VERSION 5.5 ;
NAMESCASESENSITIVE ON ;
BUSBITCHARS "[]" ;
DIVIDERCHAR "/" ;

PROPERTYDEFINITIONS
  LAYER routingPitch REAL ;
END PROPERTYDEFINITIONS

UNITS
  DATABASE MICRONS 1000 ;
END UNITS
MANUFACTURINGGRID 0.01 ;
LAYER POLY1
  TYPE MASTERSLICE ;
END POLY1

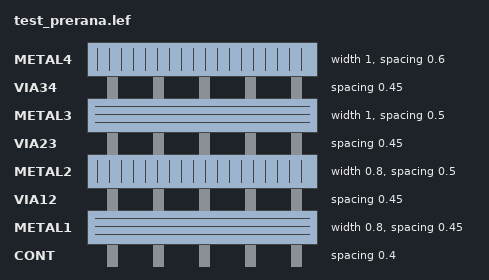
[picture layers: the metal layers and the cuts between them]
LAYER CONT
  TYPE CUT ;
  SPACING 0.4 ;
END CONT

LAYER METAL1
  TYPE ROUTING ;
  DIRECTION HORIZONTAL ;
  PITCH 0 ;
  WIDTH 0.8 ;
  SPACING 0.45 ;
  PROPERTY routingPitch 1.25 ;
END METAL1

LAYER VIA12
  TYPE CUT ;
  SPACING 0.45 ;
END VIA12

LAYER METAL2
  TYPE ROUTING ;
  DIRECTION VERTICAL ;
  PITCH 0 ;
  WIDTH 0.8 ;
  SPACING 0.5 ;
  PROPERTY routingPitch 1.4 ;
END METAL2

LAYER VIA23
  TYPE CUT ;
  SPACING 0.45 ;
END VIA23

LAYER METAL3
  TYPE ROUTING ;
  DIRECTION HORIZONTAL ;
  PITCH 0 ;
  WIDTH 1.0 ;
  SPACING 0.5 ;
  PROPERTY routingPitch 1.25 ;
END METAL3

LAYER VIA34
  TYPE CUT ;
  SPACING 0.45 ;
END VIA34

LAYER METAL4
  TYPE ROUTING ;
  DIRECTION VERTICAL ;
  PITCH 0 ;
  WIDTH 1.0 ;
  SPACING 0.6 ;
  PROPERTY routingPitch 1.4 ;
END METAL4

LAYER OVERLAP
  TYPE OVERLAP ;
END OVERLAP

VIARULE M4_M3 GENERATE
  LAYER METAL3 ;
    ENCLOSURE 0.2 0.2 ;
  LAYER METAL4 ;
    ENCLOSURE 0.15 0.15 ;
  LAYER VIA34 ;
    RECT -0.25 -0.25 0.25 0.25 ;
    SPACING 1 BY 1 ;
END M4_M3

VIARULE M3_M2 GENERATE
  LAYER METAL2 ;
    ENCLOSURE 0.2 0.2 ;
  LAYER METAL3 ;
    ENCLOSURE 0.15 0.15 ;
  LAYER VIA23 ;
    RECT -0.25 -0.25 0.25 0.25 ;
    SPACING 1 BY 1 ;
END M3_M2

VIARULE M2_M1 GENERATE
  LAYER METAL1 ;
    ENCLOSURE 0.2 0.2 ;
  LAYER METAL2 ;
    ENCLOSURE 0.15 0.15 ;
  LAYER VIA12 ;
    RECT -0.25 -0.25 0.25 0.25 ;
    SPACING 1 BY 1 ;
END M2_M1

VIARULE M1_POLY1 GENERATE
  LAYER POLY1 ;
    ENCLOSURE 0.2 0.2 ;
  LAYER METAL1 ;
    ENCLOSURE 0.15 0.15 ;
  LAYER CONT ;
    RECT -0.2 -0.2 0.2 0.2 ;
    SPACING 1 BY 1 ;
END M1_POLY1

VIA M1_POLY1
  LAYER CONT ;
    RECT -0.2 -0.2 0.2 0.2 ;
  LAYER POLY1 ;
    RECT -0.4 -0.4 0.4 0.4 ;
  LAYER METAL1 ;
    RECT -0.35 -0.35 0.35 0.35 ;
END M1_POLY1

VIA M2_M1
  LAYER VIA12 ;
    RECT -0.25 -0.25 0.25 0.25 ;
  LAYER METAL2 ;
    RECT -0.4 -0.4 0.4 0.4 ;
  LAYER METAL1 ;
    RECT -0.45 -0.45 0.45 0.45 ;
END M2_M1

VIA M3_M2
  LAYER VIA23 ;
    RECT -0.25 -0.25 0.25 0.25 ;
  LAYER METAL3 ;
    RECT -0.4 -0.4 0.4 0.4 ;
  LAYER METAL2 ;
    RECT -0.45 -0.45 0.45 0.45 ;
END M3_M2

VIA M4_M3
  LAYER VIA34 ;
    RECT -0.25 -0.25 0.25 0.25 ;
  LAYER METAL4 ;
    RECT -0.4 -0.4 0.4 0.4 ;
  LAYER METAL3 ;
    RECT -0.45 -0.45 0.45 0.45 ;
END M4_M3


MACRO Full_Macro_2p0_abstract
  PIN smclk_per_ext
    DIRECTION INOUT ;
    USE SIGNAL ;
    PORT
      LAYER METAL2 ;
        RECT 4738.52 82.5 4739.52 83.5 ;
    END
  END smclk_per_ext
  PIN unused_AN_MUX
    DIRECTION INOUT ;
    USE SIGNAL ;
    PORT
      LAYER METAL2 ;
        RECT 4784.2 45.0 4784.8 45.6 ;
    END
  END unused_AN_MUX
  PIN SystemDrainline<0>
    DIRECTION INOUT ;
    USE SIGNAL ;
    PORT
      LAYER METAL2 ;
        RECT 5600.2 45.0 5601.2 46.0 ;
    END
  END SystemDrainline<0>
  PIN SystemDrainline<1>
    DIRECTION INOUT ;
    USE SIGNAL ;
    PORT
      LAYER METAL2 ;
        RECT 5551.2 45.0 5552.2 46.0 ;
    END
  END SystemDrainline<1>
  PIN SystemDrainline<2>
    DIRECTION INOUT ;
    USE SIGNAL ;
    PORT
      LAYER METAL2 ;
        RECT 5500.8 45.0 5501.8 46.0 ;
    END
  END SystemDrainline<2>
  PIN V_IO
    DIRECTION INOUT ;
    USE SIGNAL ;
    PORT
      LAYER METAL2 ;
        RECT 5649.2 45.0 5650.2 46.0 ;
    END
  END V_IO
  PIN VTUN_AM
    DIRECTION INOUT ;
    USE SIGNAL ;
    PORT
      LAYER METAL2 ;
        RECT 5699.6 45.0 5700.6 46.0 ;
    END
  END VTUN_AM
  PIN VG_IO
    DIRECTION INOUT ;
    USE SIGNAL ;
    PORT
      LAYER METAL2 ;
        RECT 5748.6 45.0 5749.6 46.0 ;
    END
  END VG_IO
  PIN VGRUN
    DIRECTION INOUT ;
    USE SIGNAL ;
    PORT
      LAYER METAL2 ;
        RECT 5799.0 45.0 5800.0 46.0 ;
    END
  END VGRUN
  PIN VGPROG_IO
    DIRECTION INOUT ;
    USE SIGNAL ;
    PORT
      LAYER METAL2 ;
        RECT 5848.0 45.0 5849.0 46.0 ;
    END
  END VGPROG_IO
  PIN VGPROG
    DIRECTION INOUT ;
    USE SIGNAL ;
    PORT
      LAYER METAL2 ;
        RECT 5897.0 45.0 5898.0 46.0 ;
    END
  END VGPROG
  PIN VD_IO
    DIRECTION INOUT ;
    USE SIGNAL ;
    PORT
      LAYER METAL2 ;
        RECT 5947.4 45.0 5948.4 46.0 ;
    END
  END VD_IO
  PIN I_IO
    DIRECTION INOUT ;
    USE SIGNAL ;
    PORT
      LAYER METAL2 ;
        RECT 5996.4 45.0 5997.4 46.0 ;
    END
  END I_IO
  PIN Debug_IO
    DIRECTION INOUT ;
    USE SIGNAL ;
    PORT
      LAYER METAL2 ;
        RECT 6046.8 45.0 6047.8 46.0 ;
    END
  END Debug_IO
  PIN Cal_Vin
    DIRECTION INOUT ;
    USE SIGNAL ;
    PORT
      LAYER METAL2 ;
        RECT 6095.8 45.0 6096.8 46.0 ;
    END
  END Cal_Vin
  PIN Cal_IO
    DIRECTION INOUT ;
    USE SIGNAL ;
    PORT
      LAYER METAL2 ;
        RECT 6269.4 293.75 6270.4 294.35 ;
    END
  END Cal_IO
  PIN Bias_Trim
    DIRECTION INOUT ;
    USE SIGNAL ;
    PORT
      LAYER METAL2 ;
        RECT 6195.2 45.0 6196.2 46.0 ;
    END
  END Bias_Trim
  PIN AVDD
    DIRECTION INOUT ;
    USE SIGNAL ;
    PORT
      LAYER METAL2 ;
        RECT 6293.2 293.75 6294.2 294.75 ;
    END
  END AVDD
  PIN VINJ
    DIRECTION INOUT ;
    USE SIGNAL ;
    PORT
      LAYER METAL2 ;
        RECT 6253.39 293.75 6254.39 294.75 ;
    END
  END VINJ
  PIN DVDD
    DIRECTION INOUT ;
    USE SIGNAL ;
    PORT
      LAYER METAL2 ;
        RECT 4833.0 45.0 4834.0 46.0 ;
    END
  END DVDD
  PIN VTUN_fgmem
    DIRECTION INOUT ;
    USE SIGNAL ;
    PORT
      LAYER METAL2 ;
        RECT 4856.8 45.0 4857.8 46.0 ;
    END
  END VTUN_fgmem
  PIN Signal_DAC_out<0>
    DIRECTION INOUT ;
    USE SIGNAL ;
    PORT
      LAYER METAL2 ;
        RECT 5401.4 45.0 5402.4 46.0 ;
    END
  END Signal_DAC_out<0>
  PIN Signal_DAC_out<1>
    DIRECTION INOUT ;
    USE SIGNAL ;
    PORT
      LAYER METAL2 ;
        RECT 5352.4 45.0 5353.4 46.0 ;
    END
  END Signal_DAC_out<1>
  PIN Signal_DAC_out<2>
    DIRECTION INOUT ;
    USE SIGNAL ;
    PORT
      LAYER METAL2 ;
        RECT 5303.4 45.0 5304.4 46.0 ;
    END
  END Signal_DAC_out<2>
  PIN RUN_HV
    DIRECTION INOUT ;
    USE SIGNAL ;
    PORT
      LAYER METAL2 ;
        RECT 1.6 195.0 2.6 196.0 ;
    END
  END RUN_HV
  PIN PROG_HV
    DIRECTION INOUT ;
    USE SIGNAL ;
    PORT
      LAYER METAL2 ;
        RECT 50.6 195.0 51.6 196.0 ;
    END
  END PROG_HV
  PIN pulse_fr_drain
    DIRECTION INOUT ;
    USE SIGNAL ;
    PORT
      LAYER METAL2 ;
        RECT 5451.8 45.0 5452.8 46.0 ;
    END
  END pulse_fr_drain
  PIN mmio_reg_10_bout<0>
    DIRECTION INOUT ;
    USE SIGNAL ;
    PORT
      LAYER METAL2 ;
        RECT 3518.4 82.5 3519.4 83.5 ;
    END
  END mmio_reg_10_bout<0>
  PIN mmio_reg_10_bout<1>
    DIRECTION INOUT ;
    USE SIGNAL ;
    PORT
      LAYER METAL2 ;
        RECT 3469.4 82.5 3470.4 83.5 ;
    END
  END mmio_reg_10_bout<1>
  PIN mmio_reg_10_bout<2>
    DIRECTION INOUT ;
    USE SIGNAL ;
    PORT
      LAYER METAL2 ;
        RECT 3420.4 82.5 3421.4 83.5 ;
    END
  END mmio_reg_10_bout<2>
  PIN mmio_reg_10_bout<3>
    DIRECTION INOUT ;
    USE SIGNAL ;
    PORT
      LAYER METAL2 ;
        RECT 3370.0 82.5 3371.0 83.5 ;
    END
  END mmio_reg_10_bout<3>
  PIN mmio_reg_10_bout<4>
    DIRECTION INOUT ;
    USE SIGNAL ;
    PORT
      LAYER METAL2 ;
        RECT 3321.0 82.5 3322.0 83.5 ;
    END
  END mmio_reg_10_bout<4>
  PIN mmio_reg_10_bout<5>
    DIRECTION INOUT ;
    USE SIGNAL ;
    PORT
      LAYER METAL2 ;
        RECT 3270.6 82.5 3271.6 83.5 ;
    END
  END mmio_reg_10_bout<5>
  PIN mmio_reg_10_bout<6>
    DIRECTION INOUT ;
    USE SIGNAL ;
    PORT
      LAYER METAL2 ;
        RECT 3221.6 82.5 3222.6 83.5 ;
    END
  END mmio_reg_10_bout<6>
  PIN mmio_reg_10_bout<7>
    DIRECTION INOUT ;
    USE SIGNAL ;
    PORT
      LAYER METAL2 ;
        RECT 3172.6 82.5 3173.6 83.5 ;
    END
  END mmio_reg_10_bout<7>
  PIN mmio_reg_10_bout<8>
    DIRECTION INOUT ;
    USE SIGNAL ;
    PORT
      LAYER METAL2 ;
        RECT 3122.2 82.5 3123.2 83.5 ;
    END
  END mmio_reg_10_bout<8>
  PIN mmio_reg_10_bout<9>
    DIRECTION INOUT ;
    USE SIGNAL ;
    PORT
      LAYER METAL2 ;
        RECT 3073.2 82.5 3074.2 83.5 ;
    END
  END mmio_reg_10_bout<9>
  PIN mmio_reg_10_bout<10>
    DIRECTION INOUT ;
    USE SIGNAL ;
    PORT
      LAYER METAL2 ;
        RECT 3024.2 82.5 3025.2 83.5 ;
    END
  END mmio_reg_10_bout<10>
  PIN mmio_reg_10_bout<11>
    DIRECTION INOUT ;
    USE SIGNAL ;
    PORT
      LAYER METAL2 ;
        RECT 2973.8 82.5 2974.8 83.5 ;
    END
  END mmio_reg_10_bout<11>
  PIN mmio_reg_10_bout<12>
    DIRECTION INOUT ;
    USE SIGNAL ;
    PORT
      LAYER METAL2 ;
        RECT 2924.8 82.5 2925.8 83.5 ;
    END
  END mmio_reg_10_bout<12>
  PIN mmio_reg_10_bout<13>
    DIRECTION INOUT ;
    USE SIGNAL ;
    PORT
      LAYER METAL2 ;
        RECT 2874.4 82.5 2875.4 83.5 ;
    END
  END mmio_reg_10_bout<13>
  PIN mmio_reg_10_bout<14>
    DIRECTION INOUT ;
    USE SIGNAL ;
    PORT
      LAYER METAL2 ;
        RECT 2825.4 82.5 2826.4 83.5 ;
    END
  END mmio_reg_10_bout<14>
  PIN mmio_reg_10_bout<15>
    DIRECTION INOUT ;
    USE SIGNAL ;
    PORT
      LAYER METAL2 ;
        RECT 2776.4 82.5 2777.4 83.5 ;
    END
  END mmio_reg_10_bout<15>
  PIN mmio_reg_9_bout<0>
    DIRECTION INOUT ;
    USE SIGNAL ;
    PORT
      LAYER METAL2 ;
        RECT 4312.2 82.5 4313.2 83.5 ;
    END
  END mmio_reg_9_bout<0>
  PIN mmio_reg_9_bout<1>
    DIRECTION INOUT ;
    USE SIGNAL ;
    PORT
      LAYER METAL2 ;
        RECT 4261.8 82.5 4262.8 83.5 ;
    END
  END mmio_reg_9_bout<1>
  PIN mmio_reg_9_bout<2>
    DIRECTION INOUT ;
    USE SIGNAL ;
    PORT
      LAYER METAL2 ;
        RECT 4212.8 82.5 4213.8 83.5 ;
    END
  END mmio_reg_9_bout<2>
  PIN mmio_reg_9_bout<3>
    DIRECTION INOUT ;
    USE SIGNAL ;
    PORT
      LAYER METAL2 ;
        RECT 4163.8 82.5 4164.8 83.5 ;
    END
  END mmio_reg_9_bout<3>
  PIN mmio_reg_9_bout<4>
    DIRECTION INOUT ;
    USE SIGNAL ;
    PORT
      LAYER METAL2 ;
        RECT 4113.4 82.5 4114.4 83.5 ;
    END
  END mmio_reg_9_bout<4>
  PIN mmio_reg_9_bout<5>
    DIRECTION INOUT ;
    USE SIGNAL ;
    PORT
      LAYER METAL2 ;
        RECT 4064.4 82.5 4065.4 83.5 ;
    END
  END mmio_reg_9_bout<5>
  PIN mmio_reg_9_bout<6>
    DIRECTION INOUT ;
    USE SIGNAL ;
    PORT
      LAYER METAL2 ;
        RECT 4014.0 82.5 4015.0 83.5 ;
    END
  END mmio_reg_9_bout<6>
  PIN mmio_reg_9_bout<7>
    DIRECTION INOUT ;
    USE SIGNAL ;
    PORT
      LAYER METAL2 ;
        RECT 3965.0 82.5 3966.0 83.5 ;
    END
  END mmio_reg_9_bout<7>
  PIN mmio_reg_9_bout<8>
    DIRECTION INOUT ;
    USE SIGNAL ;
    PORT
      LAYER METAL2 ;
        RECT 3916.0 82.5 3917.0 83.5 ;
    END
  END mmio_reg_9_bout<8>
  PIN mmio_reg_9_bout<9>
    DIRECTION INOUT ;
    USE SIGNAL ;
    PORT
      LAYER METAL2 ;
        RECT 3865.6 82.5 3866.6 83.5 ;
    END
  END mmio_reg_9_bout<9>
  PIN mmio_reg_9_bout<10>
    DIRECTION INOUT ;
    USE SIGNAL ;
    PORT
      LAYER METAL2 ;
        RECT 3816.6 82.5 3817.6 83.5 ;
    END
  END mmio_reg_9_bout<10>
  PIN mmio_reg_9_bout<11>
    DIRECTION INOUT ;
    USE SIGNAL ;
    PORT
      LAYER METAL2 ;
        RECT 3766.2 82.5 3767.2 83.5 ;
    END
  END mmio_reg_9_bout<11>
  PIN mmio_reg_9_bout<12>
    DIRECTION INOUT ;
    USE SIGNAL ;
    PORT
      LAYER METAL2 ;
        RECT 3717.2 82.5 3718.2 83.5 ;
    END
  END mmio_reg_9_bout<12>
  PIN mmio_reg_9_bout<13>
    DIRECTION INOUT ;
    USE SIGNAL ;
    PORT
      LAYER METAL2 ;
        RECT 3668.2 82.5 3669.2 83.5 ;
    END
  END mmio_reg_9_bout<13>
  PIN mmio_reg_9_bout<14>
    DIRECTION INOUT ;
    USE SIGNAL ;
    PORT
      LAYER METAL2 ;
        RECT 3617.8 82.5 3618.8 83.5 ;
    END
  END mmio_reg_9_bout<14>
  PIN mmio_reg_9_bout<15>
    DIRECTION INOUT ;
    USE SIGNAL ;
    PORT
      LAYER METAL2 ;
        RECT 3568.8 82.5 3569.8 83.5 ;
    END
  END mmio_reg_9_bout<15>
  PIN mmio_reg_5_vinj<0>
    DIRECTION INOUT ;
    USE SIGNAL ;
    PORT
      LAYER METAL2 ;
        RECT 4807.8 45.0 4808.8 46.0 ;
    END
  END mmio_reg_5_vinj<0>
  PIN mmio_reg_5_vinj<1>
    DIRECTION INOUT ;
    USE SIGNAL ;
    PORT
      LAYER METAL2 ;
        RECT 4757.4 82.5 4758.4 83.5 ;
    END
  END mmio_reg_5_vinj<1>
  PIN mmio_reg_5_vinj<2>
    DIRECTION INOUT ;
    USE SIGNAL ;
    PORT
      LAYER METAL2 ;
        RECT 4708.4 82.5 4709.4 83.5 ;
    END
  END mmio_reg_5_vinj<2>
  PIN mmio_reg_5_vinj<3>
    DIRECTION INOUT ;
    USE SIGNAL ;
    PORT
      LAYER METAL2 ;
        RECT 4659.4 82.5 4660.4 83.5 ;
    END
  END mmio_reg_5_vinj<3>
  PIN mmio_reg_5_vinj<4>
    DIRECTION INOUT ;
    USE SIGNAL ;
    PORT
      LAYER METAL2 ;
        RECT 4609.0 82.5 4610.0 83.5 ;
    END
  END mmio_reg_5_vinj<4>
  PIN mmio_reg_5_vinj<5>
    DIRECTION INOUT ;
    USE SIGNAL ;
    PORT
      LAYER METAL2 ;
        RECT 4560.0 82.5 4561.0 83.5 ;
    END
  END mmio_reg_5_vinj<5>
  PIN mmio_reg_5_vinj<6>
    DIRECTION INOUT ;
    USE SIGNAL ;
    PORT
      LAYER METAL2 ;
        RECT 4509.6 82.5 4510.6 83.5 ;
    END
  END mmio_reg_5_vinj<6>
  PIN mmio_reg_5_vinj<7>
    DIRECTION INOUT ;
    USE SIGNAL ;
    PORT
      LAYER METAL2 ;
        RECT 4460.6 82.5 4461.6 83.5 ;
    END
  END mmio_reg_5_vinj<7>
  PIN mmio_reg_5_vinj<8>
    DIRECTION INOUT ;
    USE SIGNAL ;
    PORT
      LAYER METAL2 ;
        RECT 4411.6 82.5 4412.6 83.5 ;
    END
  END mmio_reg_5_vinj<8>
  PIN mmio_reg_5_vinj<9>
    DIRECTION INOUT ;
    USE SIGNAL ;
    PORT
      LAYER METAL2 ;
        RECT 4361.2 82.5 4362.2 83.5 ;
    END
  END mmio_reg_5_vinj<9>
  PIN prog_lv
    DIRECTION INOUT ;
    USE SIGNAL ;
    PORT
      LAYER METAL2 ;
        RECT 99.6 195.0 100.6 196.0 ;
    END
  END prog_lv
  PIN puc_rst_bout
    DIRECTION INOUT ;
    USE SIGNAL ;
    PORT
      LAYER METAL2 ;
        RECT 2726.0 82.5 2727.0 83.5 ;
    END
  END puc_rst_bout
  PIN per_we_bout<0>
    DIRECTION INOUT ;
    USE SIGNAL ;
    PORT
      LAYER METAL2 ;
        RECT 2626.6 82.5 2627.6 83.5 ;
    END
  END per_we_bout<0>
  PIN per_we_bout<1>
    DIRECTION INOUT ;
    USE SIGNAL ;
    PORT
      LAYER METAL2 ;
        RECT 2577.6 82.5 2578.6 83.5 ;
    END
  END per_we_bout<1>
  PIN per_en_bout
    DIRECTION INOUT ;
    USE SIGNAL ;
    PORT
      LAYER METAL2 ;
        RECT 2677.0 82.5 2678.0 83.5 ;
    END
  END per_en_bout
  PIN per_din_bout<0>
    DIRECTION INOUT ;
    USE SIGNAL ;
    PORT
      LAYER METAL2 ;
        RECT 2528.6 82.5 2529.6 83.5 ;
    END
  END per_din_bout<0>
  PIN per_din_bout<1>
    DIRECTION INOUT ;
    USE SIGNAL ;
    PORT
      LAYER METAL2 ;
        RECT 2478.2 82.5 2479.2 83.5 ;
    END
  END per_din_bout<1>
  PIN per_din_bout<2>
    DIRECTION INOUT ;
    USE SIGNAL ;
    PORT
      LAYER METAL2 ;
        RECT 2429.2 82.5 2430.2 83.5 ;
    END
  END per_din_bout<2>
  PIN per_din_bout<3>
    DIRECTION INOUT ;
    USE SIGNAL ;
    PORT
      LAYER METAL2 ;
        RECT 2378.8 82.5 2379.8 83.5 ;
    END
  END per_din_bout<3>
  PIN per_din_bout<4>
    DIRECTION INOUT ;
    USE SIGNAL ;
    PORT
      LAYER METAL2 ;
        RECT 2329.8 82.5 2330.8 83.5 ;
    END
  END per_din_bout<4>
  PIN per_din_bout<5>
    DIRECTION INOUT ;
    USE SIGNAL ;
    PORT
      LAYER METAL2 ;
        RECT 2280.8 82.5 2281.8 83.5 ;
    END
  END per_din_bout<5>
  PIN per_din_bout<6>
    DIRECTION INOUT ;
    USE SIGNAL ;
    PORT
      LAYER METAL2 ;
        RECT 2230.4 82.5 2231.4 83.5 ;
    END
  END per_din_bout<6>
  PIN per_din_bout<7>
    DIRECTION INOUT ;
    USE SIGNAL ;
    PORT
      LAYER METAL2 ;
        RECT 2181.4 82.5 2182.4 83.5 ;
    END
  END per_din_bout<7>
  PIN per_din_bout<8>
    DIRECTION INOUT ;
    USE SIGNAL ;
    PORT
      LAYER METAL2 ;
        RECT 2131.0 82.5 2132.0 83.5 ;
    END
  END per_din_bout<8>
  PIN per_din_bout<9>
    DIRECTION INOUT ;
    USE SIGNAL ;
    PORT
      LAYER METAL2 ;
        RECT 2082.0 82.5 2083.0 83.5 ;
    END
  END per_din_bout<9>
  PIN per_din_bout<10>
    DIRECTION INOUT ;
    USE SIGNAL ;
    PORT
      LAYER METAL2 ;
        RECT 2033.0 82.5 2034.0 83.5 ;
    END
  END per_din_bout<10>
  PIN per_din_bout<11>
    DIRECTION INOUT ;
    USE SIGNAL ;
    PORT
      LAYER METAL2 ;
        RECT 1982.6 82.5 1983.6 83.5 ;
    END
  END per_din_bout<11>
  PIN per_din_bout<12>
    DIRECTION INOUT ;
    USE SIGNAL ;
    PORT
      LAYER METAL2 ;
        RECT 1933.6 82.5 1934.6 83.5 ;
    END
  END per_din_bout<12>
  PIN per_din_bout<13>
    DIRECTION INOUT ;
    USE SIGNAL ;
    PORT
      LAYER METAL2 ;
        RECT 1883.2 82.5 1884.2 83.5 ;
    END
  END per_din_bout<13>
  PIN per_din_bout<14>
    DIRECTION INOUT ;
    USE SIGNAL ;
    PORT
      LAYER METAL2 ;
        RECT 1834.2 82.5 1835.2 83.5 ;
    END
  END per_din_bout<14>
  PIN per_din_bout<15>
    DIRECTION INOUT ;
    USE SIGNAL ;
    PORT
      LAYER METAL2 ;
        RECT 1785.2 82.5 1786.2 83.5 ;
    END
  END per_din_bout<15>
  PIN per_addr_bout<0>
    DIRECTION INOUT ;
    USE SIGNAL ;
    PORT
      LAYER METAL2 ;
        RECT 1734.8 82.5 1735.8 83.5 ;
    END
  END per_addr_bout<0>
  PIN per_addr_bout<1>
    DIRECTION INOUT ;
    USE SIGNAL ;
    PORT
      LAYER METAL2 ;
        RECT 1685.8 82.5 1686.8 83.5 ;
    END
  END per_addr_bout<1>
  PIN per_addr_bout<2>
    DIRECTION INOUT ;
    USE SIGNAL ;
    PORT
      LAYER METAL2 ;
        RECT 1635.4 82.5 1636.4 83.5 ;
    END
  END per_addr_bout<2>
  PIN per_addr_bout<3>
    DIRECTION INOUT ;
    USE SIGNAL ;
    PORT
      LAYER METAL2 ;
        RECT 1586.4 82.5 1587.4 83.5 ;
    END
  END per_addr_bout<3>
  PIN per_addr_bout<4>
    DIRECTION INOUT ;
    USE SIGNAL ;
    PORT
      LAYER METAL2 ;
        RECT 1537.4 82.5 1538.4 83.5 ;
    END
  END per_addr_bout<4>
  PIN per_addr_bout<5>
    DIRECTION INOUT ;
    USE SIGNAL ;
    PORT
      LAYER METAL2 ;
        RECT 1487.0 82.5 1488.0 83.5 ;
    END
  END per_addr_bout<5>
  PIN per_addr_bout<6>
    DIRECTION INOUT ;
    USE SIGNAL ;
    PORT
      LAYER METAL2 ;
        RECT 1438.0 82.5 1439.0 83.5 ;
    END
  END per_addr_bout<6>
  PIN per_addr_bout<7>
    DIRECTION INOUT ;
    USE SIGNAL ;
    PORT
      LAYER METAL2 ;
        RECT 1389.0 195.0 1390.0 196.0 ;
    END
  END per_addr_bout<7>
  PIN per_addr_bout<8>
    DIRECTION INOUT ;
    USE SIGNAL ;
    PORT
      LAYER METAL2 ;
        RECT 1338.6 195.0 1339.6 196.0 ;
    END
  END per_addr_bout<8>
  PIN per_addr_bout<9>
    DIRECTION INOUT ;
    USE SIGNAL ;
    PORT
      LAYER METAL2 ;
        RECT 1289.6 195.0 1290.6 196.0 ;
    END
  END per_addr_bout<9>
  PIN per_addr_bout<10>
    DIRECTION INOUT ;
    USE SIGNAL ;
    PORT
      LAYER METAL2 ;
        RECT 1239.2 195.0 1240.2 196.0 ;
    END
  END per_addr_bout<10>
  PIN per_addr_bout<11>
    DIRECTION INOUT ;
    USE SIGNAL ;
    PORT
      LAYER METAL2 ;
        RECT 1190.2 195.0 1191.2 196.0 ;
    END
  END per_addr_bout<11>
  PIN per_addr_bout<12>
    DIRECTION INOUT ;
    USE SIGNAL ;
    PORT
      LAYER METAL2 ;
        RECT 1141.2 195.0 1142.2 196.0 ;
    END
  END per_addr_bout<12>
  PIN per_addr_bout<13>
    DIRECTION INOUT ;
    USE SIGNAL ;
    PORT
      LAYER METAL2 ;
        RECT 1090.8 195.0 1091.8 196.0 ;
    END
  END per_addr_bout<13>
  PIN dbg_uart_txd
    DIRECTION INOUT ;
    USE SIGNAL ;
    PORT
      LAYER METAL2 ;
        RECT 4194.6 1414.0 4195.6 1415.0 ;
    END
  END dbg_uart_txd
  PIN Signal_RampADC_inp<0>
    DIRECTION INOUT ;
    USE SIGNAL ;
    PORT
      LAYER METAL2 ;
        RECT 5153.6 45.0 5154.6 46.0 ;
    END
  END Signal_RampADC_inp<0>
  PIN Signal_RampADC_inp<1>
    DIRECTION INOUT ;
    USE SIGNAL ;
    PORT
      LAYER METAL2 ;
        RECT 5104.6 45.0 5105.6 46.0 ;
    END
  END Signal_RampADC_inp<1>
  PIN Signal_RampADC_inp<2>
    DIRECTION INOUT ;
    USE SIGNAL ;
    PORT
      LAYER METAL2 ;
        RECT 5055.6 45.0 5056.6 46.0 ;
    END
  END Signal_RampADC_inp<2>
  PIN Signal_RampADC_inp<3>
    DIRECTION INOUT ;
    USE SIGNAL ;
    PORT
      LAYER METAL2 ;
        RECT 5005.2 45.0 5006.2 46.0 ;
    END
  END Signal_RampADC_inp<3>
  PIN Signal_RampADC_inp<4>
    DIRECTION INOUT ;
    USE SIGNAL ;
    PORT
      LAYER METAL2 ;
        RECT 4956.2 45.0 4957.2 46.0 ;
    END
  END Signal_RampADC_inp<4>
  PIN Signal_RampADC_inp<5>
    DIRECTION INOUT ;
    USE SIGNAL ;
    PORT
      LAYER METAL2 ;
        RECT 4905.8 45.0 4906.8 46.0 ;
    END
  END Signal_RampADC_inp<5>
  PIN fast_clk
    DIRECTION INOUT ;
    USE SIGNAL ;
    PORT
      LAYER METAL2 ;
        RECT 418.8 1414.0 419.8 1415.0 ;
    END
  END fast_clk
  PIN scan_in2
    DIRECTION INOUT ;
    USE SIGNAL ;
    PORT
      LAYER METAL2 ;
        RECT 5873.2 1414.0 5874.2 1415.0 ;
    END
  END scan_in2
  PIN scan_in1
    DIRECTION INOUT ;
    USE SIGNAL ;
    PORT
      LAYER METAL2 ;
        RECT 5453.2 1414.0 5454.2 1415.0 ;
    END
  END scan_in1
  PIN wkup
    DIRECTION INOUT ;
    USE SIGNAL ;
    PORT
      LAYER METAL2 ;
        RECT 5033.2 1414.0 5034.2 1415.0 ;
    END
  END wkup
  PIN scan_mode
    DIRECTION INOUT ;
    USE SIGNAL ;
    PORT
      LAYER METAL2 ;
        RECT 4614.6 1414.0 4615.6 1415.0 ;
    END
  END scan_mode
  PIN scan_enable
    DIRECTION INOUT ;
    USE SIGNAL ;
    PORT
      LAYER METAL2 ;
        RECT 3776.0 1414.0 3777.0 1415.0 ;
    END
  END scan_enable
  PIN reset_n
    DIRECTION INOUT ;
    USE SIGNAL ;
    PORT
      LAYER METAL2 ;
        RECT 3356.0 1414.0 3357.0 1415.0 ;
    END
  END reset_n
  PIN per_dout_ext<0>
    DIRECTION INOUT ;
    USE SIGNAL ;
    PORT
      LAYER METAL2 ;
        RECT 1041.8 195.0 1042.8 196.0 ;
    END
  END per_dout_ext<0>
  PIN per_dout_ext<1>
    DIRECTION INOUT ;
    USE SIGNAL ;
    PORT
      LAYER METAL2 ;
        RECT 991.4 195.0 992.4 196.0 ;
    END
  END per_dout_ext<1>
  PIN per_dout_ext<2>
    DIRECTION INOUT ;
    USE SIGNAL ;
    PORT
      LAYER METAL2 ;
        RECT 942.4 195.0 943.4 196.0 ;
    END
  END per_dout_ext<2>
  PIN per_dout_ext<3>
    DIRECTION INOUT ;
    USE SIGNAL ;
    PORT
      LAYER METAL2 ;
        RECT 893.4 195.0 894.4 196.0 ;
    END
  END per_dout_ext<3>
  PIN per_dout_ext<4>
    DIRECTION INOUT ;
    USE SIGNAL ;
    PORT
      LAYER METAL2 ;
        RECT 843.0 195.0 844.0 196.0 ;
    END
  END per_dout_ext<4>
  PIN per_dout_ext<5>
    DIRECTION INOUT ;
    USE SIGNAL ;
    PORT
      LAYER METAL2 ;
        RECT 794.0 195.0 795.0 196.0 ;
    END
  END per_dout_ext<5>
  PIN per_dout_ext<6>
    DIRECTION INOUT ;
    USE SIGNAL ;
    PORT
      LAYER METAL2 ;
        RECT 743.6 195.0 744.6 196.0 ;
    END
  END per_dout_ext<6>
  PIN per_dout_ext<7>
    DIRECTION INOUT ;
    USE SIGNAL ;
    PORT
      LAYER METAL2 ;
        RECT 694.6 195.0 695.6 196.0 ;
    END
  END per_dout_ext<7>
  PIN per_dout_ext<8>
    DIRECTION INOUT ;
    USE SIGNAL ;
    PORT
      LAYER METAL2 ;
        RECT 645.6 195.0 646.6 196.0 ;
    END
  END per_dout_ext<8>
  PIN per_dout_ext<9>
    DIRECTION INOUT ;
    USE SIGNAL ;
    PORT
      LAYER METAL2 ;
        RECT 595.2 195.0 596.2 196.0 ;
    END
  END per_dout_ext<9>
  PIN per_dout_ext<10>
    DIRECTION INOUT ;
    USE SIGNAL ;
    PORT
      LAYER METAL2 ;
        RECT 546.2 195.0 547.2 196.0 ;
    END
  END per_dout_ext<10>
  PIN per_dout_ext<11>
    DIRECTION INOUT ;
    USE SIGNAL ;
    PORT
      LAYER METAL2 ;
        RECT 495.8 195.0 496.8 196.0 ;
    END
  END per_dout_ext<11>
  PIN per_dout_ext<12>
    DIRECTION INOUT ;
    USE SIGNAL ;
    PORT
      LAYER METAL2 ;
        RECT 446.8 195.0 447.8 196.0 ;
    END
  END per_dout_ext<12>
  PIN per_dout_ext<13>
    DIRECTION INOUT ;
    USE SIGNAL ;
    PORT
      LAYER METAL2 ;
        RECT 397.8 195.0 398.8 196.0 ;
    END
  END per_dout_ext<13>
  PIN per_dout_ext<14>
    DIRECTION INOUT ;
    USE SIGNAL ;
    PORT
      LAYER METAL2 ;
        RECT 347.4 195.0 348.4 196.0 ;
    END
  END per_dout_ext<14>
  PIN per_dout_ext<15>
    DIRECTION INOUT ;
    USE SIGNAL ;
    PORT
      LAYER METAL2 ;
        RECT 298.4 195.0 299.4 196.0 ;
    END
  END per_dout_ext<15>
  PIN nmi
    DIRECTION INOUT ;
    USE SIGNAL ;
    PORT
      LAYER METAL2 ;
        RECT 2936.0 1414.0 2937.0 1415.0 ;
    END
  END nmi
  PIN lfxt_clk
    DIRECTION INOUT ;
    USE SIGNAL ;
    PORT
      LAYER METAL2 ;
        RECT 0.2 1414.0 1.2 1415.0 ;
    END
  END lfxt_clk
  PIN irq<0>
    DIRECTION INOUT ;
    USE SIGNAL ;
    PORT
      LAYER METAL2 ;
        RECT 838.8 1414.0 839.8 1415.0 ;
    END
  END irq<0>
  PIN irq<1>
    DIRECTION INOUT ;
    USE SIGNAL ;
    PORT
      LAYER METAL2 ;
        RECT 1258.8 1414.0 1259.8 1415.0 ;
    END
  END irq<1>
  PIN irq<2>
    DIRECTION INOUT ;
    USE SIGNAL ;
    PORT
      LAYER METAL2 ;
        RECT 248.0 195.0 249.0 196.0 ;
    END
  END irq<2>
  PIN irq<3>
    DIRECTION INOUT ;
    USE SIGNAL ;
    PORT
      LAYER METAL2 ;
        RECT 199.0 195.0 200.0 196.0 ;
    END
  END irq<3>
  PIN irq<4>
    DIRECTION INOUT ;
    USE SIGNAL ;
    PORT
      LAYER METAL2 ;
        RECT 150.0 195.0 151.0 196.0 ;
    END
  END irq<4>
  PIN dco_clk
    DIRECTION INOUT ;
    USE SIGNAL ;
    PORT
      LAYER METAL2 ;
        RECT 6293.2 1414.0 6294.2 1415.0 ;
    END
  END dco_clk
  PIN dbg_uart_rxd
    DIRECTION INOUT ;
    USE SIGNAL ;
    PORT
      LAYER METAL2 ;
        RECT 2517.4 1414.0 2518.4 1415.0 ;
    END
  END dbg_uart_rxd
  PIN dbg_en
    DIRECTION INOUT ;
    USE SIGNAL ;
    PORT
      LAYER METAL2 ;
        RECT 2097.4 1414.0 2098.4 1415.0 ;
    END
  END dbg_en
  PIN cpu_en
    DIRECTION INOUT ;
    USE SIGNAL ;
    PORT
      LAYER METAL2 ;
        RECT 1677.4 1414.0 1678.4 1415.0 ;
    END
  END cpu_en
  PIN sram_CS_VBIAS
    DIRECTION INOUT ;
    USE SIGNAL ;
    PORT
      LAYER METAL3 ;
        RECT 4779.6 48.25 4780.6 49.25 ;
    END
  END sram_CS_VBIAS
  PIN fgmem_CS_VBIAS
    DIRECTION INOUT ;
    USE SIGNAL ;
    PORT
      LAYER METAL3 ;
        RECT 0.0 1005.75 1.0 1006.75 ;
    END
  END fgmem_CS_VBIAS
  PIN Macro_dbg_Scan_Vout
    DIRECTION INOUT ;
    USE SIGNAL ;
    PORT
      LAYER METAL3 ;
        RECT 0.0 742.0 1.0 743.0 ;
    END
  END Macro_dbg_Scan_Vout
  PIN mmio_reg_7_bout<0>
    DIRECTION INOUT ;
    USE SIGNAL ;
    PORT
      LAYER METAL3 ;
        RECT 0.0 383.25 1.0 384.25 ;
    END
  END mmio_reg_7_bout<0>
  PIN mmio_reg_7_bout<1>
    DIRECTION INOUT ;
    USE SIGNAL ;
    PORT
      LAYER METAL3 ;
        RECT 0.0 407.0 1.0 408.0 ;
    END
  END mmio_reg_7_bout<1>
  PIN mmio_reg_7_bout<2>
    DIRECTION INOUT ;
    USE SIGNAL ;
    PORT
      LAYER METAL3 ;
        RECT 0.0 430.75 1.0 431.75 ;
    END
  END mmio_reg_7_bout<2>
  PIN mmio_reg_7_bout<3>
    DIRECTION INOUT ;
    USE SIGNAL ;
    PORT
      LAYER METAL3 ;
        RECT 0.0 454.5 1.0 455.5 ;
    END
  END mmio_reg_7_bout<3>
  PIN mmio_reg_7_bout<4>
    DIRECTION INOUT ;
    USE SIGNAL ;
    PORT
      LAYER METAL3 ;
        RECT 0.0 479.5 1.0 480.5 ;
    END
  END mmio_reg_7_bout<4>
  PIN mmio_reg_7_bout<5>
    DIRECTION INOUT ;
    USE SIGNAL ;
    PORT
      LAYER METAL3 ;
        RECT 0.0 503.25 1.0 504.25 ;
    END
  END mmio_reg_7_bout<5>
  PIN mmio_reg_7_bout<6>
    DIRECTION INOUT ;
    USE SIGNAL ;
    PORT
      LAYER METAL3 ;
        RECT 0.0 527.0 1.0 528.0 ;
    END
  END mmio_reg_7_bout<6>
  PIN mmio_reg_7_bout<7>
    DIRECTION INOUT ;
    USE SIGNAL ;
    PORT
      LAYER METAL3 ;
        RECT 0.0 550.75 1.0 551.75 ;
    END
  END mmio_reg_7_bout<7>
  PIN mmio_reg_7_bout<8>
    DIRECTION INOUT ;
    USE SIGNAL ;
    PORT
      LAYER METAL3 ;
        RECT 0.0 574.5 1.0 575.5 ;
    END
  END mmio_reg_7_bout<8>
  PIN mmio_reg_7_bout<9>
    DIRECTION INOUT ;
    USE SIGNAL ;
    PORT
      LAYER METAL3 ;
        RECT 0.0 598.25 1.0 599.25 ;
    END
  END mmio_reg_7_bout<9>
  PIN mmio_reg_7_bout<10>
    DIRECTION INOUT ;
    USE SIGNAL ;
    PORT
      LAYER METAL3 ;
        RECT 0.0 622.0 1.0 623.0 ;
    END
  END mmio_reg_7_bout<10>
  PIN mmio_reg_7_bout<11>
    DIRECTION INOUT ;
    USE SIGNAL ;
    PORT
      LAYER METAL3 ;
        RECT 0.0 647.0 1.0 648.0 ;
    END
  END mmio_reg_7_bout<11>
  PIN mmio_reg_7_bout<12>
    DIRECTION INOUT ;
    USE SIGNAL ;
    PORT
      LAYER METAL3 ;
        RECT 0.0 670.75 1.0 671.75 ;
    END
  END mmio_reg_7_bout<12>
  PIN mmio_reg_7_bout<13>
    DIRECTION INOUT ;
    USE SIGNAL ;
    PORT
      LAYER METAL3 ;
        RECT 0.0 694.5 1.0 695.5 ;
    END
  END mmio_reg_7_bout<13>
  PIN mmio_reg_7_bout<14>
    DIRECTION INOUT ;
    USE SIGNAL ;
    PORT
      LAYER METAL3 ;
        RECT 0.0 718.25 1.0 719.25 ;
    END
  END mmio_reg_7_bout<14>
  PIN mmio_reg_3_vinj_b0
    DIRECTION INOUT ;
    USE SIGNAL ;
    PORT
      LAYER METAL3 ;
        RECT 0.0 1413.25 1.0 1414.25 ;
    END
  END mmio_reg_3_vinj_b0
  PIN peri_spi_mstr_cs_n_3
    DIRECTION INOUT ;
    USE SIGNAL ;
    PORT
      LAYER METAL3 ;
        RECT 0.0 359.5 1.0 360.5 ;
    END
  END peri_spi_mstr_cs_n_3
  PIN peri_spi_mstr_cs_n_2
    DIRECTION INOUT ;
    USE SIGNAL ;
    PORT
      LAYER METAL3 ;
        RECT 0.0 335.75 1.0 336.75 ;
    END
  END peri_spi_mstr_cs_n_2
  PIN peri_spi_mstr_cs_n_1
    DIRECTION INOUT ;
    USE SIGNAL ;
    PORT
      LAYER METAL3 ;
        RECT 0.0 310.75 1.0 311.75 ;
    END
  END peri_spi_mstr_cs_n_1
  PIN peri_spi_mstr_cs_n_0
    DIRECTION INOUT ;
    USE SIGNAL ;
    PORT
      LAYER METAL3 ;
        RECT 0.0 287.0 1.0 288.0 ;
    END
  END peri_spi_mstr_cs_n_0
  PIN peri_spi_mstr_mosi
    DIRECTION INOUT ;
    USE SIGNAL ;
    PORT
      LAYER METAL3 ;
        RECT 0.0 263.25 1.0 264.25 ;
    END
  END peri_spi_mstr_mosi
  PIN peri_spi_mstr_spiclk
    DIRECTION INOUT ;
    USE SIGNAL ;
    PORT
      LAYER METAL3 ;
        RECT 0.0 215.75 1.0 216.75 ;
    END
  END peri_spi_mstr_spiclk
  PIN peri_spi_slave_miso
    DIRECTION INOUT ;
    USE SIGNAL ;
    PORT
      LAYER METAL3 ;
        RECT 1411.2 143.25 1412.2 144.25 ;
    END
  END peri_spi_slave_miso
  PIN scan_out2_bout
    DIRECTION INOUT ;
    USE SIGNAL ;
    PORT
      LAYER METAL3 ;
        RECT 0.0 958.25 1.0 959.25 ;
    END
  END scan_out2_bout
  PIN scan_out1_bout
    DIRECTION INOUT ;
    USE SIGNAL ;
    PORT
      LAYER METAL3 ;
        RECT 0.0 982.0 1.0 983.0 ;
    END
  END scan_out1_bout
  PIN lfxt_wkup_bout
    DIRECTION INOUT ;
    USE SIGNAL ;
    PORT
      LAYER METAL3 ;
        RECT 0.0 933.25 1.0 934.25 ;
    END
  END lfxt_wkup_bout
  PIN lfxt_enable_bout
    DIRECTION INOUT ;
    USE SIGNAL ;
    PORT
      LAYER METAL3 ;
        RECT 0.0 909.5 1.0 910.5 ;
    END
  END lfxt_enable_bout
  PIN dco_wkup_bout
    DIRECTION INOUT ;
    USE SIGNAL ;
    PORT
      LAYER METAL3 ;
        RECT 0.0 885.75 1.0 886.75 ;
    END
  END dco_wkup_bout
  PIN dco_enable_bout
    DIRECTION INOUT ;
    USE SIGNAL ;
    PORT
      LAYER METAL3 ;
        RECT 0.0 862.0 1.0 863.0 ;
    END
  END dco_enable_bout
  PIN dbg_freeze_bout
    DIRECTION INOUT ;
    USE SIGNAL ;
    PORT
      LAYER METAL3 ;
        RECT 0.0 838.25 1.0 839.25 ;
    END
  END dbg_freeze_bout
  PIN Macro_dbg_Scan_RST
    DIRECTION INOUT ;
    USE SIGNAL ;
    PORT
      LAYER METAL3 ;
        RECT 0.0 814.5 1.0 815.5 ;
    END
  END Macro_dbg_Scan_RST
  PIN Macro_dbg_Scan_Din
    DIRECTION INOUT ;
    USE SIGNAL ;
    PORT
      LAYER METAL3 ;
        RECT 0.0 790.75 1.0 791.75 ;
    END
  END Macro_dbg_Scan_Din
  PIN Macro_dbg_Scan_CLK
    DIRECTION INOUT ;
    USE SIGNAL ;
    PORT
      LAYER METAL3 ;
        RECT 0.0 765.75 1.0 766.75 ;
    END
  END Macro_dbg_Scan_CLK
  PIN mmio_reg_in_5<0>
    DIRECTION INOUT ;
    USE SIGNAL ;
    PORT
      LAYER METAL3 ;
        RECT 0.0 1029.5 1.0 1030.5 ;
    END
  END mmio_reg_in_5<0>
  PIN mmio_reg_in_5<1>
    DIRECTION INOUT ;
    USE SIGNAL ;
    PORT
      LAYER METAL3 ;
        RECT 0.0 1053.25 1.0 1054.25 ;
    END
  END mmio_reg_in_5<1>
  PIN mmio_reg_in_5<2>
    DIRECTION INOUT ;
    USE SIGNAL ;
    PORT
      LAYER METAL3 ;
        RECT 0.0 1077.0 1.0 1078.0 ;
    END
  END mmio_reg_in_5<2>
  PIN mmio_reg_in_5<3>
    DIRECTION INOUT ;
    USE SIGNAL ;
    PORT
      LAYER METAL3 ;
        RECT 0.0 1102.0 1.0 1103.0 ;
    END
  END mmio_reg_in_5<3>
  PIN mmio_reg_in_5<4>
    DIRECTION INOUT ;
    USE SIGNAL ;
    PORT
      LAYER METAL3 ;
        RECT 0.0 1125.75 1.0 1126.75 ;
    END
  END mmio_reg_in_5<4>
  PIN mmio_reg_in_5<5>
    DIRECTION INOUT ;
    USE SIGNAL ;
    PORT
      LAYER METAL3 ;
        RECT 0.0 1149.5 1.0 1150.5 ;
    END
  END mmio_reg_in_5<5>
  PIN mmio_reg_in_5<6>
    DIRECTION INOUT ;
    USE SIGNAL ;
    PORT
      LAYER METAL3 ;
        RECT 0.0 1173.25 1.0 1174.25 ;
    END
  END mmio_reg_in_5<6>
  PIN mmio_reg_in_5<7>
    DIRECTION INOUT ;
    USE SIGNAL ;
    PORT
      LAYER METAL3 ;
        RECT 0.0 1197.0 1.0 1198.0 ;
    END
  END mmio_reg_in_5<7>
  PIN mmio_reg_in_5<8>
    DIRECTION INOUT ;
    USE SIGNAL ;
    PORT
      LAYER METAL3 ;
        RECT 0.0 1220.75 1.0 1221.75 ;
    END
  END mmio_reg_in_5<8>
  PIN mmio_reg_in_5<9>
    DIRECTION INOUT ;
    USE SIGNAL ;
    PORT
      LAYER METAL3 ;
        RECT 0.0 1244.5 1.0 1245.5 ;
    END
  END mmio_reg_in_5<9>
  PIN mmio_reg_in_5<10>
    DIRECTION INOUT ;
    USE SIGNAL ;
    PORT
      LAYER METAL3 ;
        RECT 0.0 1269.5 1.0 1270.5 ;
    END
  END mmio_reg_in_5<10>
  PIN mmio_reg_in_5<11>
    DIRECTION INOUT ;
    USE SIGNAL ;
    PORT
      LAYER METAL3 ;
        RECT 0.0 1293.25 1.0 1294.25 ;
    END
  END mmio_reg_in_5<11>
  PIN mmio_reg_in_5<12>
    DIRECTION INOUT ;
    USE SIGNAL ;
    PORT
      LAYER METAL3 ;
        RECT 0.0 1317.0 1.0 1318.0 ;
    END
  END mmio_reg_in_5<12>
  PIN mmio_reg_in_5<13>
    DIRECTION INOUT ;
    USE SIGNAL ;
    PORT
      LAYER METAL3 ;
        RECT 0.0 1340.75 1.0 1341.75 ;
    END
  END mmio_reg_in_5<13>
  PIN mmio_reg_in_5<14>
    DIRECTION INOUT ;
    USE SIGNAL ;
    PORT
      LAYER METAL3 ;
        RECT 0.0 1364.5 1.0 1365.5 ;
    END
  END mmio_reg_in_5<14>
  PIN mmio_reg_in_5<15>
    DIRECTION INOUT ;
    USE SIGNAL ;
    PORT
      LAYER METAL3 ;
        RECT 0.0 1388.25 1.0 1389.25 ;
    END
  END mmio_reg_in_5<15>
  PIN peri_spi_mstr_miso
    DIRECTION INOUT ;
    USE SIGNAL ;
    PORT
      LAYER METAL3 ;
        RECT 0.0 239.5 1.0 240.5 ;
    END
  END peri_spi_mstr_miso
  PIN peri_spi_slave_cs_n
    DIRECTION INOUT ;
    USE SIGNAL ;
    PORT
      LAYER METAL3 ;
        RECT 1411.2 192.0 1412.2 193.0 ;
    END
  END peri_spi_slave_cs_n
  PIN peri_spi_slave_mosi
    DIRECTION INOUT ;
    USE SIGNAL ;
    PORT
      LAYER METAL3 ;
        RECT 1411.2 168.25 1412.2 169.25 ;
    END
  END peri_spi_slave_mosi
  PIN peri_spi_slave_clk
    DIRECTION INOUT ;
    USE SIGNAL ;
    PORT
      LAYER METAL3 ;
        RECT 1411.2 119.5 1412.2 120.5 ;
    END
  END peri_spi_slave_clk
  PIN peri_spi_cpu_clk
    DIRECTION INOUT ;
    USE SIGNAL ;
    PORT
      LAYER METAL3 ;
        RECT 1411.2 95.75 1412.2 96.75 ;
    END
  END peri_spi_cpu_clk
  PIN peri_use_uP
    DIRECTION INOUT ;
    USE SIGNAL ;
    PORT
      LAYER METAL3 ;
        RECT 4779.6 72.0 4780.6 73.0 ;
    END
  END peri_use_uP
  PIN ADC_Trim
    DIRECTION INOUT ;
    USE SIGNAL ;
    PORT
      LAYER METAL4 ;
        RECT 6241.24 293.75 6242.24 294.75 ;
    END
  END ADC_Trim
  PIN GND
    DIRECTION INOUT ;
    USE SIGNAL ;
    PORT
      LAYER METAL4 ;
        RECT 4879.46 45.0 4880.46 46.0 ;
    END
  END GND
END Full_Macro_2p0_abstract

MACRO TSMC350nm_LVLShift_x16
  PIN OUT<2>
    DIRECTION INOUT ;
    USE SIGNAL ;
    PORT
      LAYER METAL2 ;
        RECT 30.67 0.0 32.07 0.85 ;
    END
  END OUT<2>
  PIN OUT<15>
    DIRECTION INOUT ;
    USE SIGNAL ;
    PORT
      LAYER METAL2 ;
        RECT 171.23 0.0 172.63 0.85 ;
    END
  END OUT<15>
  PIN OUT<13>
    DIRECTION INOUT ;
    USE SIGNAL ;
    PORT
      LAYER METAL2 ;
        RECT 148.97 0.0 150.37 0.85 ;
    END
  END OUT<13>
  PIN OUT<14>
    DIRECTION INOUT ;
    USE SIGNAL ;
    PORT
      LAYER METAL2 ;
        RECT 164.23 0.0 165.63 0.85 ;
    END
  END OUT<14>
  PIN OUT<11>
    DIRECTION INOUT ;
    USE SIGNAL ;
    PORT
      LAYER METAL2 ;
        RECT 126.71 0.0 128.11 0.85 ;
    END
  END OUT<11>
  PIN OUT<12>
    DIRECTION INOUT ;
    USE SIGNAL ;
    PORT
      LAYER METAL2 ;
        RECT 141.97 0.0 143.37 0.85 ;
    END
  END OUT<12>
  PIN OUT<9>
    DIRECTION INOUT ;
    USE SIGNAL ;
    PORT
      LAYER METAL2 ;
        RECT 104.45 0.0 105.85 0.85 ;
    END
  END OUT<9>
  PIN OUT<10>
    DIRECTION INOUT ;
    USE SIGNAL ;
    PORT
      LAYER METAL2 ;
        RECT 119.71 0.0 121.11 0.85 ;
    END
  END OUT<10>
  PIN OUT<7>
    DIRECTION INOUT ;
    USE SIGNAL ;
    PORT
      LAYER METAL2 ;
        RECT 82.19 0.0 83.59 0.85 ;
    END
  END OUT<7>
  PIN OUT<8>
    DIRECTION INOUT ;
    USE SIGNAL ;
    PORT
      LAYER METAL2 ;
        RECT 97.45 0.0 98.85 0.85 ;
    END
  END OUT<8>
  PIN OUT<5>
    DIRECTION INOUT ;
    USE SIGNAL ;
    PORT
      LAYER METAL2 ;
        RECT 59.93 0.0 61.33 0.85 ;
    END
  END OUT<5>
  PIN OUT<6>
    DIRECTION INOUT ;
    USE SIGNAL ;
    PORT
      LAYER METAL2 ;
        RECT 75.19 0.0 76.59 0.85 ;
    END
  END OUT<6>
  PIN OUT<3>
    DIRECTION INOUT ;
    USE SIGNAL ;
    PORT
      LAYER METAL2 ;
        RECT 37.67 0.0 39.07 0.85 ;
    END
  END OUT<3>
  PIN OUT<4>
    DIRECTION INOUT ;
    USE SIGNAL ;
    PORT
      LAYER METAL2 ;
        RECT 52.93 0.0 54.33 0.85 ;
    END
  END OUT<4>
  PIN Vin<12>
    DIRECTION INOUT ;
    USE SIGNAL ;
    PORT
      LAYER METAL2 ;
        RECT 141.4 31.5 142.82 32.25 ;
    END
  END Vin<12>
  PIN Vin<1>
    DIRECTION INOUT ;
    USE SIGNAL ;
    PORT
      LAYER METAL2 ;
        RECT 15.96 31.5 17.5 32.25 ;
    END
  END Vin<1>
  PIN Vin<3>
    DIRECTION INOUT ;
    USE SIGNAL ;
    PORT
      LAYER METAL2 ;
        RECT 38.22 31.5 39.9 32.25 ;
    END
  END Vin<3>
  PIN Vin<7>
    DIRECTION INOUT ;
    USE SIGNAL ;
    PORT
      LAYER METAL2 ;
        RECT 82.74 31.5 84.7 32.25 ;
    END
  END Vin<7>
  PIN Vin<15>
    DIRECTION INOUT ;
    USE SIGNAL ;
    PORT
      LAYER METAL2 ;
        RECT 171.78 31.5 173.6 32.25 ;
    END
  END Vin<15>
  PIN OUT<0>
    DIRECTION INOUT ;
    USE SIGNAL ;
    PORT
      LAYER METAL2 ;
        RECT 8.41 0.0 9.81 0.85 ;
    END
  END OUT<0>
  PIN VINJ
    DIRECTION INOUT ;
    USE SIGNAL ;
    PORT
      LAYER METAL2 ;
        RECT 0.0 18.01 1.4 19.6 ;
    END
  END VINJ
  PIN Vin<0>
    DIRECTION INOUT ;
    USE SIGNAL ;
    PORT
      LAYER METAL2 ;
        RECT 7.7 31.5 9.26 32.25 ;
    END
  END Vin<0>
  PIN OUT<1>
    DIRECTION INOUT ;
    USE SIGNAL ;
    PORT
      LAYER METAL2 ;
        RECT 15.41 0.0 16.81 0.85 ;
    END
  END OUT<1>
  PIN DVDD
    DIRECTION INOUT ;
    USE SIGNAL ;
    PORT
      LAYER METAL2 ;
        RECT 0.0 28.0 1.4 29.59 ;
    END
  END DVDD
  PIN Vin<2>
    DIRECTION INOUT ;
    USE SIGNAL ;
    PORT
      LAYER METAL2 ;
        RECT 30.1 31.5 31.52 32.25 ;
    END
  END Vin<2>
  PIN Vin<13>
    DIRECTION INOUT ;
    USE SIGNAL ;
    PORT
      LAYER METAL2 ;
        RECT 149.52 31.5 151.2 32.25 ;
    END
  END Vin<13>
  PIN Vin<11>
    DIRECTION INOUT ;
    USE SIGNAL ;
    PORT
      LAYER METAL2 ;
        RECT 127.26 31.5 128.8 32.25 ;
    END
  END Vin<11>
  PIN Vin<9>
    DIRECTION INOUT ;
    USE SIGNAL ;
    PORT
      LAYER METAL2 ;
        RECT 105.0 31.5 106.4 32.25 ;
    END
  END Vin<9>
  PIN Vin<5>
    DIRECTION INOUT ;
    USE SIGNAL ;
    PORT
      LAYER METAL2 ;
        RECT 60.48 31.5 62.3 32.25 ;
    END
  END Vin<5>
  PIN Vin<8>
    DIRECTION INOUT ;
    USE SIGNAL ;
    PORT
      LAYER METAL2 ;
        RECT 96.6 31.5 98.3 32.25 ;
    END
  END Vin<8>
  PIN Vin<10>
    DIRECTION INOUT ;
    USE SIGNAL ;
    PORT
      LAYER METAL2 ;
        RECT 119.0 31.5 120.56 32.25 ;
    END
  END Vin<10>
  PIN Vin<6>
    DIRECTION INOUT ;
    USE SIGNAL ;
    PORT
      LAYER METAL2 ;
        RECT 74.2 31.5 76.04 32.25 ;
    END
  END Vin<6>
  PIN Vin<4>
    DIRECTION INOUT ;
    USE SIGNAL ;
    PORT
      LAYER METAL2 ;
        RECT 52.5 31.5 53.9 32.25 ;
    END
  END Vin<4>
  PIN Vin<14>
    DIRECTION INOUT ;
    USE SIGNAL ;
    PORT
      LAYER METAL2 ;
        RECT 163.1 31.5 165.08 32.25 ;
    END
  END Vin<14>
  PIN GND
    DIRECTION INOUT ;
    USE SIGNAL ;
    PORT
      LAYER METAL1 ;
        RECT 0.0 23.81 1.4 25.2 ;
    END
  END GND
END TSMC350nm_LVLShift_x16

MACRO TSMC350nm_DigBuffer_x2
  PIN GND
    DIRECTION INOUT ;
    USE SIGNAL ;
    PORT
      LAYER METAL2 ;
        RECT 9.1 0.0 10.5 1.2 ;
    END
  END GND
  PIN VINJ
    DIRECTION INOUT ;
    USE SIGNAL ;
    PORT
      LAYER METAL2 ;
        RECT 36.4 0.0 37.8 1.03 ;
    END
  END VINJ
  PIN Out<1>
    DIRECTION INOUT ;
    USE SIGNAL ;
    PORT
      LAYER METAL2 ;
        RECT 28.7 0.0 30.1 1.2 ;
    END
  END Out<1>
  PIN Out<0>
    DIRECTION INOUT ;
    USE SIGNAL ;
    PORT
      LAYER METAL2 ;
        RECT 17.5 0.0 18.9 1.2 ;
    END
  END Out<0>
  PIN In<1>
    DIRECTION INOUT ;
    USE SIGNAL ;
    PORT
      LAYER METAL1 ;
        RECT 36.4 10.96 37.8 11.74 ;
    END
  END In<1>
  PIN In<0>
    DIRECTION INOUT ;
    USE SIGNAL ;
    PORT
      LAYER METAL1 ;
        RECT 9.8 10.96 11.2 11.74 ;
    END
  END In<0>
END TSMC350nm_DigBuffer_x2

MACRO TSMC350nm_VinjDecode2to4_vtile
  PIN Vinj
    DIRECTION INOUT ;
    USE SIGNAL ;
    PORT
      LAYER METAL1 ;
        RECT 7.78 11.04 9.06 11.45 ;
    END
  END Vinj
  PIN OUT<0>
    DIRECTION INOUT ;
    USE SIGNAL ;
    PORT
      LAYER METAL1 ;
        RECT 19.66 18.91 20.11 19.59 ;
    END
  END OUT<0>
  PIN OUT<1>
    DIRECTION INOUT ;
    USE SIGNAL ;
    PORT
      LAYER METAL1 ;
        RECT 19.66 13.41 20.12 14.1 ;
    END
  END OUT<1>
  PIN OUT<2>
    DIRECTION INOUT ;
    USE SIGNAL ;
    PORT
      LAYER METAL1 ;
        RECT 19.66 7.92 20.11 8.59 ;
    END
  END OUT<2>
  PIN OUT<3>
    DIRECTION INOUT ;
    USE SIGNAL ;
    PORT
      LAYER METAL1 ;
        RECT 19.66 2.41 20.11 3.09 ;
    END
  END OUT<3>
  PIN ENABLE
    DIRECTION INOUT ;
    USE SIGNAL ;
    PORT
      LAYER METAL1 ;
        RECT 0.01 3.48 0.71 4.21 ;
    END
  END ENABLE
  PIN GND
    DIRECTION INOUT ;
    USE SIGNAL ;
    PORT
      LAYER METAL1 ;
        RECT 19.52 5.0 20.12 5.99 ;
    END
  END GND
  PIN VINJ
    DIRECTION INOUT ;
    USE SIGNAL ;
    PORT
      LAYER METAL1 ;
        RECT 19.15 21.56 20.05 21.96 ;
    END
  END VINJ
  PIN IN<1>
    DIRECTION INOUT ;
    USE SIGNAL ;
    PORT
      LAYER METAL2 ;
        RECT 6.56 20.89 7.5 22.0 ;
    END
  END IN<1>
  PIN IN<0>
    DIRECTION INOUT ;
    USE SIGNAL ;
    PORT
      LAYER METAL2 ;
        RECT 3.9 20.96 4.5 22.0 ;
    END
  END IN<0>
END TSMC350nm_VinjDecode2to4_vtile

MACRO TSMC350nm_drainSelect_progrundrains
  PIN prog_drain<3>
    DIRECTION INOUT ;
    USE SIGNAL ;
    PORT
      LAYER METAL1 ;
        RECT 30.93 0.93 31.86 1.43 ;
    END
  END prog_drain<3>
  PIN prog_drain<2>
    DIRECTION INOUT ;
    USE SIGNAL ;
    PORT
      LAYER METAL1 ;
        RECT 30.97 9.62 31.86 10.12 ;
    END
  END prog_drain<2>
  PIN prog_drain<1>
    DIRECTION INOUT ;
    USE SIGNAL ;
    PORT
      LAYER METAL1 ;
        RECT 31.0 13.97 31.86 14.47 ;
    END
  END prog_drain<1>
  PIN run_drain<3>
    DIRECTION INOUT ;
    USE SIGNAL ;
    PORT
      LAYER METAL1 ;
        RECT 31.01 2.45 31.86 2.95 ;
    END
  END run_drain<3>
  PIN run_drain<2>
    DIRECTION INOUT ;
    USE SIGNAL ;
    PORT
      LAYER METAL1 ;
        RECT 30.94 5.31 31.86 5.81 ;
    END
  END run_drain<2>
  PIN prog_drain<0>
    DIRECTION INOUT ;
    USE SIGNAL ;
    PORT
      LAYER METAL1 ;
        RECT 31.12 20.75 31.86 21.25 ;
    END
  END prog_drain<0>
  PIN GND
    DIRECTION INOUT ;
    USE SIGNAL ;
    PORT
      LAYER METAL2 ;
        RECT 4.19 21.33 4.99 22.0 ;
    END
  END GND
  PIN VINJ
    DIRECTION INOUT ;
    USE SIGNAL ;
    PORT
      LAYER METAL1 ;
        RECT 1.4 21.5 2.8 22.0 ;
    END
  END VINJ
  PIN run_drain<0>
    DIRECTION INOUT ;
    USE SIGNAL ;
    PORT
      LAYER METAL1 ;
        RECT 31.01 19.56 31.86 20.06 ;
    END
  END run_drain<0>
  PIN run_drain<1>
    DIRECTION INOUT ;
    USE SIGNAL ;
    PORT
      LAYER METAL1 ;
        RECT 31.04 16.75 31.86 17.24 ;
    END
  END run_drain<1>
  PIN SELECT<3>
    DIRECTION INOUT ;
    USE SIGNAL ;
    PORT
      LAYER METAL1 ;
        RECT 0.0 2.54 0.67 2.97 ;
    END
  END SELECT<3>
  PIN SELET<2>
    DIRECTION INOUT ;
    USE SIGNAL ;
    PORT
      LAYER METAL1 ;
        RECT 0.0 8.03 0.67 8.46 ;
    END
  END SELET<2>
  PIN SELECT<1>
    DIRECTION INOUT ;
    USE SIGNAL ;
    PORT
      LAYER METAL1 ;
        RECT 0.0 13.54 0.67 13.97 ;
    END
  END SELECT<1>
  PIN SELECT<0>
    DIRECTION INOUT ;
    USE SIGNAL ;
    PORT
      LAYER METAL1 ;
        RECT 0.0 18.9 0.67 19.6 ;
    END
  END SELECT<0>
  PIN VINJ_b
    DIRECTION INOUT ;
    USE SIGNAL ;
    PORT
      LAYER METAL2 ;
        RECT 21.94 0.0 23.29 0.58 ;
    END
  END VINJ_b
  PIN GND_b
    DIRECTION INOUT ;
    USE SIGNAL ;
    PORT
      LAYER METAL2 ;
        RECT 17.16 0.0 18.16 0.58 ;
    END
  END GND_b
  PIN run_drainrail
    DIRECTION INOUT ;
    USE SIGNAL ;
    PORT
      LAYER METAL2 ;
        RECT 27.01 21.19 27.71 22.0 ;
    END
  END run_drainrail
  PIN prog_drainrail
    DIRECTION INOUT ;
    USE SIGNAL ;
    PORT
      LAYER METAL2 ;
        RECT 7.36 21.34 8.16 22.0 ;
    END
  END prog_drainrail
END TSMC350nm_drainSelect_progrundrains

MACRO TSMC350nm_4TGate_ST_draincutoff
  PIN In<0>
    DIRECTION INOUT ;
    USE SIGNAL ;
    PORT
      LAYER METAL1 ;
        RECT 9.96 17.5 10.6 18.45 ;
    END
  END In<0>
  PIN In<1>
    DIRECTION INOUT ;
    USE SIGNAL ;
    PORT
      LAYER METAL1 ;
        RECT 9.91 14.7 10.6 15.93 ;
    END
  END In<1>
  PIN In<2>
    DIRECTION INOUT ;
    USE SIGNAL ;
    PORT
      LAYER METAL1 ;
        RECT 10.01 6.9 10.6 7.8 ;
    END
  END In<2>
  PIN In<3>
    DIRECTION INOUT ;
    USE SIGNAL ;
    PORT
      LAYER METAL1 ;
        RECT 10.02 3.5 10.6 4.3 ;
    END
  END In<3>
  PIN A<0>
    DIRECTION INOUT ;
    USE SIGNAL ;
    PORT
      LAYER METAL1 ;
        RECT 0.0 19.56 1.4 20.06 ;
    END
  END A<0>
  PIN A<1>
    DIRECTION INOUT ;
    USE SIGNAL ;
    PORT
      LAYER METAL1 ;
        RECT 0.0 16.75 1.4 17.25 ;
    END
  END A<1>
  PIN A<2>
    DIRECTION INOUT ;
    USE SIGNAL ;
    PORT
      LAYER METAL1 ;
        RECT 0.0 5.3 1.4 5.8 ;
    END
  END A<2>
  PIN A<3>
    DIRECTION INOUT ;
    USE SIGNAL ;
    PORT
      LAYER METAL1 ;
        RECT 0.0 2.45 1.4 2.95 ;
    END
  END A<3>
  PIN P<0>
    DIRECTION INOUT ;
    USE SIGNAL ;
    PORT
      LAYER METAL1 ;
        RECT 0.0 20.75 1.4 21.25 ;
    END
  END P<0>
  PIN P<1>
    DIRECTION INOUT ;
    USE SIGNAL ;
    PORT
      LAYER METAL1 ;
        RECT 0.0 13.97 1.4 14.47 ;
    END
  END P<1>
  PIN P<2>
    DIRECTION INOUT ;
    USE SIGNAL ;
    PORT
      LAYER METAL1 ;
        RECT 0.0 9.62 1.4 10.12 ;
    END
  END P<2>
  PIN P<3>
    DIRECTION INOUT ;
    USE SIGNAL ;
    PORT
      LAYER METAL1 ;
        RECT 0.0 0.93 1.4 1.43 ;
    END
  END P<3>
  PIN PR<0>
    DIRECTION INOUT ;
    USE SIGNAL ;
    PORT
      LAYER METAL1 ;
        RECT 10.0 20.3 10.6 21.25 ;
    END
  END PR<0>
  PIN PR<1>
    DIRECTION INOUT ;
    USE SIGNAL ;
    PORT
      LAYER METAL1 ;
        RECT 10.13 11.9 10.6 12.8 ;
    END
  END PR<1>
  PIN PR<2>
    DIRECTION INOUT ;
    USE SIGNAL ;
    PORT
      LAYER METAL1 ;
        RECT 10.0 9.4 10.6 10.3 ;
    END
  END PR<2>
  PIN PR<3>
    DIRECTION INOUT ;
    USE SIGNAL ;
    PORT
      LAYER METAL1 ;
        RECT 10.0 0.7 10.6 1.6 ;
    END
  END PR<3>
  PIN VDD_b
    DIRECTION INOUT ;
    USE SIGNAL ;
    PORT
      LAYER METAL2 ;
        RECT 7.89 0.0 8.79 0.54 ;
    END
  END VDD_b
  PIN RUN
    DIRECTION INOUT ;
    USE SIGNAL ;
    PORT
      LAYER METAL2 ;
        RECT 5.9 21.13 6.5 22.0 ;
    END
  END RUN
  PIN VDD
    DIRECTION INOUT ;
    USE SIGNAL ;
    PORT
      LAYER METAL2 ;
        RECT 7.89 21.3 8.79 22.0 ;
    END
  END VDD
  PIN GND
    DIRECTION INOUT ;
    USE SIGNAL ;
    PORT
      LAYER METAL2 ;
        RECT 3.35 21.3 4.25 22.0 ;
    END
  END GND
  PIN GND_b
    DIRECTION INOUT ;
    USE SIGNAL ;
    PORT
      LAYER METAL2 ;
        RECT 3.35 0.0 4.25 0.73 ;
    END
  END GND_b
  PIN RUN_b
    DIRECTION INOUT ;
    USE SIGNAL ;
    PORT
      LAYER METAL2 ;
        RECT 5.9 0.0 6.5 0.71 ;
    END
  END RUN_b
END TSMC350nm_4TGate_ST_draincutoff

MACRO TSMC350nm_IndirectSwitches
  PIN GND_B<1>
    DIRECTION INOUT ;
    USE SIGNAL ;
    PORT
      LAYER METAL2 ;
        RECT 15.41 0.0 16.01 0.85 ;
    END
  END GND_B<1>
  PIN GND_B<0>
    DIRECTION INOUT ;
    USE SIGNAL ;
    PORT
      LAYER METAL2 ;
        RECT 11.2 0.0 11.8 0.85 ;
    END
  END GND_B<0>
  PIN GND
    DIRECTION INOUT ;
    USE SIGNAL ;
    PORT
      LAYER METAL2 ;
        RECT 11.2 3.21 11.8 3.6 ;
    END
  END GND
  PIN GND_T
    DIRECTION INOUT ;
    USE SIGNAL ;
    PORT
      LAYER METAL2 ;
        RECT 15.4 21.0 16.2 22.0 ;
    END
  END GND_T
  PIN VINJ_T
    DIRECTION INOUT ;
    USE SIGNAL ;
    PORT
      LAYER METAL2 ;
        RECT 6.3 21.04 7.32 22.0 ;
    END
  END VINJ_T
  PIN VDD<1>
    DIRECTION INOUT ;
    USE SIGNAL ;
    PORT
      LAYER METAL2 ;
        RECT 24.5 0.0 25.1 0.75 ;
    END
  END VDD<1>
  PIN VTUN
    DIRECTION INOUT ;
    USE SIGNAL ;
    PORT
      LAYER METAL2 ;
        RECT 13.3 0.0 13.9 0.82 ;
    END
  END VTUN
  PIN VINJ
    DIRECTION INOUT ;
    USE SIGNAL ;
    PORT
      LAYER METAL2 ;
        RECT 4.2 0.0 4.8 1.0 ;
    END
  END VINJ
  PIN VDD<0>
    DIRECTION INOUT ;
    USE SIGNAL ;
    PORT
      LAYER METAL2 ;
        RECT 2.1 0.0 2.7 1.09 ;
    END
  END VDD<0>
  PIN Vg<0>
    DIRECTION INOUT ;
    USE SIGNAL ;
    PORT
      LAYER METAL2 ;
        RECT 8.4 0.005 9.0 0.825 ;
    END
  END Vg<0>
  PIN CTRL_B<0>
    DIRECTION INOUT ;
    USE SIGNAL ;
    PORT
      LAYER METAL2 ;
        RECT 6.3 0.01 6.9 0.76 ;
    END
  END CTRL_B<0>
  PIN CTRL_B<1>
    DIRECTION INOUT ;
    USE SIGNAL ;
    PORT
      LAYER METAL2 ;
        RECT 20.3 0.01 20.9 0.75 ;
    END
  END CTRL_B<1>
  PIN Vg<1>
    DIRECTION INOUT ;
    USE SIGNAL ;
    PORT
      LAYER METAL2 ;
        RECT 18.2 0.0 18.8 0.76 ;
    END
  END Vg<1>
  PIN decode<0>
    DIRECTION INOUT ;
    USE SIGNAL ;
    PORT
      LAYER METAL2 ;
        RECT 3.46 21.16 4.8 22.0 ;
    END
  END decode<0>
  PIN RUN_IN<1>
    DIRECTION INOUT ;
    USE SIGNAL ;
    PORT
      LAYER METAL2 ;
        RECT 17.5 21.01 18.1 22.0 ;
    END
  END RUN_IN<1>
  PIN RUN_IN<0>
    DIRECTION INOUT ;
    USE SIGNAL ;
    PORT
      LAYER METAL2 ;
        RECT 10.5 20.9 11.1 22.0 ;
    END
  END RUN_IN<0>
  PIN VPWR<1>
    DIRECTION INOUT ;
    USE SIGNAL ;
    PORT
      LAYER METAL2 ;
        RECT 21.7 21.08 22.3 22.0 ;
    END
  END VPWR<1>
  PIN decode<1>
    DIRECTION INOUT ;
    USE SIGNAL ;
    PORT
      LAYER METAL2 ;
        RECT 23.8 21.09 25.0 22.0 ;
    END
  END decode<1>
  PIN VPWR<0>
    DIRECTION INOUT ;
    USE SIGNAL ;
    PORT
      LAYER METAL2 ;
        RECT 1.71 21.21 2.43 22.0 ;
    END
  END VPWR<0>
  PIN VTUN_T
    DIRECTION INOUT ;
    USE SIGNAL ;
    PORT
      LAYER METAL2 ;
        RECT 12.6 21.12 13.7 22.0 ;
    END
  END VTUN_T
  PIN vtun_r
    DIRECTION INOUT ;
    USE SIGNAL ;
    PORT
      LAYER METAL1 ;
        RECT 26.17 0.9 27.46 2.17 ;
    END
  END vtun_r
  PIN vgsel_r
    DIRECTION INOUT ;
    USE SIGNAL ;
    PORT
      LAYER METAL1 ;
        RECT 26.52 3.15 27.46 4.45 ;
    END
  END vgsel_r
  PIN prog_r
    DIRECTION INOUT ;
    USE SIGNAL ;
    PORT
      LAYER METAL1 ;
        RECT 26.59 9.15 27.46 10.55 ;
    END
  END prog_r
  PIN run_r
    DIRECTION INOUT ;
    USE SIGNAL ;
    PORT
      LAYER METAL1 ;
        RECT 26.28 6.05 27.46 7.29 ;
    END
  END run_r
  PIN RUN
    DIRECTION INOUT ;
    USE SIGNAL ;
    PORT
      LAYER METAL1 ;
        RECT 0.0 6.05 0.91 7.29 ;
    END
  END RUN
  PIN PROG
    DIRECTION INOUT ;
    USE SIGNAL ;
    PORT
      LAYER METAL1 ;
        RECT 0.0 9.15 0.87 10.55 ;
    END
  END PROG
  PIN Vgsel
    DIRECTION INOUT ;
    USE SIGNAL ;
    PORT
      LAYER METAL1 ;
        RECT 0.0 3.72 0.91 4.45 ;
    END
  END Vgsel
  PIN vtun_l
    DIRECTION INOUT ;
    USE SIGNAL ;
    PORT
      LAYER METAL1 ;
        RECT 0.0 0.9 1.31 1.88 ;
    END
  END vtun_l
END TSMC350nm_IndirectSwitches

MACRO TSMC350nm_CS_RingOsc
  PIN Vsel
    DIRECTION INOUT ;
    USE SIGNAL ;
    PORT
      LAYER METAL2 ;
        RECT 7.8 21.4 8.4 22.0 ;
    END
  END Vsel
  PIN AVDD
    DIRECTION INOUT ;
    USE SIGNAL ;
    PORT
      LAYER METAL2 ;
        RECT 3.6 21.4 4.2 22.0 ;
    END
  END AVDD
  PIN VINJ
    DIRECTION INOUT ;
    USE SIGNAL ;
    PORT
      LAYER METAL2 ;
        RECT 5.7 21.4 6.3 22.0 ;
    END
  END VINJ
  PIN Vg
    DIRECTION INOUT ;
    USE SIGNAL ;
    PORT
      LAYER METAL2 ;
        RECT 9.9 21.4 10.5 22.0 ;
    END
  END Vg
  PIN GND
    DIRECTION INOUT ;
    USE SIGNAL ;
    PORT
      LAYER METAL2 ;
        RECT 12.7 21.4 13.3 22.0 ;
    END
  END GND
  PIN VTUN
    DIRECTION INOUT ;
    USE SIGNAL ;
    PORT
      LAYER METAL2 ;
        RECT 14.8 21.5 15.4 22.0 ;
    END
  END VTUN
  PIN OUT
    DIRECTION INOUT ;
    USE SIGNAL ;
    PORT
      LAYER METAL1 ;
        RECT 51.58 15.41 52.98 16.81 ;
    END
  END OUT
  PIN Vd_P
    DIRECTION INOUT ;
    USE SIGNAL ;
    PORT
      LAYER METAL1 ;
        RECT 0.0 5.61 1.4 7.01 ;
    END
  END Vd_P
END TSMC350nm_CS_RingOsc

MACRO TSMC350nm_RingOsc_DiffGen
  PIN SelCLK
    DIRECTION INOUT ;
    USE SIGNAL ;
    PORT
      LAYER METAL1 ;
        RECT 0.0 9.12 0.95 10.52 ;
    END
  END SelCLK
  PIN CLKN
    DIRECTION INOUT ;
    USE SIGNAL ;
    PORT
      LAYER METAL1 ;
        RECT 35.4 1.15 36.8 2.55 ;
    END
  END CLKN
  PIN CLKP
    DIRECTION INOUT ;
    USE SIGNAL ;
    PORT
      LAYER METAL1 ;
        RECT 35.4 18.71 36.8 20.11 ;
    END
  END CLKP
  PIN CLK<0>
    DIRECTION INOUT ;
    USE SIGNAL ;
    PORT
      LAYER METAL1 ;
        RECT 0.0 1.15 1.4 2.55 ;
    END
  END CLK<0>
  PIN CLK<1>
    DIRECTION INOUT ;
    USE SIGNAL ;
    PORT
      LAYER METAL1 ;
        RECT 0.0 18.71 1.4 20.11 ;
    END
  END CLK<1>
  PIN GND
    DIRECTION INOUT ;
    USE SIGNAL ;
    PORT
      LAYER METAL2 ;
        RECT 13.69 0.0 15.09 1.4 ;
    END
  END GND
  PIN VDD
    DIRECTION INOUT ;
    USE SIGNAL ;
    PORT
      LAYER METAL2 ;
        RECT 13.69 20.6 15.09 22.0 ;
    END
  END VDD
END TSMC350nm_RingOsc_DiffGen

MACRO Delaylines_Flip
  PIN IN<1>
    DIRECTION INOUT ;
    USE SIGNAL ;
    PORT
      LAYER METAL1 ;
        RECT 0.0 11.85 0.9 12.74 ;
    END
  END IN<1>
  PIN IN<0>
    DIRECTION INOUT ;
    USE SIGNAL ;
    PORT
      LAYER METAL1 ;
        RECT 0.0 10.13 0.87 11.1 ;
    END
  END IN<0>
  PIN VINJ
    DIRECTION INOUT ;
    USE SIGNAL ;
    PORT
      LAYER METAL1 ;
        RECT 0.0 1.99 0.5 2.49 ;
    END
  END VINJ
  PIN GND
    DIRECTION INOUT ;
    USE SIGNAL ;
    PORT
      LAYER METAL3 ;
        RECT 7.58 1223.201 8.98 1226.001 ;
    END
  END GND
  PIN GND_b<1>
    DIRECTION INOUT ;
    USE SIGNAL ;
    PORT
      LAYER METAL2 ;
        RECT 40.32 0.0 40.92 1.79 ;
    END
  END GND_b<1>
  PIN VINJ_b<1>
    DIRECTION INOUT ;
    USE SIGNAL ;
    PORT
      LAYER METAL2 ;
        RECT 22.1 0.0 22.7 1.44 ;
    END
  END VINJ_b<1>
  PIN GND_b<0>
    DIRECTION INOUT ;
    USE SIGNAL ;
    PORT
      LAYER METAL2 ;
        RECT 18.85 0.0 19.45 1.41 ;
    END
  END GND_b<0>
  PIN VINJ_b<0>
    DIRECTION INOUT ;
    USE SIGNAL ;
    PORT
      LAYER METAL2 ;
        RECT 1.07 0.0 1.67 1.25 ;
    END
  END VINJ_b<0>
  PIN VINJV
    DIRECTION INOUT ;
    USE SIGNAL ;
    PORT
      LAYER METAL2 ;
        RECT 23.7 21.26 24.31 22.0 ;
    END
  END VINJV
  PIN GNDV
    DIRECTION INOUT ;
    USE SIGNAL ;
    PORT
      LAYER METAL2 ;
        RECT 25.84 21.28 26.44 22.0 ;
    END
  END GNDV
  PIN RUN_OUT<3>
    DIRECTION INOUT ;
    USE SIGNAL ;
    PORT
      LAYER METAL2 ;
        RECT 34.39 0.0 35.19 0.86 ;
    END
  END RUN_OUT<3>
  PIN RUN_OUT<2>
    DIRECTION INOUT ;
    USE SIGNAL ;
    PORT
      LAYER METAL2 ;
        RECT 28.77 0.0 29.57 0.86 ;
    END
  END RUN_OUT<2>
  PIN RUN_OUT<1>
    DIRECTION INOUT ;
    USE SIGNAL ;
    PORT
      LAYER METAL2 ;
        RECT 13.5 0.0 14.1 0.86 ;
    END
  END RUN_OUT<1>
  PIN RUN_OUT<0>
    DIRECTION INOUT ;
    USE SIGNAL ;
    PORT
      LAYER METAL2 ;
        RECT 7.34 0.0 8.14 0.86 ;
    END
  END RUN_OUT<0>
  PIN ENABLE
    DIRECTION INOUT ;
    USE SIGNAL ;
    PORT
      LAYER METAL2 ;
        RECT 6.29 21.66 6.89 22.0 ;
    END
  END ENABLE
  PIN OUT<2>
    DIRECTION INOUT ;
    USE SIGNAL ;
    PORT
      LAYER METAL2 ;
        RECT 25.28 0.0 25.87 0.87 ;
    END
  END OUT<2>
  PIN OUT<3>
    DIRECTION INOUT ;
    USE SIGNAL ;
    PORT
      LAYER METAL2 ;
        RECT 37.14 0.0 37.73 0.83 ;
    END
  END OUT<3>
  PIN OUT<0>
    DIRECTION INOUT ;
    USE SIGNAL ;
    PORT
      LAYER METAL2 ;
        RECT 4.27 0.0 4.87 0.86 ;
    END
  END OUT<0>
  PIN OUT<1>
    DIRECTION INOUT ;
    USE SIGNAL ;
    PORT
      LAYER METAL2 ;
        RECT 16.14 0.0 16.72 0.85 ;
    END
  END OUT<1>
  PIN VGRUN<0>
    DIRECTION INOUT ;
    USE SIGNAL ;
    PORT
      LAYER METAL2 ;
        RECT 9.1 21.59 9.7 22.0 ;
    END
  END VGRUN<0>
  PIN VGRUN<1>
    DIRECTION INOUT ;
    USE SIGNAL ;
    PORT
      LAYER METAL2 ;
        RECT 11.2 21.6 11.8 22.0 ;
    END
  END VGRUN<1>
  PIN VGRUN<2>
    DIRECTION INOUT ;
    USE SIGNAL ;
    PORT
      LAYER METAL2 ;
        RECT 28.7 21.71 29.3 22.0 ;
    END
  END VGRUN<2>
  PIN VGRUN<3>
    DIRECTION INOUT ;
    USE SIGNAL ;
    PORT
      LAYER METAL2 ;
        RECT 33.6 21.54 34.2 22.0 ;
    END
  END VGRUN<3>
  PIN w_DrainEnable_Del
    DIRECTION INOUT ;
    USE SIGNAL ;
    PORT
      LAYER METAL3 ;
        RECT 1672.44 510.601 1675.24 512.001 ;
    END
  END w_DrainEnable_Del
  PIN w_Input<39>
    DIRECTION INOUT ;
    USE SIGNAL ;
    PORT
      LAYER METAL3 ;
        RECT 1672.44 524.601 1675.24 526.001 ;
    END
  END w_Input<39>
  PIN w_Input<38>
    DIRECTION INOUT ;
    USE SIGNAL ;
    PORT
      LAYER METAL3 ;
        RECT 1672.44 538.601 1675.24 540.001 ;
    END
  END w_Input<38>
  PIN w_Input<37>
    DIRECTION INOUT ;
    USE SIGNAL ;
    PORT
      LAYER METAL3 ;
        RECT 1672.44 552.601 1675.24 554.001 ;
    END
  END w_Input<37>
  PIN w_Input<36>
    DIRECTION INOUT ;
    USE SIGNAL ;
    PORT
      LAYER METAL3 ;
        RECT 1672.44 566.601 1675.24 568.001 ;
    END
  END w_Input<36>
  PIN w_Input<35>
    DIRECTION INOUT ;
    USE SIGNAL ;
    PORT
      LAYER METAL3 ;
        RECT 1672.44 580.601 1675.24 582.001 ;
    END
  END w_Input<35>
  PIN w_Input<34>
    DIRECTION INOUT ;
    USE SIGNAL ;
    PORT
      LAYER METAL3 ;
        RECT 1672.44 594.601 1675.24 596.001 ;
    END
  END w_Input<34>
  PIN w_Input<33>
    DIRECTION INOUT ;
    USE SIGNAL ;
    PORT
      LAYER METAL3 ;
        RECT 1672.44 608.601 1675.24 610.001 ;
    END
  END w_Input<33>
  PIN w_Input<32>
    DIRECTION INOUT ;
    USE SIGNAL ;
    PORT
      LAYER METAL3 ;
        RECT 1672.44 622.601 1675.24 624.001 ;
    END
  END w_Input<32>
  PIN w_Input<31>
    DIRECTION INOUT ;
    USE SIGNAL ;
    PORT
      LAYER METAL3 ;
        RECT 1672.44 636.601 1675.24 638.001 ;
    END
  END w_Input<31>
  PIN w_Input<30>
    DIRECTION INOUT ;
    USE SIGNAL ;
    PORT
      LAYER METAL3 ;
        RECT 1672.44 650.601 1675.24 652.001 ;
    END
  END w_Input<30>
  PIN w_Input<29>
    DIRECTION INOUT ;
    USE SIGNAL ;
    PORT
      LAYER METAL3 ;
        RECT 1672.44 664.601 1675.24 666.001 ;
    END
  END w_Input<29>
  PIN w_Input<28>
    DIRECTION INOUT ;
    USE SIGNAL ;
    PORT
      LAYER METAL3 ;
        RECT 1672.44 678.601 1675.24 680.001 ;
    END
  END w_Input<28>
  PIN w_Input<27>
    DIRECTION INOUT ;
    USE SIGNAL ;
    PORT
      LAYER METAL3 ;
        RECT 1672.44 692.601 1675.24 694.001 ;
    END
  END w_Input<27>
  PIN w_Input<26>
    DIRECTION INOUT ;
    USE SIGNAL ;
    PORT
      LAYER METAL3 ;
        RECT 1672.44 706.601 1675.24 708.001 ;
    END
  END w_Input<26>
  PIN w_Input<25>
    DIRECTION INOUT ;
    USE SIGNAL ;
    PORT
      LAYER METAL3 ;
        RECT 1672.44 720.601 1675.24 722.001 ;
    END
  END w_Input<25>
  PIN w_Input<24>
    DIRECTION INOUT ;
    USE SIGNAL ;
    PORT
      LAYER METAL3 ;
        RECT 1672.44 734.601 1675.24 736.001 ;
    END
  END w_Input<24>
  PIN w_Input<23>
    DIRECTION INOUT ;
    USE SIGNAL ;
    PORT
      LAYER METAL3 ;
        RECT 1672.44 748.601 1675.24 750.001 ;
    END
  END w_Input<23>
  PIN w_Input<22>
    DIRECTION INOUT ;
    USE SIGNAL ;
    PORT
      LAYER METAL3 ;
        RECT 1672.44 762.601 1675.24 764.001 ;
    END
  END w_Input<22>
  PIN w_Input<21>
    DIRECTION INOUT ;
    USE SIGNAL ;
    PORT
      LAYER METAL3 ;
        RECT 1672.44 776.601 1675.24 778.001 ;
    END
  END w_Input<21>
  PIN w_Input<20>
    DIRECTION INOUT ;
    USE SIGNAL ;
    PORT
      LAYER METAL3 ;
        RECT 1672.44 790.601 1675.24 792.001 ;
    END
  END w_Input<20>
  PIN w_Input<19>
    DIRECTION INOUT ;
    USE SIGNAL ;
    PORT
      LAYER METAL3 ;
        RECT 1672.44 804.601 1675.24 806.001 ;
    END
  END w_Input<19>
  PIN w_Input<18>
    DIRECTION INOUT ;
    USE SIGNAL ;
    PORT
      LAYER METAL3 ;
        RECT 1672.44 818.601 1675.24 820.001 ;
    END
  END w_Input<18>
  PIN w_Input<17>
    DIRECTION INOUT ;
    USE SIGNAL ;
    PORT
      LAYER METAL3 ;
        RECT 1672.44 832.601 1675.24 834.001 ;
    END
  END w_Input<17>
  PIN w_Input<16>
    DIRECTION INOUT ;
    USE SIGNAL ;
    PORT
      LAYER METAL3 ;
        RECT 1672.44 846.601 1675.24 848.001 ;
    END
  END w_Input<16>
  PIN w_Input<15>
    DIRECTION INOUT ;
    USE SIGNAL ;
    PORT
      LAYER METAL3 ;
        RECT 1672.44 860.601 1675.24 862.001 ;
    END
  END w_Input<15>
  PIN w_Input<14>
    DIRECTION INOUT ;
    USE SIGNAL ;
    PORT
      LAYER METAL3 ;
        RECT 1672.44 874.601 1675.24 876.001 ;
    END
  END w_Input<14>
  PIN w_Input<13>
    DIRECTION INOUT ;
    USE SIGNAL ;
    PORT
      LAYER METAL3 ;
        RECT 1672.44 888.601 1675.24 890.001 ;
    END
  END w_Input<13>
  PIN w_Input<12>
    DIRECTION INOUT ;
    USE SIGNAL ;
    PORT
      LAYER METAL3 ;
        RECT 1672.44 902.601 1675.24 904.001 ;
    END
  END w_Input<12>
  PIN w_Input<11>
    DIRECTION INOUT ;
    USE SIGNAL ;
    PORT
      LAYER METAL3 ;
        RECT 1672.44 916.601 1675.24 918.001 ;
    END
  END w_Input<11>
  PIN w_Input<10>
    DIRECTION INOUT ;
    USE SIGNAL ;
    PORT
      LAYER METAL3 ;
        RECT 1672.44 930.601 1675.24 932.001 ;
    END
  END w_Input<10>
  PIN w_Input<9>
    DIRECTION INOUT ;
    USE SIGNAL ;
    PORT
      LAYER METAL3 ;
        RECT 1672.44 944.601 1675.24 946.001 ;
    END
  END w_Input<9>
  PIN w_Input<8>
    DIRECTION INOUT ;
    USE SIGNAL ;
    PORT
      LAYER METAL3 ;
        RECT 1672.44 958.601 1675.24 960.001 ;
    END
  END w_Input<8>
  PIN w_Input<7>
    DIRECTION INOUT ;
    USE SIGNAL ;
    PORT
      LAYER METAL3 ;
        RECT 1672.44 972.601 1675.24 974.001 ;
    END
  END w_Input<7>
  PIN w_Input<6>
    DIRECTION INOUT ;
    USE SIGNAL ;
    PORT
      LAYER METAL3 ;
        RECT 1672.44 986.601 1675.24 988.001 ;
    END
  END w_Input<6>
  PIN w_Input<5>
    DIRECTION INOUT ;
    USE SIGNAL ;
    PORT
      LAYER METAL3 ;
        RECT 1672.44 1000.601 1675.24 1002.001 ;
    END
  END w_Input<5>
  PIN w_Input<4>
    DIRECTION INOUT ;
    USE SIGNAL ;
    PORT
      LAYER METAL3 ;
        RECT 1672.44 1014.601 1675.24 1016.001 ;
    END
  END w_Input<4>
  PIN w_Input<3>
    DIRECTION INOUT ;
    USE SIGNAL ;
    PORT
      LAYER METAL3 ;
        RECT 1672.44 1028.601 1675.24 1030.001 ;
    END
  END w_Input<3>
  PIN w_Input<2>
    DIRECTION INOUT ;
    USE SIGNAL ;
    PORT
      LAYER METAL3 ;
        RECT 1672.44 1042.601 1675.24 1044.001 ;
    END
  END w_Input<2>
  PIN w_Input<1>
    DIRECTION INOUT ;
    USE SIGNAL ;
    PORT
      LAYER METAL3 ;
        RECT 1672.44 1056.601 1675.24 1058.001 ;
    END
  END w_Input<1>
  PIN w_Input<0>
    DIRECTION INOUT ;
    USE SIGNAL ;
    PORT
      LAYER METAL3 ;
        RECT 1672.44 1070.601 1675.24 1072.001 ;
    END
  END w_Input<0>
  PIN w_Drainline_Run
    DIRECTION INOUT ;
    USE SIGNAL ;
    PORT
      LAYER METAL3 ;
        RECT 1672.44 1084.601 1675.24 1086.001 ;
    END
  END w_Drainline_Run
  PIN w_Drainline_Prog
    DIRECTION INOUT ;
    USE SIGNAL ;
    PORT
      LAYER METAL3 ;
        RECT 1672.44 1098.601 1675.24 1100.001 ;
    END
  END w_Drainline_Prog
  PIN w_DrainB<7>
    DIRECTION INOUT ;
    USE SIGNAL ;
    PORT
      LAYER METAL3 ;
        RECT 1672.44 1112.601 1675.24 1114.001 ;
    END
  END w_DrainB<7>
  PIN w_DrainB<6>
    DIRECTION INOUT ;
    USE SIGNAL ;
    PORT
      LAYER METAL3 ;
        RECT 1672.44 1126.601 1675.24 1128.001 ;
    END
  END w_DrainB<6>
  PIN w_DrainB<5>
    DIRECTION INOUT ;
    USE SIGNAL ;
    PORT
      LAYER METAL3 ;
        RECT 1672.44 1140.601 1675.24 1142.001 ;
    END
  END w_DrainB<5>
  PIN w_DrainB<4>
    DIRECTION INOUT ;
    USE SIGNAL ;
    PORT
      LAYER METAL3 ;
        RECT 1672.44 1154.601 1675.24 1156.001 ;
    END
  END w_DrainB<4>
  PIN w_DrainB<3>
    DIRECTION INOUT ;
    USE SIGNAL ;
    PORT
      LAYER METAL3 ;
        RECT 1672.44 1168.601 1675.24 1170.001 ;
    END
  END w_DrainB<3>
  PIN w_DrainB<2>
    DIRECTION INOUT ;
    USE SIGNAL ;
    PORT
      LAYER METAL3 ;
        RECT 1672.44 1182.601 1675.24 1184.001 ;
    END
  END w_DrainB<2>
  PIN w_DrainB<1>
    DIRECTION INOUT ;
    USE SIGNAL ;
    PORT
      LAYER METAL3 ;
        RECT 1672.44 1196.601 1675.24 1198.001 ;
    END
  END w_DrainB<1>
  PIN w_DrainB<0>
    DIRECTION INOUT ;
    USE SIGNAL ;
    PORT
      LAYER METAL3 ;
        RECT 1672.44 1210.601 1675.24 1212.001 ;
    END
  END w_DrainB<0>
  PIN s_RSTBar
    DIRECTION INOUT ;
    USE SIGNAL ;
    PORT
      LAYER METAL3 ;
        RECT 1659.42 0.0 1660.82 2.8 ;
    END
  END s_RSTBar
  PIN s_CLK
    DIRECTION INOUT ;
    USE SIGNAL ;
    PORT
      LAYER METAL3 ;
        RECT 1663.2 0.0 1664.6 2.8 ;
    END
  END s_CLK
  PIN s_Din
    DIRECTION INOUT ;
    USE SIGNAL ;
    PORT
      LAYER METAL3 ;
        RECT 1666.98 0.0 1668.38 2.8 ;
    END
  END s_Din
  PIN s_WTA_out
    DIRECTION INOUT ;
    USE SIGNAL ;
    PORT
      LAYER METAL3 ;
        RECT 1670.76 0.0 1672.16 2.8 ;
    END
  END s_WTA_out
  PIN s_vinj
    DIRECTION INOUT ;
    USE SIGNAL ;
    PORT
      LAYER METAL3 ;
        RECT 11.36 0.0 12.76 2.8 ;
    END
  END s_vinj
  PIN s_gnd
    DIRECTION INOUT ;
    USE SIGNAL ;
    PORT
      LAYER METAL3 ;
        RECT 7.58 0.0 8.98 2.8 ;
    END
  END s_gnd
  PIN e_WTA_Vg<1>
    DIRECTION INOUT ;
    USE SIGNAL ;
    PORT
      LAYER METAL3 ;
        RECT 0.02 1168.601 2.82 1170.001 ;
    END
  END e_WTA_Vg<1>
  PIN e_WTA_Vg<0>
    DIRECTION INOUT ;
    USE SIGNAL ;
    PORT
      LAYER METAL3 ;
        RECT 0.02 1182.601 2.82 1184.001 ;
    END
  END e_WTA_Vg<0>
  PIN e_WTA_CTRL_B<1>
    DIRECTION INOUT ;
    USE SIGNAL ;
    PORT
      LAYER METAL3 ;
        RECT 0.02 1196.601 2.82 1198.001 ;
    END
  END e_WTA_CTRL_B<1>
  PIN e_WTA_CTRL_B<0>
    DIRECTION INOUT ;
    USE SIGNAL ;
    PORT
      LAYER METAL3 ;
        RECT 0.02 1210.601 2.82 1212.001 ;
    END
  END e_WTA_CTRL_B<0>
  PIN n_GateEnable_Del
    DIRECTION INOUT ;
    USE SIGNAL ;
    PORT
      LAYER METAL3 ;
        RECT 117.18 1223.201 118.58 1226.001 ;
    END
  END n_GateEnable_Del
  PIN n_OUTS<399>
    DIRECTION INOUT ;
    USE SIGNAL ;
    PORT
      LAYER METAL3 ;
        RECT 120.96 1223.201 122.36 1226.001 ;
    END
  END n_OUTS<399>
  PIN n_OUTS<398>
    DIRECTION INOUT ;
    USE SIGNAL ;
    PORT
      LAYER METAL3 ;
        RECT 124.74 1223.201 126.14 1226.001 ;
    END
  END n_OUTS<398>
  PIN n_OUTS<397>
    DIRECTION INOUT ;
    USE SIGNAL ;
    PORT
      LAYER METAL3 ;
        RECT 128.52 1223.201 129.92 1226.001 ;
    END
  END n_OUTS<397>
  PIN n_OUTS<396>
    DIRECTION INOUT ;
    USE SIGNAL ;
    PORT
      LAYER METAL3 ;
        RECT 132.3 1223.201 133.7 1226.001 ;
    END
  END n_OUTS<396>
  PIN n_OUTS<395>
    DIRECTION INOUT ;
    USE SIGNAL ;
    PORT
      LAYER METAL3 ;
        RECT 136.08 1223.201 137.48 1226.001 ;
    END
  END n_OUTS<395>
  PIN n_OUTS<394>
    DIRECTION INOUT ;
    USE SIGNAL ;
    PORT
      LAYER METAL3 ;
        RECT 139.86 1223.201 141.26 1226.001 ;
    END
  END n_OUTS<394>
  PIN n_OUTS<393>
    DIRECTION INOUT ;
    USE SIGNAL ;
    PORT
      LAYER METAL3 ;
        RECT 143.64 1223.201 145.04 1226.001 ;
    END
  END n_OUTS<393>
  PIN n_OUTS<392>
    DIRECTION INOUT ;
    USE SIGNAL ;
    PORT
      LAYER METAL3 ;
        RECT 147.42 1223.201 148.82 1226.001 ;
    END
  END n_OUTS<392>
  PIN n_OUTS<391>
    DIRECTION INOUT ;
    USE SIGNAL ;
    PORT
      LAYER METAL3 ;
        RECT 151.2 1223.201 152.6 1226.001 ;
    END
  END n_OUTS<391>
  PIN n_OUTS<390>
    DIRECTION INOUT ;
    USE SIGNAL ;
    PORT
      LAYER METAL3 ;
        RECT 154.98 1223.201 156.38 1226.001 ;
    END
  END n_OUTS<390>
  PIN n_OUTS<389>
    DIRECTION INOUT ;
    USE SIGNAL ;
    PORT
      LAYER METAL3 ;
        RECT 158.76 1223.201 160.16 1226.001 ;
    END
  END n_OUTS<389>
  PIN n_OUTS<388>
    DIRECTION INOUT ;
    USE SIGNAL ;
    PORT
      LAYER METAL3 ;
        RECT 162.54 1223.201 163.94 1226.001 ;
    END
  END n_OUTS<388>
  PIN n_OUTS<387>
    DIRECTION INOUT ;
    USE SIGNAL ;
    PORT
      LAYER METAL3 ;
        RECT 166.32 1223.201 167.72 1226.001 ;
    END
  END n_OUTS<387>
  PIN n_OUTS<386>
    DIRECTION INOUT ;
    USE SIGNAL ;
    PORT
      LAYER METAL3 ;
        RECT 170.1 1223.201 171.5 1226.001 ;
    END
  END n_OUTS<386>
  PIN n_OUTS<385>
    DIRECTION INOUT ;
    USE SIGNAL ;
    PORT
      LAYER METAL3 ;
        RECT 173.88 1223.201 175.28 1226.001 ;
    END
  END n_OUTS<385>
  PIN n_OUTS<384>
    DIRECTION INOUT ;
    USE SIGNAL ;
    PORT
      LAYER METAL3 ;
        RECT 177.66 1223.201 179.06 1226.001 ;
    END
  END n_OUTS<384>
  PIN n_OUTS<383>
    DIRECTION INOUT ;
    USE SIGNAL ;
    PORT
      LAYER METAL3 ;
        RECT 181.44 1223.201 182.84 1226.001 ;
    END
  END n_OUTS<383>
  PIN n_OUTS<382>
    DIRECTION INOUT ;
    USE SIGNAL ;
    PORT
      LAYER METAL3 ;
        RECT 185.22 1223.201 186.62 1226.001 ;
    END
  END n_OUTS<382>
  PIN n_OUTS<381>
    DIRECTION INOUT ;
    USE SIGNAL ;
    PORT
      LAYER METAL3 ;
        RECT 189.0 1223.201 190.4 1226.001 ;
    END
  END n_OUTS<381>
  PIN n_OUTS<380>
    DIRECTION INOUT ;
    USE SIGNAL ;
    PORT
      LAYER METAL3 ;
        RECT 192.78 1223.201 194.18 1226.001 ;
    END
  END n_OUTS<380>
  PIN n_OUTS<379>
    DIRECTION INOUT ;
    USE SIGNAL ;
    PORT
      LAYER METAL3 ;
        RECT 196.56 1223.201 197.96 1226.001 ;
    END
  END n_OUTS<379>
  PIN n_OUTS<378>
    DIRECTION INOUT ;
    USE SIGNAL ;
    PORT
      LAYER METAL3 ;
        RECT 200.34 1223.201 201.74 1226.001 ;
    END
  END n_OUTS<378>
  PIN n_OUTS<377>
    DIRECTION INOUT ;
    USE SIGNAL ;
    PORT
      LAYER METAL3 ;
        RECT 204.12 1223.201 205.52 1226.001 ;
    END
  END n_OUTS<377>
  PIN n_OUTS<376>
    DIRECTION INOUT ;
    USE SIGNAL ;
    PORT
      LAYER METAL3 ;
        RECT 207.9 1223.201 209.3 1226.001 ;
    END
  END n_OUTS<376>
  PIN n_OUTS<375>
    DIRECTION INOUT ;
    USE SIGNAL ;
    PORT
      LAYER METAL3 ;
        RECT 211.68 1223.201 213.08 1226.001 ;
    END
  END n_OUTS<375>
  PIN n_OUTS<374>
    DIRECTION INOUT ;
    USE SIGNAL ;
    PORT
      LAYER METAL3 ;
        RECT 215.46 1223.201 216.86 1226.001 ;
    END
  END n_OUTS<374>
  PIN n_OUTS<373>
    DIRECTION INOUT ;
    USE SIGNAL ;
    PORT
      LAYER METAL3 ;
        RECT 219.24 1223.201 220.64 1226.001 ;
    END
  END n_OUTS<373>
  PIN n_OUTS<372>
    DIRECTION INOUT ;
    USE SIGNAL ;
    PORT
      LAYER METAL3 ;
        RECT 223.02 1223.201 224.42 1226.001 ;
    END
  END n_OUTS<372>
  PIN n_OUTS<371>
    DIRECTION INOUT ;
    USE SIGNAL ;
    PORT
      LAYER METAL3 ;
        RECT 226.8 1223.201 228.2 1226.001 ;
    END
  END n_OUTS<371>
  PIN n_OUTS<370>
    DIRECTION INOUT ;
    USE SIGNAL ;
    PORT
      LAYER METAL3 ;
        RECT 230.58 1223.201 231.98 1226.001 ;
    END
  END n_OUTS<370>
  PIN n_OUTS<369>
    DIRECTION INOUT ;
    USE SIGNAL ;
    PORT
      LAYER METAL3 ;
        RECT 234.36 1223.201 235.76 1226.001 ;
    END
  END n_OUTS<369>
  PIN n_OUTS<368>
    DIRECTION INOUT ;
    USE SIGNAL ;
    PORT
      LAYER METAL3 ;
        RECT 238.14 1223.201 239.54 1226.001 ;
    END
  END n_OUTS<368>
  PIN n_OUTS<367>
    DIRECTION INOUT ;
    USE SIGNAL ;
    PORT
      LAYER METAL3 ;
        RECT 241.92 1223.201 243.32 1226.001 ;
    END
  END n_OUTS<367>
  PIN n_OUTS<366>
    DIRECTION INOUT ;
    USE SIGNAL ;
    PORT
      LAYER METAL3 ;
        RECT 245.7 1223.201 247.1 1226.001 ;
    END
  END n_OUTS<366>
  PIN n_OUTS<365>
    DIRECTION INOUT ;
    USE SIGNAL ;
    PORT
      LAYER METAL3 ;
        RECT 249.48 1223.201 250.88 1226.001 ;
    END
  END n_OUTS<365>
  PIN n_OUTS<364>
    DIRECTION INOUT ;
    USE SIGNAL ;
    PORT
      LAYER METAL3 ;
        RECT 253.26 1223.201 254.66 1226.001 ;
    END
  END n_OUTS<364>
  PIN n_OUTS<363>
    DIRECTION INOUT ;
    USE SIGNAL ;
    PORT
      LAYER METAL3 ;
        RECT 257.04 1223.201 258.44 1226.001 ;
    END
  END n_OUTS<363>
  PIN n_OUTS<362>
    DIRECTION INOUT ;
    USE SIGNAL ;
    PORT
      LAYER METAL3 ;
        RECT 260.82 1223.201 262.22 1226.001 ;
    END
  END n_OUTS<362>
  PIN n_OUTS<361>
    DIRECTION INOUT ;
    USE SIGNAL ;
    PORT
      LAYER METAL3 ;
        RECT 264.6 1223.201 266.0 1226.001 ;
    END
  END n_OUTS<361>
  PIN n_OUTS<360>
    DIRECTION INOUT ;
    USE SIGNAL ;
    PORT
      LAYER METAL3 ;
        RECT 268.38 1223.201 269.78 1226.001 ;
    END
  END n_OUTS<360>
  PIN n_OUTS<359>
    DIRECTION INOUT ;
    USE SIGNAL ;
    PORT
      LAYER METAL3 ;
        RECT 272.16 1223.201 273.56 1226.001 ;
    END
  END n_OUTS<359>
  PIN n_OUTS<358>
    DIRECTION INOUT ;
    USE SIGNAL ;
    PORT
      LAYER METAL3 ;
        RECT 275.94 1223.201 277.34 1226.001 ;
    END
  END n_OUTS<358>
  PIN n_OUTS<357>
    DIRECTION INOUT ;
    USE SIGNAL ;
    PORT
      LAYER METAL3 ;
        RECT 279.72 1223.201 281.12 1226.001 ;
    END
  END n_OUTS<357>
  PIN n_OUTS<356>
    DIRECTION INOUT ;
    USE SIGNAL ;
    PORT
      LAYER METAL3 ;
        RECT 283.5 1223.201 284.9 1226.001 ;
    END
  END n_OUTS<356>
  PIN n_OUTS<355>
    DIRECTION INOUT ;
    USE SIGNAL ;
    PORT
      LAYER METAL3 ;
        RECT 287.28 1223.201 288.68 1226.001 ;
    END
  END n_OUTS<355>
  PIN n_OUTS<354>
    DIRECTION INOUT ;
    USE SIGNAL ;
    PORT
      LAYER METAL3 ;
        RECT 291.06 1223.201 292.46 1226.001 ;
    END
  END n_OUTS<354>
  PIN n_OUTS<353>
    DIRECTION INOUT ;
    USE SIGNAL ;
    PORT
      LAYER METAL3 ;
        RECT 294.84 1223.201 296.24 1226.001 ;
    END
  END n_OUTS<353>
  PIN n_OUTS<352>
    DIRECTION INOUT ;
    USE SIGNAL ;
    PORT
      LAYER METAL3 ;
        RECT 298.62 1223.201 300.02 1226.001 ;
    END
  END n_OUTS<352>
  PIN n_OUTS<351>
    DIRECTION INOUT ;
    USE SIGNAL ;
    PORT
      LAYER METAL3 ;
        RECT 302.4 1223.201 303.8 1226.001 ;
    END
  END n_OUTS<351>
  PIN n_OUTS<350>
    DIRECTION INOUT ;
    USE SIGNAL ;
    PORT
      LAYER METAL3 ;
        RECT 306.18 1223.201 307.58 1226.001 ;
    END
  END n_OUTS<350>
  PIN n_OUTS<349>
    DIRECTION INOUT ;
    USE SIGNAL ;
    PORT
      LAYER METAL3 ;
        RECT 309.96 1223.201 311.36 1226.001 ;
    END
  END n_OUTS<349>
  PIN n_OUTS<348>
    DIRECTION INOUT ;
    USE SIGNAL ;
    PORT
      LAYER METAL3 ;
        RECT 313.74 1223.201 315.14 1226.001 ;
    END
  END n_OUTS<348>
  PIN n_OUTS<347>
    DIRECTION INOUT ;
    USE SIGNAL ;
    PORT
      LAYER METAL3 ;
        RECT 317.52 1223.201 318.92 1226.001 ;
    END
  END n_OUTS<347>
  PIN n_OUTS<346>
    DIRECTION INOUT ;
    USE SIGNAL ;
    PORT
      LAYER METAL3 ;
        RECT 321.3 1223.201 322.7 1226.001 ;
    END
  END n_OUTS<346>
  PIN n_OUTS<345>
    DIRECTION INOUT ;
    USE SIGNAL ;
    PORT
      LAYER METAL3 ;
        RECT 325.08 1223.201 326.48 1226.001 ;
    END
  END n_OUTS<345>
  PIN n_OUTS<344>
    DIRECTION INOUT ;
    USE SIGNAL ;
    PORT
      LAYER METAL3 ;
        RECT 328.86 1223.201 330.26 1226.001 ;
    END
  END n_OUTS<344>
  PIN n_OUTS<343>
    DIRECTION INOUT ;
    USE SIGNAL ;
    PORT
      LAYER METAL3 ;
        RECT 332.64 1223.201 334.04 1226.001 ;
    END
  END n_OUTS<343>
  PIN n_OUTS<342>
    DIRECTION INOUT ;
    USE SIGNAL ;
    PORT
      LAYER METAL3 ;
        RECT 336.42 1223.201 337.82 1226.001 ;
    END
  END n_OUTS<342>
  PIN n_OUTS<341>
    DIRECTION INOUT ;
    USE SIGNAL ;
    PORT
      LAYER METAL3 ;
        RECT 340.2 1223.201 341.6 1226.001 ;
    END
  END n_OUTS<341>
  PIN n_OUTS<340>
    DIRECTION INOUT ;
    USE SIGNAL ;
    PORT
      LAYER METAL3 ;
        RECT 343.98 1223.201 345.38 1226.001 ;
    END
  END n_OUTS<340>
  PIN n_OUTS<339>
    DIRECTION INOUT ;
    USE SIGNAL ;
    PORT
      LAYER METAL3 ;
        RECT 347.76 1223.201 349.16 1226.001 ;
    END
  END n_OUTS<339>
  PIN n_OUTS<338>
    DIRECTION INOUT ;
    USE SIGNAL ;
    PORT
      LAYER METAL3 ;
        RECT 351.54 1223.201 352.94 1226.001 ;
    END
  END n_OUTS<338>
  PIN n_OUTS<337>
    DIRECTION INOUT ;
    USE SIGNAL ;
    PORT
      LAYER METAL3 ;
        RECT 355.32 1223.201 356.72 1226.001 ;
    END
  END n_OUTS<337>
  PIN n_OUTS<336>
    DIRECTION INOUT ;
    USE SIGNAL ;
    PORT
      LAYER METAL3 ;
        RECT 359.1 1223.201 360.5 1226.001 ;
    END
  END n_OUTS<336>
  PIN n_OUTS<335>
    DIRECTION INOUT ;
    USE SIGNAL ;
    PORT
      LAYER METAL3 ;
        RECT 362.88 1223.201 364.28 1226.001 ;
    END
  END n_OUTS<335>
  PIN n_OUTS<334>
    DIRECTION INOUT ;
    USE SIGNAL ;
    PORT
      LAYER METAL3 ;
        RECT 366.66 1223.201 368.06 1226.001 ;
    END
  END n_OUTS<334>
  PIN n_OUTS<333>
    DIRECTION INOUT ;
    USE SIGNAL ;
    PORT
      LAYER METAL3 ;
        RECT 370.44 1223.201 371.84 1226.001 ;
    END
  END n_OUTS<333>
  PIN n_OUTS<332>
    DIRECTION INOUT ;
    USE SIGNAL ;
    PORT
      LAYER METAL3 ;
        RECT 374.22 1223.201 375.62 1226.001 ;
    END
  END n_OUTS<332>
  PIN n_OUTS<331>
    DIRECTION INOUT ;
    USE SIGNAL ;
    PORT
      LAYER METAL3 ;
        RECT 378.0 1223.201 379.4 1226.001 ;
    END
  END n_OUTS<331>
  PIN n_OUTS<330>
    DIRECTION INOUT ;
    USE SIGNAL ;
    PORT
      LAYER METAL3 ;
        RECT 381.78 1223.201 383.18 1226.001 ;
    END
  END n_OUTS<330>
  PIN n_OUTS<329>
    DIRECTION INOUT ;
    USE SIGNAL ;
    PORT
      LAYER METAL3 ;
        RECT 385.56 1223.201 386.96 1226.001 ;
    END
  END n_OUTS<329>
  PIN n_OUTS<328>
    DIRECTION INOUT ;
    USE SIGNAL ;
    PORT
      LAYER METAL3 ;
        RECT 389.34 1223.201 390.74 1226.001 ;
    END
  END n_OUTS<328>
  PIN n_OUTS<327>
    DIRECTION INOUT ;
    USE SIGNAL ;
    PORT
      LAYER METAL3 ;
        RECT 393.12 1223.201 394.52 1226.001 ;
    END
  END n_OUTS<327>
  PIN n_OUTS<326>
    DIRECTION INOUT ;
    USE SIGNAL ;
    PORT
      LAYER METAL3 ;
        RECT 396.9 1223.201 398.3 1226.001 ;
    END
  END n_OUTS<326>
  PIN n_OUTS<325>
    DIRECTION INOUT ;
    USE SIGNAL ;
    PORT
      LAYER METAL3 ;
        RECT 400.68 1223.201 402.08 1226.001 ;
    END
  END n_OUTS<325>
  PIN n_OUTS<324>
    DIRECTION INOUT ;
    USE SIGNAL ;
    PORT
      LAYER METAL3 ;
        RECT 404.46 1223.201 405.86 1226.001 ;
    END
  END n_OUTS<324>
  PIN n_OUTS<323>
    DIRECTION INOUT ;
    USE SIGNAL ;
    PORT
      LAYER METAL3 ;
        RECT 408.24 1223.201 409.64 1226.001 ;
    END
  END n_OUTS<323>
  PIN n_OUTS<322>
    DIRECTION INOUT ;
    USE SIGNAL ;
    PORT
      LAYER METAL3 ;
        RECT 412.02 1223.201 413.42 1226.001 ;
    END
  END n_OUTS<322>
  PIN n_OUTS<321>
    DIRECTION INOUT ;
    USE SIGNAL ;
    PORT
      LAYER METAL3 ;
        RECT 415.8 1223.201 417.2 1226.001 ;
    END
  END n_OUTS<321>
  PIN n_OUTS<320>
    DIRECTION INOUT ;
    USE SIGNAL ;
    PORT
      LAYER METAL3 ;
        RECT 419.58 1223.201 420.98 1226.001 ;
    END
  END n_OUTS<320>
  PIN n_OUTS<319>
    DIRECTION INOUT ;
    USE SIGNAL ;
    PORT
      LAYER METAL3 ;
        RECT 423.36 1223.201 424.76 1226.001 ;
    END
  END n_OUTS<319>
  PIN n_OUTS<318>
    DIRECTION INOUT ;
    USE SIGNAL ;
    PORT
      LAYER METAL3 ;
        RECT 427.14 1223.201 428.54 1226.001 ;
    END
  END n_OUTS<318>
  PIN n_OUTS<317>
    DIRECTION INOUT ;
    USE SIGNAL ;
    PORT
      LAYER METAL3 ;
        RECT 430.92 1223.201 432.32 1226.001 ;
    END
  END n_OUTS<317>
  PIN n_OUTS<316>
    DIRECTION INOUT ;
    USE SIGNAL ;
    PORT
      LAYER METAL3 ;
        RECT 434.7 1223.201 436.1 1226.001 ;
    END
  END n_OUTS<316>
  PIN n_OUTS<315>
    DIRECTION INOUT ;
    USE SIGNAL ;
    PORT
      LAYER METAL3 ;
        RECT 438.48 1223.201 439.88 1226.001 ;
    END
  END n_OUTS<315>
  PIN n_OUTS<314>
    DIRECTION INOUT ;
    USE SIGNAL ;
    PORT
      LAYER METAL3 ;
        RECT 442.26 1223.201 443.66 1226.001 ;
    END
  END n_OUTS<314>
  PIN n_OUTS<313>
    DIRECTION INOUT ;
    USE SIGNAL ;
    PORT
      LAYER METAL3 ;
        RECT 446.04 1223.201 447.44 1226.001 ;
    END
  END n_OUTS<313>
  PIN n_OUTS<312>
    DIRECTION INOUT ;
    USE SIGNAL ;
    PORT
      LAYER METAL3 ;
        RECT 449.82 1223.201 451.22 1226.001 ;
    END
  END n_OUTS<312>
  PIN n_OUTS<311>
    DIRECTION INOUT ;
    USE SIGNAL ;
    PORT
      LAYER METAL3 ;
        RECT 453.6 1223.201 455.0 1226.001 ;
    END
  END n_OUTS<311>
  PIN n_OUTS<310>
    DIRECTION INOUT ;
    USE SIGNAL ;
    PORT
      LAYER METAL3 ;
        RECT 457.38 1223.201 458.78 1226.001 ;
    END
  END n_OUTS<310>
  PIN n_OUTS<309>
    DIRECTION INOUT ;
    USE SIGNAL ;
    PORT
      LAYER METAL3 ;
        RECT 461.16 1223.201 462.56 1226.001 ;
    END
  END n_OUTS<309>
  PIN n_OUTS<308>
    DIRECTION INOUT ;
    USE SIGNAL ;
    PORT
      LAYER METAL3 ;
        RECT 464.94 1223.201 466.34 1226.001 ;
    END
  END n_OUTS<308>
  PIN n_OUTS<307>
    DIRECTION INOUT ;
    USE SIGNAL ;
    PORT
      LAYER METAL3 ;
        RECT 468.72 1223.201 470.12 1226.001 ;
    END
  END n_OUTS<307>
  PIN n_OUTS<306>
    DIRECTION INOUT ;
    USE SIGNAL ;
    PORT
      LAYER METAL3 ;
        RECT 472.5 1223.201 473.9 1226.001 ;
    END
  END n_OUTS<306>
  PIN n_OUTS<305>
    DIRECTION INOUT ;
    USE SIGNAL ;
    PORT
      LAYER METAL3 ;
        RECT 476.28 1223.201 477.68 1226.001 ;
    END
  END n_OUTS<305>
  PIN n_OUTS<304>
    DIRECTION INOUT ;
    USE SIGNAL ;
    PORT
      LAYER METAL3 ;
        RECT 480.06 1223.201 481.46 1226.001 ;
    END
  END n_OUTS<304>
  PIN n_OUTS<303>
    DIRECTION INOUT ;
    USE SIGNAL ;
    PORT
      LAYER METAL3 ;
        RECT 483.84 1223.201 485.24 1226.001 ;
    END
  END n_OUTS<303>
  PIN n_OUTS<302>
    DIRECTION INOUT ;
    USE SIGNAL ;
    PORT
      LAYER METAL3 ;
        RECT 487.62 1223.201 489.02 1226.001 ;
    END
  END n_OUTS<302>
  PIN n_OUTS<301>
    DIRECTION INOUT ;
    USE SIGNAL ;
    PORT
      LAYER METAL3 ;
        RECT 491.4 1223.201 492.8 1226.001 ;
    END
  END n_OUTS<301>
  PIN n_OUTS<300>
    DIRECTION INOUT ;
    USE SIGNAL ;
    PORT
      LAYER METAL3 ;
        RECT 495.18 1223.201 496.58 1226.001 ;
    END
  END n_OUTS<300>
  PIN n_OUTS<299>
    DIRECTION INOUT ;
    USE SIGNAL ;
    PORT
      LAYER METAL3 ;
        RECT 498.96 1223.201 500.36 1226.001 ;
    END
  END n_OUTS<299>
  PIN n_OUTS<298>
    DIRECTION INOUT ;
    USE SIGNAL ;
    PORT
      LAYER METAL3 ;
        RECT 502.74 1223.201 504.14 1226.001 ;
    END
  END n_OUTS<298>
  PIN n_OUTS<297>
    DIRECTION INOUT ;
    USE SIGNAL ;
    PORT
      LAYER METAL3 ;
        RECT 506.52 1223.201 507.92 1226.001 ;
    END
  END n_OUTS<297>
  PIN n_OUTS<296>
    DIRECTION INOUT ;
    USE SIGNAL ;
    PORT
      LAYER METAL3 ;
        RECT 510.3 1223.201 511.7 1226.001 ;
    END
  END n_OUTS<296>
  PIN n_OUTS<295>
    DIRECTION INOUT ;
    USE SIGNAL ;
    PORT
      LAYER METAL3 ;
        RECT 514.08 1223.201 515.48 1226.001 ;
    END
  END n_OUTS<295>
  PIN n_OUTS<294>
    DIRECTION INOUT ;
    USE SIGNAL ;
    PORT
      LAYER METAL3 ;
        RECT 517.86 1223.201 519.26 1226.001 ;
    END
  END n_OUTS<294>
  PIN n_OUTS<293>
    DIRECTION INOUT ;
    USE SIGNAL ;
    PORT
      LAYER METAL3 ;
        RECT 521.64 1223.201 523.04 1226.001 ;
    END
  END n_OUTS<293>
  PIN n_OUTS<292>
    DIRECTION INOUT ;
    USE SIGNAL ;
    PORT
      LAYER METAL3 ;
        RECT 525.42 1223.201 526.82 1226.001 ;
    END
  END n_OUTS<292>
  PIN n_OUTS<291>
    DIRECTION INOUT ;
    USE SIGNAL ;
    PORT
      LAYER METAL3 ;
        RECT 529.2 1223.201 530.6 1226.001 ;
    END
  END n_OUTS<291>
  PIN n_OUTS<290>
    DIRECTION INOUT ;
    USE SIGNAL ;
    PORT
      LAYER METAL3 ;
        RECT 532.98 1223.201 534.38 1226.001 ;
    END
  END n_OUTS<290>
  PIN n_OUTS<289>
    DIRECTION INOUT ;
    USE SIGNAL ;
    PORT
      LAYER METAL3 ;
        RECT 536.76 1223.201 538.16 1226.001 ;
    END
  END n_OUTS<289>
  PIN n_OUTS<288>
    DIRECTION INOUT ;
    USE SIGNAL ;
    PORT
      LAYER METAL3 ;
        RECT 540.54 1223.201 541.94 1226.001 ;
    END
  END n_OUTS<288>
  PIN n_OUTS<287>
    DIRECTION INOUT ;
    USE SIGNAL ;
    PORT
      LAYER METAL3 ;
        RECT 544.32 1223.201 545.72 1226.001 ;
    END
  END n_OUTS<287>
  PIN n_OUTS<286>
    DIRECTION INOUT ;
    USE SIGNAL ;
    PORT
      LAYER METAL3 ;
        RECT 548.1 1223.201 549.5 1226.001 ;
    END
  END n_OUTS<286>
  PIN n_OUTS<285>
    DIRECTION INOUT ;
    USE SIGNAL ;
    PORT
      LAYER METAL3 ;
        RECT 551.88 1223.201 553.28 1226.001 ;
    END
  END n_OUTS<285>
  PIN n_OUTS<284>
    DIRECTION INOUT ;
    USE SIGNAL ;
    PORT
      LAYER METAL3 ;
        RECT 555.66 1223.201 557.06 1226.001 ;
    END
  END n_OUTS<284>
  PIN n_OUTS<283>
    DIRECTION INOUT ;
    USE SIGNAL ;
    PORT
      LAYER METAL3 ;
        RECT 559.44 1223.201 560.84 1226.001 ;
    END
  END n_OUTS<283>
  PIN n_OUTS<282>
    DIRECTION INOUT ;
    USE SIGNAL ;
    PORT
      LAYER METAL3 ;
        RECT 563.22 1223.201 564.62 1226.001 ;
    END
  END n_OUTS<282>
  PIN n_OUTS<281>
    DIRECTION INOUT ;
    USE SIGNAL ;
    PORT
      LAYER METAL3 ;
        RECT 567.0 1223.201 568.4 1226.001 ;
    END
  END n_OUTS<281>
  PIN n_OUTS<280>
    DIRECTION INOUT ;
    USE SIGNAL ;
    PORT
      LAYER METAL3 ;
        RECT 570.78 1223.201 572.18 1226.001 ;
    END
  END n_OUTS<280>
  PIN n_OUTS<279>
    DIRECTION INOUT ;
    USE SIGNAL ;
    PORT
      LAYER METAL3 ;
        RECT 574.56 1223.201 575.96 1226.001 ;
    END
  END n_OUTS<279>
  PIN n_OUTS<278>
    DIRECTION INOUT ;
    USE SIGNAL ;
    PORT
      LAYER METAL3 ;
        RECT 578.34 1223.201 579.74 1226.001 ;
    END
  END n_OUTS<278>
  PIN n_OUTS<277>
    DIRECTION INOUT ;
    USE SIGNAL ;
    PORT
      LAYER METAL3 ;
        RECT 582.12 1223.201 583.52 1226.001 ;
    END
  END n_OUTS<277>
  PIN n_OUTS<276>
    DIRECTION INOUT ;
    USE SIGNAL ;
    PORT
      LAYER METAL3 ;
        RECT 585.9 1223.201 587.3 1226.001 ;
    END
  END n_OUTS<276>
  PIN n_OUTS<275>
    DIRECTION INOUT ;
    USE SIGNAL ;
    PORT
      LAYER METAL3 ;
        RECT 589.68 1223.201 591.08 1226.001 ;
    END
  END n_OUTS<275>
  PIN n_OUTS<274>
    DIRECTION INOUT ;
    USE SIGNAL ;
    PORT
      LAYER METAL3 ;
        RECT 593.46 1223.201 594.86 1226.001 ;
    END
  END n_OUTS<274>
  PIN n_OUTS<273>
    DIRECTION INOUT ;
    USE SIGNAL ;
    PORT
      LAYER METAL3 ;
        RECT 597.24 1223.201 598.64 1226.001 ;
    END
  END n_OUTS<273>
  PIN n_OUTS<272>
    DIRECTION INOUT ;
    USE SIGNAL ;
    PORT
      LAYER METAL3 ;
        RECT 601.02 1223.201 602.42 1226.001 ;
    END
  END n_OUTS<272>
  PIN n_OUTS<271>
    DIRECTION INOUT ;
    USE SIGNAL ;
    PORT
      LAYER METAL3 ;
        RECT 604.8 1223.201 606.2 1226.001 ;
    END
  END n_OUTS<271>
  PIN n_OUTS<270>
    DIRECTION INOUT ;
    USE SIGNAL ;
    PORT
      LAYER METAL3 ;
        RECT 608.58 1223.201 609.98 1226.001 ;
    END
  END n_OUTS<270>
  PIN n_OUTS<269>
    DIRECTION INOUT ;
    USE SIGNAL ;
    PORT
      LAYER METAL3 ;
        RECT 612.36 1223.201 613.76 1226.001 ;
    END
  END n_OUTS<269>
  PIN n_OUTS<268>
    DIRECTION INOUT ;
    USE SIGNAL ;
    PORT
      LAYER METAL3 ;
        RECT 616.14 1223.201 617.54 1226.001 ;
    END
  END n_OUTS<268>
  PIN n_OUTS<267>
    DIRECTION INOUT ;
    USE SIGNAL ;
    PORT
      LAYER METAL3 ;
        RECT 619.92 1223.201 621.32 1226.001 ;
    END
  END n_OUTS<267>
  PIN n_OUTS<266>
    DIRECTION INOUT ;
    USE SIGNAL ;
    PORT
      LAYER METAL3 ;
        RECT 623.7 1223.201 625.1 1226.001 ;
    END
  END n_OUTS<266>
  PIN n_OUTS<265>
    DIRECTION INOUT ;
    USE SIGNAL ;
    PORT
      LAYER METAL3 ;
        RECT 627.48 1223.201 628.88 1226.001 ;
    END
  END n_OUTS<265>
  PIN n_OUTS<264>
    DIRECTION INOUT ;
    USE SIGNAL ;
    PORT
      LAYER METAL3 ;
        RECT 631.26 1223.201 632.66 1226.001 ;
    END
  END n_OUTS<264>
  PIN n_OUTS<263>
    DIRECTION INOUT ;
    USE SIGNAL ;
    PORT
      LAYER METAL3 ;
        RECT 635.04 1223.201 636.44 1226.001 ;
    END
  END n_OUTS<263>
  PIN n_OUTS<262>
    DIRECTION INOUT ;
    USE SIGNAL ;
    PORT
      LAYER METAL3 ;
        RECT 638.82 1223.201 640.22 1226.001 ;
    END
  END n_OUTS<262>
  PIN n_OUTS<261>
    DIRECTION INOUT ;
    USE SIGNAL ;
    PORT
      LAYER METAL3 ;
        RECT 642.6 1223.201 644.0 1226.001 ;
    END
  END n_OUTS<261>
  PIN n_OUTS<260>
    DIRECTION INOUT ;
    USE SIGNAL ;
    PORT
      LAYER METAL3 ;
        RECT 646.38 1223.201 647.78 1226.001 ;
    END
  END n_OUTS<260>
  PIN n_OUTS<259>
    DIRECTION INOUT ;
    USE SIGNAL ;
    PORT
      LAYER METAL3 ;
        RECT 650.16 1223.201 651.56 1226.001 ;
    END
  END n_OUTS<259>
  PIN n_OUTS<258>
    DIRECTION INOUT ;
    USE SIGNAL ;
    PORT
      LAYER METAL3 ;
        RECT 653.94 1223.201 655.34 1226.001 ;
    END
  END n_OUTS<258>
  PIN n_OUTS<257>
    DIRECTION INOUT ;
    USE SIGNAL ;
    PORT
      LAYER METAL3 ;
        RECT 657.72 1223.201 659.12 1226.001 ;
    END
  END n_OUTS<257>
  PIN n_OUTS<256>
    DIRECTION INOUT ;
    USE SIGNAL ;
    PORT
      LAYER METAL3 ;
        RECT 661.5 1223.201 662.9 1226.001 ;
    END
  END n_OUTS<256>
  PIN n_OUTS<255>
    DIRECTION INOUT ;
    USE SIGNAL ;
    PORT
      LAYER METAL3 ;
        RECT 665.28 1223.201 666.68 1226.001 ;
    END
  END n_OUTS<255>
  PIN n_OUTS<254>
    DIRECTION INOUT ;
    USE SIGNAL ;
    PORT
      LAYER METAL3 ;
        RECT 669.06 1223.201 670.46 1226.001 ;
    END
  END n_OUTS<254>
  PIN n_OUTS<253>
    DIRECTION INOUT ;
    USE SIGNAL ;
    PORT
      LAYER METAL3 ;
        RECT 672.84 1223.201 674.24 1226.001 ;
    END
  END n_OUTS<253>
  PIN n_OUTS<252>
    DIRECTION INOUT ;
    USE SIGNAL ;
    PORT
      LAYER METAL3 ;
        RECT 676.62 1223.201 678.02 1226.001 ;
    END
  END n_OUTS<252>
  PIN n_OUTS<251>
    DIRECTION INOUT ;
    USE SIGNAL ;
    PORT
      LAYER METAL3 ;
        RECT 680.4 1223.201 681.8 1226.001 ;
    END
  END n_OUTS<251>
  PIN n_OUTS<250>
    DIRECTION INOUT ;
    USE SIGNAL ;
    PORT
      LAYER METAL3 ;
        RECT 684.18 1223.201 685.58 1226.001 ;
    END
  END n_OUTS<250>
  PIN n_OUTS<249>
    DIRECTION INOUT ;
    USE SIGNAL ;
    PORT
      LAYER METAL3 ;
        RECT 687.96 1223.201 689.36 1226.001 ;
    END
  END n_OUTS<249>
  PIN n_OUTS<248>
    DIRECTION INOUT ;
    USE SIGNAL ;
    PORT
      LAYER METAL3 ;
        RECT 691.74 1223.201 693.14 1226.001 ;
    END
  END n_OUTS<248>
  PIN n_OUTS<247>
    DIRECTION INOUT ;
    USE SIGNAL ;
    PORT
      LAYER METAL3 ;
        RECT 695.52 1223.201 696.92 1226.001 ;
    END
  END n_OUTS<247>
  PIN n_OUTS<246>
    DIRECTION INOUT ;
    USE SIGNAL ;
    PORT
      LAYER METAL3 ;
        RECT 699.3 1223.201 700.7 1226.001 ;
    END
  END n_OUTS<246>
  PIN n_OUTS<245>
    DIRECTION INOUT ;
    USE SIGNAL ;
    PORT
      LAYER METAL3 ;
        RECT 703.08 1223.201 704.48 1226.001 ;
    END
  END n_OUTS<245>
  PIN n_OUTS<244>
    DIRECTION INOUT ;
    USE SIGNAL ;
    PORT
      LAYER METAL3 ;
        RECT 706.86 1223.201 708.26 1226.001 ;
    END
  END n_OUTS<244>
  PIN n_OUTS<243>
    DIRECTION INOUT ;
    USE SIGNAL ;
    PORT
      LAYER METAL3 ;
        RECT 710.64 1223.201 712.04 1226.001 ;
    END
  END n_OUTS<243>
  PIN n_OUTS<242>
    DIRECTION INOUT ;
    USE SIGNAL ;
    PORT
      LAYER METAL3 ;
        RECT 714.42 1223.201 715.82 1226.001 ;
    END
  END n_OUTS<242>
  PIN n_OUTS<241>
    DIRECTION INOUT ;
    USE SIGNAL ;
    PORT
      LAYER METAL3 ;
        RECT 718.2 1223.201 719.6 1226.001 ;
    END
  END n_OUTS<241>
  PIN n_OUTS<240>
    DIRECTION INOUT ;
    USE SIGNAL ;
    PORT
      LAYER METAL3 ;
        RECT 721.98 1223.201 723.38 1226.001 ;
    END
  END n_OUTS<240>
  PIN n_OUTS<239>
    DIRECTION INOUT ;
    USE SIGNAL ;
    PORT
      LAYER METAL3 ;
        RECT 725.76 1223.201 727.16 1226.001 ;
    END
  END n_OUTS<239>
  PIN n_OUTS<238>
    DIRECTION INOUT ;
    USE SIGNAL ;
    PORT
      LAYER METAL3 ;
        RECT 729.54 1223.201 730.94 1226.001 ;
    END
  END n_OUTS<238>
  PIN n_OUTS<237>
    DIRECTION INOUT ;
    USE SIGNAL ;
    PORT
      LAYER METAL3 ;
        RECT 733.32 1223.201 734.72 1226.001 ;
    END
  END n_OUTS<237>
  PIN n_OUTS<236>
    DIRECTION INOUT ;
    USE SIGNAL ;
    PORT
      LAYER METAL3 ;
        RECT 737.1 1223.201 738.5 1226.001 ;
    END
  END n_OUTS<236>
  PIN n_OUTS<235>
    DIRECTION INOUT ;
    USE SIGNAL ;
    PORT
      LAYER METAL3 ;
        RECT 740.88 1223.201 742.28 1226.001 ;
    END
  END n_OUTS<235>
  PIN n_OUTS<234>
    DIRECTION INOUT ;
    USE SIGNAL ;
    PORT
      LAYER METAL3 ;
        RECT 744.66 1223.201 746.06 1226.001 ;
    END
  END n_OUTS<234>
  PIN n_OUTS<233>
    DIRECTION INOUT ;
    USE SIGNAL ;
    PORT
      LAYER METAL3 ;
        RECT 748.44 1223.201 749.84 1226.001 ;
    END
  END n_OUTS<233>
  PIN n_OUTS<232>
    DIRECTION INOUT ;
    USE SIGNAL ;
    PORT
      LAYER METAL3 ;
        RECT 752.22 1223.201 753.62 1226.001 ;
    END
  END n_OUTS<232>
  PIN n_OUTS<231>
    DIRECTION INOUT ;
    USE SIGNAL ;
    PORT
      LAYER METAL3 ;
        RECT 756.0 1223.201 757.4 1226.001 ;
    END
  END n_OUTS<231>
  PIN n_OUTS<230>
    DIRECTION INOUT ;
    USE SIGNAL ;
    PORT
      LAYER METAL3 ;
        RECT 759.78 1223.201 761.18 1226.001 ;
    END
  END n_OUTS<230>
  PIN n_OUTS<229>
    DIRECTION INOUT ;
    USE SIGNAL ;
    PORT
      LAYER METAL3 ;
        RECT 763.56 1223.201 764.96 1226.001 ;
    END
  END n_OUTS<229>
  PIN n_OUTS<228>
    DIRECTION INOUT ;
    USE SIGNAL ;
    PORT
      LAYER METAL3 ;
        RECT 767.34 1223.201 768.74 1226.001 ;
    END
  END n_OUTS<228>
  PIN n_OUTS<227>
    DIRECTION INOUT ;
    USE SIGNAL ;
    PORT
      LAYER METAL3 ;
        RECT 771.12 1223.201 772.52 1226.001 ;
    END
  END n_OUTS<227>
  PIN n_OUTS<226>
    DIRECTION INOUT ;
    USE SIGNAL ;
    PORT
      LAYER METAL3 ;
        RECT 774.9 1223.201 776.3 1226.001 ;
    END
  END n_OUTS<226>
  PIN n_OUTS<225>
    DIRECTION INOUT ;
    USE SIGNAL ;
    PORT
      LAYER METAL3 ;
        RECT 778.68 1223.201 780.08 1226.001 ;
    END
  END n_OUTS<225>
  PIN n_OUTS<224>
    DIRECTION INOUT ;
    USE SIGNAL ;
    PORT
      LAYER METAL3 ;
        RECT 782.46 1223.201 783.86 1226.001 ;
    END
  END n_OUTS<224>
  PIN n_OUTS<223>
    DIRECTION INOUT ;
    USE SIGNAL ;
    PORT
      LAYER METAL3 ;
        RECT 786.24 1223.201 787.64 1226.001 ;
    END
  END n_OUTS<223>
  PIN n_OUTS<222>
    DIRECTION INOUT ;
    USE SIGNAL ;
    PORT
      LAYER METAL3 ;
        RECT 790.02 1223.201 791.42 1226.001 ;
    END
  END n_OUTS<222>
  PIN n_OUTS<221>
    DIRECTION INOUT ;
    USE SIGNAL ;
    PORT
      LAYER METAL3 ;
        RECT 793.8 1223.201 795.2 1226.001 ;
    END
  END n_OUTS<221>
  PIN n_OUTS<220>
    DIRECTION INOUT ;
    USE SIGNAL ;
    PORT
      LAYER METAL3 ;
        RECT 797.58 1223.201 798.98 1226.001 ;
    END
  END n_OUTS<220>
  PIN n_OUTS<219>
    DIRECTION INOUT ;
    USE SIGNAL ;
    PORT
      LAYER METAL3 ;
        RECT 801.36 1223.201 802.76 1226.001 ;
    END
  END n_OUTS<219>
  PIN n_OUTS<218>
    DIRECTION INOUT ;
    USE SIGNAL ;
    PORT
      LAYER METAL3 ;
        RECT 805.14 1223.201 806.54 1226.001 ;
    END
  END n_OUTS<218>
  PIN n_OUTS<217>
    DIRECTION INOUT ;
    USE SIGNAL ;
    PORT
      LAYER METAL3 ;
        RECT 808.92 1223.201 810.32 1226.001 ;
    END
  END n_OUTS<217>
  PIN n_OUTS<216>
    DIRECTION INOUT ;
    USE SIGNAL ;
    PORT
      LAYER METAL3 ;
        RECT 812.7 1223.201 814.1 1226.001 ;
    END
  END n_OUTS<216>
  PIN n_OUTS<215>
    DIRECTION INOUT ;
    USE SIGNAL ;
    PORT
      LAYER METAL3 ;
        RECT 816.48 1223.201 817.88 1226.001 ;
    END
  END n_OUTS<215>
  PIN n_OUTS<214>
    DIRECTION INOUT ;
    USE SIGNAL ;
    PORT
      LAYER METAL3 ;
        RECT 820.26 1223.201 821.66 1226.001 ;
    END
  END n_OUTS<214>
  PIN n_OUTS<213>
    DIRECTION INOUT ;
    USE SIGNAL ;
    PORT
      LAYER METAL3 ;
        RECT 824.04 1223.201 825.44 1226.001 ;
    END
  END n_OUTS<213>
  PIN n_OUTS<212>
    DIRECTION INOUT ;
    USE SIGNAL ;
    PORT
      LAYER METAL3 ;
        RECT 827.82 1223.201 829.22 1226.001 ;
    END
  END n_OUTS<212>
  PIN n_OUTS<211>
    DIRECTION INOUT ;
    USE SIGNAL ;
    PORT
      LAYER METAL3 ;
        RECT 831.6 1223.201 833.0 1226.001 ;
    END
  END n_OUTS<211>
  PIN n_OUTS<210>
    DIRECTION INOUT ;
    USE SIGNAL ;
    PORT
      LAYER METAL3 ;
        RECT 835.38 1223.201 836.78 1226.001 ;
    END
  END n_OUTS<210>
  PIN n_OUTS<209>
    DIRECTION INOUT ;
    USE SIGNAL ;
    PORT
      LAYER METAL3 ;
        RECT 839.16 1223.201 840.56 1226.001 ;
    END
  END n_OUTS<209>
  PIN n_OUTS<208>
    DIRECTION INOUT ;
    USE SIGNAL ;
    PORT
      LAYER METAL3 ;
        RECT 842.94 1223.201 844.34 1226.001 ;
    END
  END n_OUTS<208>
  PIN n_OUTS<207>
    DIRECTION INOUT ;
    USE SIGNAL ;
    PORT
      LAYER METAL3 ;
        RECT 846.72 1223.201 848.12 1226.001 ;
    END
  END n_OUTS<207>
  PIN n_OUTS<206>
    DIRECTION INOUT ;
    USE SIGNAL ;
    PORT
      LAYER METAL3 ;
        RECT 850.5 1223.201 851.9 1226.001 ;
    END
  END n_OUTS<206>
  PIN n_OUTS<205>
    DIRECTION INOUT ;
    USE SIGNAL ;
    PORT
      LAYER METAL3 ;
        RECT 854.28 1223.201 855.68 1226.001 ;
    END
  END n_OUTS<205>
  PIN n_OUTS<204>
    DIRECTION INOUT ;
    USE SIGNAL ;
    PORT
      LAYER METAL3 ;
        RECT 858.06 1223.201 859.46 1226.001 ;
    END
  END n_OUTS<204>
  PIN n_OUTS<203>
    DIRECTION INOUT ;
    USE SIGNAL ;
    PORT
      LAYER METAL3 ;
        RECT 861.84 1223.201 863.24 1226.001 ;
    END
  END n_OUTS<203>
  PIN n_OUTS<202>
    DIRECTION INOUT ;
    USE SIGNAL ;
    PORT
      LAYER METAL3 ;
        RECT 865.62 1223.201 867.02 1226.001 ;
    END
  END n_OUTS<202>
  PIN n_OUTS<201>
    DIRECTION INOUT ;
    USE SIGNAL ;
    PORT
      LAYER METAL3 ;
        RECT 869.4 1223.201 870.8 1226.001 ;
    END
  END n_OUTS<201>
  PIN n_OUTS<200>
    DIRECTION INOUT ;
    USE SIGNAL ;
    PORT
      LAYER METAL3 ;
        RECT 873.18 1223.201 874.58 1226.001 ;
    END
  END n_OUTS<200>
  PIN n_OUTS<199>
    DIRECTION INOUT ;
    USE SIGNAL ;
    PORT
      LAYER METAL3 ;
        RECT 876.96 1223.201 878.36 1226.001 ;
    END
  END n_OUTS<199>
  PIN n_OUTS<198>
    DIRECTION INOUT ;
    USE SIGNAL ;
    PORT
      LAYER METAL3 ;
        RECT 880.74 1223.201 882.14 1226.001 ;
    END
  END n_OUTS<198>
  PIN n_OUTS<197>
    DIRECTION INOUT ;
    USE SIGNAL ;
    PORT
      LAYER METAL3 ;
        RECT 884.52 1223.201 885.92 1226.001 ;
    END
  END n_OUTS<197>
  PIN n_OUTS<196>
    DIRECTION INOUT ;
    USE SIGNAL ;
    PORT
      LAYER METAL3 ;
        RECT 888.3 1223.201 889.7 1226.001 ;
    END
  END n_OUTS<196>
  PIN n_OUTS<195>
    DIRECTION INOUT ;
    USE SIGNAL ;
    PORT
      LAYER METAL3 ;
        RECT 892.08 1223.201 893.48 1226.001 ;
    END
  END n_OUTS<195>
  PIN n_OUTS<194>
    DIRECTION INOUT ;
    USE SIGNAL ;
    PORT
      LAYER METAL3 ;
        RECT 895.86 1223.201 897.26 1226.001 ;
    END
  END n_OUTS<194>
  PIN n_OUTS<193>
    DIRECTION INOUT ;
    USE SIGNAL ;
    PORT
      LAYER METAL3 ;
        RECT 899.64 1223.201 901.04 1226.001 ;
    END
  END n_OUTS<193>
  PIN n_OUTS<192>
    DIRECTION INOUT ;
    USE SIGNAL ;
    PORT
      LAYER METAL3 ;
        RECT 903.42 1223.201 904.82 1226.001 ;
    END
  END n_OUTS<192>
  PIN n_OUTS<191>
    DIRECTION INOUT ;
    USE SIGNAL ;
    PORT
      LAYER METAL3 ;
        RECT 907.2 1223.201 908.6 1226.001 ;
    END
  END n_OUTS<191>
  PIN n_OUTS<190>
    DIRECTION INOUT ;
    USE SIGNAL ;
    PORT
      LAYER METAL3 ;
        RECT 910.98 1223.201 912.38 1226.001 ;
    END
  END n_OUTS<190>
  PIN n_OUTS<189>
    DIRECTION INOUT ;
    USE SIGNAL ;
    PORT
      LAYER METAL3 ;
        RECT 914.76 1223.201 916.16 1226.001 ;
    END
  END n_OUTS<189>
  PIN n_OUTS<188>
    DIRECTION INOUT ;
    USE SIGNAL ;
    PORT
      LAYER METAL3 ;
        RECT 918.54 1223.201 919.94 1226.001 ;
    END
  END n_OUTS<188>
  PIN n_OUTS<187>
    DIRECTION INOUT ;
    USE SIGNAL ;
    PORT
      LAYER METAL3 ;
        RECT 922.32 1223.201 923.72 1226.001 ;
    END
  END n_OUTS<187>
  PIN n_OUTS<186>
    DIRECTION INOUT ;
    USE SIGNAL ;
    PORT
      LAYER METAL3 ;
        RECT 926.1 1223.201 927.5 1226.001 ;
    END
  END n_OUTS<186>
  PIN n_OUTS<185>
    DIRECTION INOUT ;
    USE SIGNAL ;
    PORT
      LAYER METAL3 ;
        RECT 929.88 1223.201 931.28 1226.001 ;
    END
  END n_OUTS<185>
  PIN n_OUTS<184>
    DIRECTION INOUT ;
    USE SIGNAL ;
    PORT
      LAYER METAL3 ;
        RECT 933.66 1223.201 935.06 1226.001 ;
    END
  END n_OUTS<184>
  PIN n_OUTS<183>
    DIRECTION INOUT ;
    USE SIGNAL ;
    PORT
      LAYER METAL3 ;
        RECT 937.44 1223.201 938.84 1226.001 ;
    END
  END n_OUTS<183>
  PIN n_OUTS<182>
    DIRECTION INOUT ;
    USE SIGNAL ;
    PORT
      LAYER METAL3 ;
        RECT 941.22 1223.201 942.62 1226.001 ;
    END
  END n_OUTS<182>
  PIN n_OUTS<181>
    DIRECTION INOUT ;
    USE SIGNAL ;
    PORT
      LAYER METAL3 ;
        RECT 945.0 1223.201 946.4 1226.001 ;
    END
  END n_OUTS<181>
  PIN n_OUTS<180>
    DIRECTION INOUT ;
    USE SIGNAL ;
    PORT
      LAYER METAL3 ;
        RECT 948.78 1223.201 950.18 1226.001 ;
    END
  END n_OUTS<180>
  PIN n_OUTS<179>
    DIRECTION INOUT ;
    USE SIGNAL ;
    PORT
      LAYER METAL3 ;
        RECT 952.56 1223.201 953.96 1226.001 ;
    END
  END n_OUTS<179>
  PIN n_OUTS<178>
    DIRECTION INOUT ;
    USE SIGNAL ;
    PORT
      LAYER METAL3 ;
        RECT 956.34 1223.201 957.74 1226.001 ;
    END
  END n_OUTS<178>
  PIN n_OUTS<177>
    DIRECTION INOUT ;
    USE SIGNAL ;
    PORT
      LAYER METAL3 ;
        RECT 960.12 1223.201 961.52 1226.001 ;
    END
  END n_OUTS<177>
  PIN n_OUTS<176>
    DIRECTION INOUT ;
    USE SIGNAL ;
    PORT
      LAYER METAL3 ;
        RECT 963.9 1223.201 965.3 1226.001 ;
    END
  END n_OUTS<176>
  PIN n_OUTS<175>
    DIRECTION INOUT ;
    USE SIGNAL ;
    PORT
      LAYER METAL3 ;
        RECT 967.68 1223.201 969.08 1226.001 ;
    END
  END n_OUTS<175>
  PIN n_OUTS<174>
    DIRECTION INOUT ;
    USE SIGNAL ;
    PORT
      LAYER METAL3 ;
        RECT 971.46 1223.201 972.86 1226.001 ;
    END
  END n_OUTS<174>
  PIN n_OUTS<173>
    DIRECTION INOUT ;
    USE SIGNAL ;
    PORT
      LAYER METAL3 ;
        RECT 975.24 1223.201 976.64 1226.001 ;
    END
  END n_OUTS<173>
  PIN n_OUTS<172>
    DIRECTION INOUT ;
    USE SIGNAL ;
    PORT
      LAYER METAL3 ;
        RECT 979.02 1223.201 980.42 1226.001 ;
    END
  END n_OUTS<172>
  PIN n_OUTS<171>
    DIRECTION INOUT ;
    USE SIGNAL ;
    PORT
      LAYER METAL3 ;
        RECT 982.8 1223.201 984.2 1226.001 ;
    END
  END n_OUTS<171>
  PIN n_OUTS<170>
    DIRECTION INOUT ;
    USE SIGNAL ;
    PORT
      LAYER METAL3 ;
        RECT 986.58 1223.201 987.98 1226.001 ;
    END
  END n_OUTS<170>
  PIN n_OUTS<169>
    DIRECTION INOUT ;
    USE SIGNAL ;
    PORT
      LAYER METAL3 ;
        RECT 990.36 1223.201 991.76 1226.001 ;
    END
  END n_OUTS<169>
  PIN n_OUTS<168>
    DIRECTION INOUT ;
    USE SIGNAL ;
    PORT
      LAYER METAL3 ;
        RECT 994.14 1223.201 995.54 1226.001 ;
    END
  END n_OUTS<168>
  PIN n_OUTS<167>
    DIRECTION INOUT ;
    USE SIGNAL ;
    PORT
      LAYER METAL3 ;
        RECT 997.92 1223.201 999.32 1226.001 ;
    END
  END n_OUTS<167>
  PIN n_OUTS<166>
    DIRECTION INOUT ;
    USE SIGNAL ;
    PORT
      LAYER METAL3 ;
        RECT 1001.7 1223.201 1003.1 1226.001 ;
    END
  END n_OUTS<166>
  PIN n_OUTS<165>
    DIRECTION INOUT ;
    USE SIGNAL ;
    PORT
      LAYER METAL3 ;
        RECT 1005.48 1223.201 1006.88 1226.001 ;
    END
  END n_OUTS<165>
  PIN n_OUTS<164>
    DIRECTION INOUT ;
    USE SIGNAL ;
    PORT
      LAYER METAL3 ;
        RECT 1009.26 1223.201 1010.66 1226.001 ;
    END
  END n_OUTS<164>
  PIN n_OUTS<163>
    DIRECTION INOUT ;
    USE SIGNAL ;
    PORT
      LAYER METAL3 ;
        RECT 1013.04 1223.201 1014.44 1226.001 ;
    END
  END n_OUTS<163>
  PIN n_OUTS<162>
    DIRECTION INOUT ;
    USE SIGNAL ;
    PORT
      LAYER METAL3 ;
        RECT 1016.82 1223.201 1018.22 1226.001 ;
    END
  END n_OUTS<162>
  PIN n_OUTS<161>
    DIRECTION INOUT ;
    USE SIGNAL ;
    PORT
      LAYER METAL3 ;
        RECT 1020.6 1223.201 1022.0 1226.001 ;
    END
  END n_OUTS<161>
  PIN n_OUTS<160>
    DIRECTION INOUT ;
    USE SIGNAL ;
    PORT
      LAYER METAL3 ;
        RECT 1024.38 1223.201 1025.78 1226.001 ;
    END
  END n_OUTS<160>
  PIN n_OUTS<159>
    DIRECTION INOUT ;
    USE SIGNAL ;
    PORT
      LAYER METAL3 ;
        RECT 1028.16 1223.201 1029.56 1226.001 ;
    END
  END n_OUTS<159>
  PIN n_OUTS<158>
    DIRECTION INOUT ;
    USE SIGNAL ;
    PORT
      LAYER METAL3 ;
        RECT 1031.94 1223.201 1033.34 1226.001 ;
    END
  END n_OUTS<158>
  PIN n_OUTS<157>
    DIRECTION INOUT ;
    USE SIGNAL ;
    PORT
      LAYER METAL3 ;
        RECT 1035.72 1223.201 1037.12 1226.001 ;
    END
  END n_OUTS<157>
  PIN n_OUTS<156>
    DIRECTION INOUT ;
    USE SIGNAL ;
    PORT
      LAYER METAL3 ;
        RECT 1039.5 1223.201 1040.9 1226.001 ;
    END
  END n_OUTS<156>
  PIN n_OUTS<155>
    DIRECTION INOUT ;
    USE SIGNAL ;
    PORT
      LAYER METAL3 ;
        RECT 1043.28 1223.201 1044.68 1226.001 ;
    END
  END n_OUTS<155>
  PIN n_OUTS<154>
    DIRECTION INOUT ;
    USE SIGNAL ;
    PORT
      LAYER METAL3 ;
        RECT 1047.06 1223.201 1048.46 1226.001 ;
    END
  END n_OUTS<154>
  PIN n_OUTS<153>
    DIRECTION INOUT ;
    USE SIGNAL ;
    PORT
      LAYER METAL3 ;
        RECT 1050.84 1223.201 1052.24 1226.001 ;
    END
  END n_OUTS<153>
  PIN n_OUTS<152>
    DIRECTION INOUT ;
    USE SIGNAL ;
    PORT
      LAYER METAL3 ;
        RECT 1054.62 1223.201 1056.02 1226.001 ;
    END
  END n_OUTS<152>
  PIN n_OUTS<151>
    DIRECTION INOUT ;
    USE SIGNAL ;
    PORT
      LAYER METAL3 ;
        RECT 1058.4 1223.201 1059.8 1226.001 ;
    END
  END n_OUTS<151>
  PIN n_OUTS<150>
    DIRECTION INOUT ;
    USE SIGNAL ;
    PORT
      LAYER METAL3 ;
        RECT 1062.18 1223.201 1063.58 1226.001 ;
    END
  END n_OUTS<150>
  PIN n_OUTS<149>
    DIRECTION INOUT ;
    USE SIGNAL ;
    PORT
      LAYER METAL3 ;
        RECT 1065.96 1223.201 1067.36 1226.001 ;
    END
  END n_OUTS<149>
  PIN n_OUTS<148>
    DIRECTION INOUT ;
    USE SIGNAL ;
    PORT
      LAYER METAL3 ;
        RECT 1069.74 1223.201 1071.14 1226.001 ;
    END
  END n_OUTS<148>
  PIN n_OUTS<147>
    DIRECTION INOUT ;
    USE SIGNAL ;
    PORT
      LAYER METAL3 ;
        RECT 1073.52 1223.201 1074.92 1226.001 ;
    END
  END n_OUTS<147>
  PIN n_OUTS<146>
    DIRECTION INOUT ;
    USE SIGNAL ;
    PORT
      LAYER METAL3 ;
        RECT 1077.3 1223.201 1078.7 1226.001 ;
    END
  END n_OUTS<146>
  PIN n_OUTS<145>
    DIRECTION INOUT ;
    USE SIGNAL ;
    PORT
      LAYER METAL3 ;
        RECT 1081.08 1223.201 1082.48 1226.001 ;
    END
  END n_OUTS<145>
  PIN n_OUTS<144>
    DIRECTION INOUT ;
    USE SIGNAL ;
    PORT
      LAYER METAL3 ;
        RECT 1084.86 1223.201 1086.26 1226.001 ;
    END
  END n_OUTS<144>
  PIN n_OUTS<143>
    DIRECTION INOUT ;
    USE SIGNAL ;
    PORT
      LAYER METAL3 ;
        RECT 1088.64 1223.201 1090.04 1226.001 ;
    END
  END n_OUTS<143>
  PIN n_OUTS<142>
    DIRECTION INOUT ;
    USE SIGNAL ;
    PORT
      LAYER METAL3 ;
        RECT 1092.42 1223.201 1093.82 1226.001 ;
    END
  END n_OUTS<142>
  PIN n_OUTS<141>
    DIRECTION INOUT ;
    USE SIGNAL ;
    PORT
      LAYER METAL3 ;
        RECT 1096.2 1223.201 1097.6 1226.001 ;
    END
  END n_OUTS<141>
  PIN n_OUTS<140>
    DIRECTION INOUT ;
    USE SIGNAL ;
    PORT
      LAYER METAL3 ;
        RECT 1099.98 1223.201 1101.38 1226.001 ;
    END
  END n_OUTS<140>
  PIN n_OUTS<139>
    DIRECTION INOUT ;
    USE SIGNAL ;
    PORT
      LAYER METAL3 ;
        RECT 1103.76 1223.201 1105.16 1226.001 ;
    END
  END n_OUTS<139>
  PIN n_OUTS<138>
    DIRECTION INOUT ;
    USE SIGNAL ;
    PORT
      LAYER METAL3 ;
        RECT 1107.54 1223.201 1108.94 1226.001 ;
    END
  END n_OUTS<138>
  PIN n_OUTS<137>
    DIRECTION INOUT ;
    USE SIGNAL ;
    PORT
      LAYER METAL3 ;
        RECT 1111.32 1223.201 1112.72 1226.001 ;
    END
  END n_OUTS<137>
  PIN n_OUTS<136>
    DIRECTION INOUT ;
    USE SIGNAL ;
    PORT
      LAYER METAL3 ;
        RECT 1115.1 1223.201 1116.5 1226.001 ;
    END
  END n_OUTS<136>
  PIN n_OUTS<135>
    DIRECTION INOUT ;
    USE SIGNAL ;
    PORT
      LAYER METAL3 ;
        RECT 1118.88 1223.201 1120.28 1226.001 ;
    END
  END n_OUTS<135>
  PIN n_OUTS<134>
    DIRECTION INOUT ;
    USE SIGNAL ;
    PORT
      LAYER METAL3 ;
        RECT 1122.66 1223.201 1124.06 1226.001 ;
    END
  END n_OUTS<134>
  PIN n_OUTS<133>
    DIRECTION INOUT ;
    USE SIGNAL ;
    PORT
      LAYER METAL3 ;
        RECT 1126.44 1223.201 1127.84 1226.001 ;
    END
  END n_OUTS<133>
  PIN n_OUTS<132>
    DIRECTION INOUT ;
    USE SIGNAL ;
    PORT
      LAYER METAL3 ;
        RECT 1130.22 1223.201 1131.62 1226.001 ;
    END
  END n_OUTS<132>
  PIN n_OUTS<131>
    DIRECTION INOUT ;
    USE SIGNAL ;
    PORT
      LAYER METAL3 ;
        RECT 1134.0 1223.201 1135.4 1226.001 ;
    END
  END n_OUTS<131>
  PIN n_OUTS<130>
    DIRECTION INOUT ;
    USE SIGNAL ;
    PORT
      LAYER METAL3 ;
        RECT 1137.78 1223.201 1139.18 1226.001 ;
    END
  END n_OUTS<130>
  PIN n_OUTS<129>
    DIRECTION INOUT ;
    USE SIGNAL ;
    PORT
      LAYER METAL3 ;
        RECT 1141.56 1223.201 1142.96 1226.001 ;
    END
  END n_OUTS<129>
  PIN n_OUTS<128>
    DIRECTION INOUT ;
    USE SIGNAL ;
    PORT
      LAYER METAL3 ;
        RECT 1145.34 1223.201 1146.74 1226.001 ;
    END
  END n_OUTS<128>
  PIN n_OUTS<127>
    DIRECTION INOUT ;
    USE SIGNAL ;
    PORT
      LAYER METAL3 ;
        RECT 1149.12 1223.201 1150.52 1226.001 ;
    END
  END n_OUTS<127>
  PIN n_OUTS<126>
    DIRECTION INOUT ;
    USE SIGNAL ;
    PORT
      LAYER METAL3 ;
        RECT 1152.9 1223.201 1154.3 1226.001 ;
    END
  END n_OUTS<126>
  PIN n_OUTS<125>
    DIRECTION INOUT ;
    USE SIGNAL ;
    PORT
      LAYER METAL3 ;
        RECT 1156.68 1223.201 1158.08 1226.001 ;
    END
  END n_OUTS<125>
  PIN n_OUTS<124>
    DIRECTION INOUT ;
    USE SIGNAL ;
    PORT
      LAYER METAL3 ;
        RECT 1160.46 1223.201 1161.86 1226.001 ;
    END
  END n_OUTS<124>
  PIN n_OUTS<123>
    DIRECTION INOUT ;
    USE SIGNAL ;
    PORT
      LAYER METAL3 ;
        RECT 1164.24 1223.201 1165.64 1226.001 ;
    END
  END n_OUTS<123>
  PIN n_OUTS<122>
    DIRECTION INOUT ;
    USE SIGNAL ;
    PORT
      LAYER METAL3 ;
        RECT 1168.02 1223.201 1169.42 1226.001 ;
    END
  END n_OUTS<122>
  PIN n_OUTS<121>
    DIRECTION INOUT ;
    USE SIGNAL ;
    PORT
      LAYER METAL3 ;
        RECT 1171.8 1223.201 1173.2 1226.001 ;
    END
  END n_OUTS<121>
  PIN n_OUTS<120>
    DIRECTION INOUT ;
    USE SIGNAL ;
    PORT
      LAYER METAL3 ;
        RECT 1175.58 1223.201 1176.98 1226.001 ;
    END
  END n_OUTS<120>
  PIN n_OUTS<119>
    DIRECTION INOUT ;
    USE SIGNAL ;
    PORT
      LAYER METAL3 ;
        RECT 1179.36 1223.201 1180.76 1226.001 ;
    END
  END n_OUTS<119>
  PIN n_OUTS<118>
    DIRECTION INOUT ;
    USE SIGNAL ;
    PORT
      LAYER METAL3 ;
        RECT 1183.14 1223.201 1184.54 1226.001 ;
    END
  END n_OUTS<118>
  PIN n_OUTS<117>
    DIRECTION INOUT ;
    USE SIGNAL ;
    PORT
      LAYER METAL3 ;
        RECT 1186.92 1223.201 1188.32 1226.001 ;
    END
  END n_OUTS<117>
  PIN n_OUTS<116>
    DIRECTION INOUT ;
    USE SIGNAL ;
    PORT
      LAYER METAL3 ;
        RECT 1190.7 1223.201 1192.1 1226.001 ;
    END
  END n_OUTS<116>
  PIN n_OUTS<115>
    DIRECTION INOUT ;
    USE SIGNAL ;
    PORT
      LAYER METAL3 ;
        RECT 1194.48 1223.201 1195.88 1226.001 ;
    END
  END n_OUTS<115>
  PIN n_OUTS<114>
    DIRECTION INOUT ;
    USE SIGNAL ;
    PORT
      LAYER METAL3 ;
        RECT 1198.26 1223.201 1199.66 1226.001 ;
    END
  END n_OUTS<114>
  PIN n_OUTS<113>
    DIRECTION INOUT ;
    USE SIGNAL ;
    PORT
      LAYER METAL3 ;
        RECT 1202.04 1223.201 1203.44 1226.001 ;
    END
  END n_OUTS<113>
  PIN n_OUTS<112>
    DIRECTION INOUT ;
    USE SIGNAL ;
    PORT
      LAYER METAL3 ;
        RECT 1205.82 1223.201 1207.22 1226.001 ;
    END
  END n_OUTS<112>
  PIN n_OUTS<111>
    DIRECTION INOUT ;
    USE SIGNAL ;
    PORT
      LAYER METAL3 ;
        RECT 1209.6 1223.201 1211.0 1226.001 ;
    END
  END n_OUTS<111>
  PIN n_OUTS<110>
    DIRECTION INOUT ;
    USE SIGNAL ;
    PORT
      LAYER METAL3 ;
        RECT 1213.38 1223.201 1214.78 1226.001 ;
    END
  END n_OUTS<110>
  PIN n_OUTS<109>
    DIRECTION INOUT ;
    USE SIGNAL ;
    PORT
      LAYER METAL3 ;
        RECT 1217.16 1223.201 1218.56 1226.001 ;
    END
  END n_OUTS<109>
  PIN n_OUTS<108>
    DIRECTION INOUT ;
    USE SIGNAL ;
    PORT
      LAYER METAL3 ;
        RECT 1220.94 1223.201 1222.34 1226.001 ;
    END
  END n_OUTS<108>
  PIN n_OUTS<107>
    DIRECTION INOUT ;
    USE SIGNAL ;
    PORT
      LAYER METAL3 ;
        RECT 1224.72 1223.201 1226.12 1226.001 ;
    END
  END n_OUTS<107>
  PIN n_OUTS<106>
    DIRECTION INOUT ;
    USE SIGNAL ;
    PORT
      LAYER METAL3 ;
        RECT 1228.5 1223.201 1229.9 1226.001 ;
    END
  END n_OUTS<106>
  PIN n_OUTS<105>
    DIRECTION INOUT ;
    USE SIGNAL ;
    PORT
      LAYER METAL3 ;
        RECT 1232.28 1223.201 1233.68 1226.001 ;
    END
  END n_OUTS<105>
  PIN n_OUTS<104>
    DIRECTION INOUT ;
    USE SIGNAL ;
    PORT
      LAYER METAL3 ;
        RECT 1236.06 1223.201 1237.46 1226.001 ;
    END
  END n_OUTS<104>
  PIN n_OUTS<103>
    DIRECTION INOUT ;
    USE SIGNAL ;
    PORT
      LAYER METAL3 ;
        RECT 1239.84 1223.201 1241.24 1226.001 ;
    END
  END n_OUTS<103>
  PIN n_OUTS<102>
    DIRECTION INOUT ;
    USE SIGNAL ;
    PORT
      LAYER METAL3 ;
        RECT 1243.62 1223.201 1245.02 1226.001 ;
    END
  END n_OUTS<102>
  PIN n_OUTS<101>
    DIRECTION INOUT ;
    USE SIGNAL ;
    PORT
      LAYER METAL3 ;
        RECT 1247.4 1223.201 1248.8 1226.001 ;
    END
  END n_OUTS<101>
  PIN n_OUTS<100>
    DIRECTION INOUT ;
    USE SIGNAL ;
    PORT
      LAYER METAL3 ;
        RECT 1251.18 1223.201 1252.58 1226.001 ;
    END
  END n_OUTS<100>
  PIN n_OUTS<99>
    DIRECTION INOUT ;
    USE SIGNAL ;
    PORT
      LAYER METAL3 ;
        RECT 1254.96 1223.201 1256.36 1226.001 ;
    END
  END n_OUTS<99>
  PIN n_OUTS<98>
    DIRECTION INOUT ;
    USE SIGNAL ;
    PORT
      LAYER METAL3 ;
        RECT 1258.74 1223.201 1260.14 1226.001 ;
    END
  END n_OUTS<98>
  PIN n_OUTS<97>
    DIRECTION INOUT ;
    USE SIGNAL ;
    PORT
      LAYER METAL3 ;
        RECT 1262.52 1223.201 1263.92 1226.001 ;
    END
  END n_OUTS<97>
  PIN n_OUTS<96>
    DIRECTION INOUT ;
    USE SIGNAL ;
    PORT
      LAYER METAL3 ;
        RECT 1266.3 1223.201 1267.7 1226.001 ;
    END
  END n_OUTS<96>
  PIN n_OUTS<95>
    DIRECTION INOUT ;
    USE SIGNAL ;
    PORT
      LAYER METAL3 ;
        RECT 1270.08 1223.201 1271.48 1226.001 ;
    END
  END n_OUTS<95>
  PIN n_OUTS<94>
    DIRECTION INOUT ;
    USE SIGNAL ;
    PORT
      LAYER METAL3 ;
        RECT 1273.86 1223.201 1275.26 1226.001 ;
    END
  END n_OUTS<94>
  PIN n_OUTS<93>
    DIRECTION INOUT ;
    USE SIGNAL ;
    PORT
      LAYER METAL3 ;
        RECT 1277.64 1223.201 1279.04 1226.001 ;
    END
  END n_OUTS<93>
  PIN n_OUTS<92>
    DIRECTION INOUT ;
    USE SIGNAL ;
    PORT
      LAYER METAL3 ;
        RECT 1281.42 1223.201 1282.82 1226.001 ;
    END
  END n_OUTS<92>
  PIN n_OUTS<91>
    DIRECTION INOUT ;
    USE SIGNAL ;
    PORT
      LAYER METAL3 ;
        RECT 1285.2 1223.201 1286.6 1226.001 ;
    END
  END n_OUTS<91>
  PIN n_OUTS<90>
    DIRECTION INOUT ;
    USE SIGNAL ;
    PORT
      LAYER METAL3 ;
        RECT 1288.98 1223.201 1290.38 1226.001 ;
    END
  END n_OUTS<90>
  PIN n_OUTS<89>
    DIRECTION INOUT ;
    USE SIGNAL ;
    PORT
      LAYER METAL3 ;
        RECT 1292.76 1223.201 1294.16 1226.001 ;
    END
  END n_OUTS<89>
  PIN n_OUTS<88>
    DIRECTION INOUT ;
    USE SIGNAL ;
    PORT
      LAYER METAL3 ;
        RECT 1296.54 1223.201 1297.94 1226.001 ;
    END
  END n_OUTS<88>
  PIN n_OUTS<87>
    DIRECTION INOUT ;
    USE SIGNAL ;
    PORT
      LAYER METAL3 ;
        RECT 1300.32 1223.201 1301.72 1226.001 ;
    END
  END n_OUTS<87>
  PIN n_OUTS<86>
    DIRECTION INOUT ;
    USE SIGNAL ;
    PORT
      LAYER METAL3 ;
        RECT 1304.1 1223.201 1305.5 1226.001 ;
    END
  END n_OUTS<86>
  PIN n_OUTS<85>
    DIRECTION INOUT ;
    USE SIGNAL ;
    PORT
      LAYER METAL3 ;
        RECT 1307.88 1223.201 1309.28 1226.001 ;
    END
  END n_OUTS<85>
  PIN n_OUTS<84>
    DIRECTION INOUT ;
    USE SIGNAL ;
    PORT
      LAYER METAL3 ;
        RECT 1311.66 1223.201 1313.06 1226.001 ;
    END
  END n_OUTS<84>
  PIN n_OUTS<83>
    DIRECTION INOUT ;
    USE SIGNAL ;
    PORT
      LAYER METAL3 ;
        RECT 1315.44 1223.201 1316.84 1226.001 ;
    END
  END n_OUTS<83>
  PIN n_OUTS<82>
    DIRECTION INOUT ;
    USE SIGNAL ;
    PORT
      LAYER METAL3 ;
        RECT 1319.22 1223.201 1320.62 1226.001 ;
    END
  END n_OUTS<82>
  PIN n_OUTS<81>
    DIRECTION INOUT ;
    USE SIGNAL ;
    PORT
      LAYER METAL3 ;
        RECT 1323.0 1223.201 1324.4 1226.001 ;
    END
  END n_OUTS<81>
  PIN n_OUTS<80>
    DIRECTION INOUT ;
    USE SIGNAL ;
    PORT
      LAYER METAL3 ;
        RECT 1326.78 1223.201 1328.18 1226.001 ;
    END
  END n_OUTS<80>
  PIN n_OUTS<79>
    DIRECTION INOUT ;
    USE SIGNAL ;
    PORT
      LAYER METAL3 ;
        RECT 1330.56 1223.201 1331.96 1226.001 ;
    END
  END n_OUTS<79>
  PIN n_OUTS<78>
    DIRECTION INOUT ;
    USE SIGNAL ;
    PORT
      LAYER METAL3 ;
        RECT 1334.34 1223.201 1335.74 1226.001 ;
    END
  END n_OUTS<78>
  PIN n_OUTS<77>
    DIRECTION INOUT ;
    USE SIGNAL ;
    PORT
      LAYER METAL3 ;
        RECT 1338.12 1223.201 1339.52 1226.001 ;
    END
  END n_OUTS<77>
  PIN n_OUTS<76>
    DIRECTION INOUT ;
    USE SIGNAL ;
    PORT
      LAYER METAL3 ;
        RECT 1341.9 1223.201 1343.3 1226.001 ;
    END
  END n_OUTS<76>
  PIN n_OUTS<75>
    DIRECTION INOUT ;
    USE SIGNAL ;
    PORT
      LAYER METAL3 ;
        RECT 1345.68 1223.201 1347.08 1226.001 ;
    END
  END n_OUTS<75>
  PIN n_OUTS<74>
    DIRECTION INOUT ;
    USE SIGNAL ;
    PORT
      LAYER METAL3 ;
        RECT 1349.46 1223.201 1350.86 1226.001 ;
    END
  END n_OUTS<74>
  PIN n_OUTS<73>
    DIRECTION INOUT ;
    USE SIGNAL ;
    PORT
      LAYER METAL3 ;
        RECT 1353.24 1223.201 1354.64 1226.001 ;
    END
  END n_OUTS<73>
  PIN n_OUTS<72>
    DIRECTION INOUT ;
    USE SIGNAL ;
    PORT
      LAYER METAL3 ;
        RECT 1357.02 1223.201 1358.42 1226.001 ;
    END
  END n_OUTS<72>
  PIN n_OUTS<71>
    DIRECTION INOUT ;
    USE SIGNAL ;
    PORT
      LAYER METAL3 ;
        RECT 1360.8 1223.201 1362.2 1226.001 ;
    END
  END n_OUTS<71>
  PIN n_OUTS<70>
    DIRECTION INOUT ;
    USE SIGNAL ;
    PORT
      LAYER METAL3 ;
        RECT 1364.58 1223.201 1365.98 1226.001 ;
    END
  END n_OUTS<70>
  PIN n_OUTS<69>
    DIRECTION INOUT ;
    USE SIGNAL ;
    PORT
      LAYER METAL3 ;
        RECT 1368.36 1223.201 1369.76 1226.001 ;
    END
  END n_OUTS<69>
  PIN n_OUTS<68>
    DIRECTION INOUT ;
    USE SIGNAL ;
    PORT
      LAYER METAL3 ;
        RECT 1372.14 1223.201 1373.54 1226.001 ;
    END
  END n_OUTS<68>
  PIN n_OUTS<67>
    DIRECTION INOUT ;
    USE SIGNAL ;
    PORT
      LAYER METAL3 ;
        RECT 1375.92 1223.201 1377.32 1226.001 ;
    END
  END n_OUTS<67>
  PIN n_OUTS<66>
    DIRECTION INOUT ;
    USE SIGNAL ;
    PORT
      LAYER METAL3 ;
        RECT 1379.7 1223.201 1381.1 1226.001 ;
    END
  END n_OUTS<66>
  PIN n_OUTS<65>
    DIRECTION INOUT ;
    USE SIGNAL ;
    PORT
      LAYER METAL3 ;
        RECT 1383.48 1223.201 1384.88 1226.001 ;
    END
  END n_OUTS<65>
  PIN n_OUTS<64>
    DIRECTION INOUT ;
    USE SIGNAL ;
    PORT
      LAYER METAL3 ;
        RECT 1387.26 1223.201 1388.66 1226.001 ;
    END
  END n_OUTS<64>
  PIN n_OUTS<63>
    DIRECTION INOUT ;
    USE SIGNAL ;
    PORT
      LAYER METAL3 ;
        RECT 1391.04 1223.201 1392.44 1226.001 ;
    END
  END n_OUTS<63>
  PIN n_OUTS<62>
    DIRECTION INOUT ;
    USE SIGNAL ;
    PORT
      LAYER METAL3 ;
        RECT 1394.82 1223.201 1396.22 1226.001 ;
    END
  END n_OUTS<62>
  PIN n_OUTS<61>
    DIRECTION INOUT ;
    USE SIGNAL ;
    PORT
      LAYER METAL3 ;
        RECT 1398.6 1223.201 1400.0 1226.001 ;
    END
  END n_OUTS<61>
  PIN n_OUTS<60>
    DIRECTION INOUT ;
    USE SIGNAL ;
    PORT
      LAYER METAL3 ;
        RECT 1402.38 1223.201 1403.78 1226.001 ;
    END
  END n_OUTS<60>
  PIN n_OUTS<59>
    DIRECTION INOUT ;
    USE SIGNAL ;
    PORT
      LAYER METAL3 ;
        RECT 1406.16 1223.201 1407.56 1226.001 ;
    END
  END n_OUTS<59>
  PIN n_OUTS<58>
    DIRECTION INOUT ;
    USE SIGNAL ;
    PORT
      LAYER METAL3 ;
        RECT 1409.94 1223.201 1411.34 1226.001 ;
    END
  END n_OUTS<58>
  PIN n_OUTS<57>
    DIRECTION INOUT ;
    USE SIGNAL ;
    PORT
      LAYER METAL3 ;
        RECT 1413.72 1223.201 1415.12 1226.001 ;
    END
  END n_OUTS<57>
  PIN n_OUTS<56>
    DIRECTION INOUT ;
    USE SIGNAL ;
    PORT
      LAYER METAL3 ;
        RECT 1417.5 1223.201 1418.9 1226.001 ;
    END
  END n_OUTS<56>
  PIN n_OUTS<55>
    DIRECTION INOUT ;
    USE SIGNAL ;
    PORT
      LAYER METAL3 ;
        RECT 1421.28 1223.201 1422.68 1226.001 ;
    END
  END n_OUTS<55>
  PIN n_OUTS<54>
    DIRECTION INOUT ;
    USE SIGNAL ;
    PORT
      LAYER METAL3 ;
        RECT 1425.06 1223.201 1426.46 1226.001 ;
    END
  END n_OUTS<54>
  PIN n_OUTS<53>
    DIRECTION INOUT ;
    USE SIGNAL ;
    PORT
      LAYER METAL3 ;
        RECT 1428.84 1223.201 1430.24 1226.001 ;
    END
  END n_OUTS<53>
  PIN n_OUTS<52>
    DIRECTION INOUT ;
    USE SIGNAL ;
    PORT
      LAYER METAL3 ;
        RECT 1432.62 1223.201 1434.02 1226.001 ;
    END
  END n_OUTS<52>
  PIN n_OUTS<51>
    DIRECTION INOUT ;
    USE SIGNAL ;
    PORT
      LAYER METAL3 ;
        RECT 1436.4 1223.201 1437.8 1226.001 ;
    END
  END n_OUTS<51>
  PIN n_OUTS<50>
    DIRECTION INOUT ;
    USE SIGNAL ;
    PORT
      LAYER METAL3 ;
        RECT 1440.18 1223.201 1441.58 1226.001 ;
    END
  END n_OUTS<50>
  PIN n_OUTS<49>
    DIRECTION INOUT ;
    USE SIGNAL ;
    PORT
      LAYER METAL3 ;
        RECT 1443.96 1223.201 1445.36 1226.001 ;
    END
  END n_OUTS<49>
  PIN n_OUTS<48>
    DIRECTION INOUT ;
    USE SIGNAL ;
    PORT
      LAYER METAL3 ;
        RECT 1447.74 1223.201 1449.14 1226.001 ;
    END
  END n_OUTS<48>
  PIN n_OUTS<47>
    DIRECTION INOUT ;
    USE SIGNAL ;
    PORT
      LAYER METAL3 ;
        RECT 1451.52 1223.201 1452.92 1226.001 ;
    END
  END n_OUTS<47>
  PIN n_OUTS<46>
    DIRECTION INOUT ;
    USE SIGNAL ;
    PORT
      LAYER METAL3 ;
        RECT 1455.3 1223.201 1456.7 1226.001 ;
    END
  END n_OUTS<46>
  PIN n_OUTS<45>
    DIRECTION INOUT ;
    USE SIGNAL ;
    PORT
      LAYER METAL3 ;
        RECT 1459.08 1223.201 1460.48 1226.001 ;
    END
  END n_OUTS<45>
  PIN n_OUTS<44>
    DIRECTION INOUT ;
    USE SIGNAL ;
    PORT
      LAYER METAL3 ;
        RECT 1462.86 1223.201 1464.26 1226.001 ;
    END
  END n_OUTS<44>
  PIN n_OUTS<43>
    DIRECTION INOUT ;
    USE SIGNAL ;
    PORT
      LAYER METAL3 ;
        RECT 1466.64 1223.201 1468.04 1226.001 ;
    END
  END n_OUTS<43>
  PIN n_OUTS<42>
    DIRECTION INOUT ;
    USE SIGNAL ;
    PORT
      LAYER METAL3 ;
        RECT 1470.42 1223.201 1471.82 1226.001 ;
    END
  END n_OUTS<42>
  PIN n_OUTS<41>
    DIRECTION INOUT ;
    USE SIGNAL ;
    PORT
      LAYER METAL3 ;
        RECT 1474.2 1223.201 1475.6 1226.001 ;
    END
  END n_OUTS<41>
  PIN n_OUTS<40>
    DIRECTION INOUT ;
    USE SIGNAL ;
    PORT
      LAYER METAL3 ;
        RECT 1477.98 1223.201 1479.38 1226.001 ;
    END
  END n_OUTS<40>
  PIN n_OUTS<39>
    DIRECTION INOUT ;
    USE SIGNAL ;
    PORT
      LAYER METAL3 ;
        RECT 1481.76 1223.201 1483.16 1226.001 ;
    END
  END n_OUTS<39>
  PIN n_OUTS<38>
    DIRECTION INOUT ;
    USE SIGNAL ;
    PORT
      LAYER METAL3 ;
        RECT 1485.54 1223.201 1486.94 1226.001 ;
    END
  END n_OUTS<38>
  PIN n_OUTS<37>
    DIRECTION INOUT ;
    USE SIGNAL ;
    PORT
      LAYER METAL3 ;
        RECT 1489.32 1223.201 1490.72 1226.001 ;
    END
  END n_OUTS<37>
  PIN n_OUTS<36>
    DIRECTION INOUT ;
    USE SIGNAL ;
    PORT
      LAYER METAL3 ;
        RECT 1493.1 1223.201 1494.5 1226.001 ;
    END
  END n_OUTS<36>
  PIN n_OUTS<35>
    DIRECTION INOUT ;
    USE SIGNAL ;
    PORT
      LAYER METAL3 ;
        RECT 1496.88 1223.201 1498.28 1226.001 ;
    END
  END n_OUTS<35>
  PIN n_OUTS<34>
    DIRECTION INOUT ;
    USE SIGNAL ;
    PORT
      LAYER METAL3 ;
        RECT 1500.66 1223.201 1502.06 1226.001 ;
    END
  END n_OUTS<34>
  PIN n_OUTS<33>
    DIRECTION INOUT ;
    USE SIGNAL ;
    PORT
      LAYER METAL3 ;
        RECT 1504.44 1223.201 1505.84 1226.001 ;
    END
  END n_OUTS<33>
  PIN n_OUTS<32>
    DIRECTION INOUT ;
    USE SIGNAL ;
    PORT
      LAYER METAL3 ;
        RECT 1508.22 1223.201 1509.62 1226.001 ;
    END
  END n_OUTS<32>
  PIN n_OUTS<31>
    DIRECTION INOUT ;
    USE SIGNAL ;
    PORT
      LAYER METAL3 ;
        RECT 1512.0 1223.201 1513.4 1226.001 ;
    END
  END n_OUTS<31>
  PIN n_OUTS<30>
    DIRECTION INOUT ;
    USE SIGNAL ;
    PORT
      LAYER METAL3 ;
        RECT 1515.78 1223.201 1517.18 1226.001 ;
    END
  END n_OUTS<30>
  PIN n_OUTS<29>
    DIRECTION INOUT ;
    USE SIGNAL ;
    PORT
      LAYER METAL3 ;
        RECT 1519.56 1223.201 1520.96 1226.001 ;
    END
  END n_OUTS<29>
  PIN n_OUTS<28>
    DIRECTION INOUT ;
    USE SIGNAL ;
    PORT
      LAYER METAL3 ;
        RECT 1523.34 1223.201 1524.74 1226.001 ;
    END
  END n_OUTS<28>
  PIN n_OUTS<27>
    DIRECTION INOUT ;
    USE SIGNAL ;
    PORT
      LAYER METAL3 ;
        RECT 1527.12 1223.201 1528.52 1226.001 ;
    END
  END n_OUTS<27>
  PIN n_OUTS<26>
    DIRECTION INOUT ;
    USE SIGNAL ;
    PORT
      LAYER METAL3 ;
        RECT 1530.9 1223.201 1532.3 1226.001 ;
    END
  END n_OUTS<26>
  PIN n_OUTS<25>
    DIRECTION INOUT ;
    USE SIGNAL ;
    PORT
      LAYER METAL3 ;
        RECT 1534.68 1223.201 1536.08 1226.001 ;
    END
  END n_OUTS<25>
  PIN n_OUTS<24>
    DIRECTION INOUT ;
    USE SIGNAL ;
    PORT
      LAYER METAL3 ;
        RECT 1538.46 1223.201 1539.86 1226.001 ;
    END
  END n_OUTS<24>
  PIN n_OUTS<23>
    DIRECTION INOUT ;
    USE SIGNAL ;
    PORT
      LAYER METAL3 ;
        RECT 1542.24 1223.201 1543.64 1226.001 ;
    END
  END n_OUTS<23>
  PIN n_OUTS<22>
    DIRECTION INOUT ;
    USE SIGNAL ;
    PORT
      LAYER METAL3 ;
        RECT 1546.02 1223.201 1547.42 1226.001 ;
    END
  END n_OUTS<22>
  PIN n_OUTS<21>
    DIRECTION INOUT ;
    USE SIGNAL ;
    PORT
      LAYER METAL3 ;
        RECT 1549.8 1223.201 1551.2 1226.001 ;
    END
  END n_OUTS<21>
  PIN n_OUTS<20>
    DIRECTION INOUT ;
    USE SIGNAL ;
    PORT
      LAYER METAL3 ;
        RECT 1553.58 1223.201 1554.98 1226.001 ;
    END
  END n_OUTS<20>
  PIN n_OUTS<19>
    DIRECTION INOUT ;
    USE SIGNAL ;
    PORT
      LAYER METAL3 ;
        RECT 1557.36 1223.201 1558.76 1226.001 ;
    END
  END n_OUTS<19>
  PIN n_OUTS<18>
    DIRECTION INOUT ;
    USE SIGNAL ;
    PORT
      LAYER METAL3 ;
        RECT 1561.14 1223.201 1562.54 1226.001 ;
    END
  END n_OUTS<18>
  PIN n_OUTS<17>
    DIRECTION INOUT ;
    USE SIGNAL ;
    PORT
      LAYER METAL3 ;
        RECT 1564.92 1223.201 1566.32 1226.001 ;
    END
  END n_OUTS<17>
  PIN n_OUTS<16>
    DIRECTION INOUT ;
    USE SIGNAL ;
    PORT
      LAYER METAL3 ;
        RECT 1568.7 1223.201 1570.1 1226.001 ;
    END
  END n_OUTS<16>
  PIN n_OUTS<15>
    DIRECTION INOUT ;
    USE SIGNAL ;
    PORT
      LAYER METAL3 ;
        RECT 1572.48 1223.201 1573.88 1226.001 ;
    END
  END n_OUTS<15>
  PIN n_OUTS<14>
    DIRECTION INOUT ;
    USE SIGNAL ;
    PORT
      LAYER METAL3 ;
        RECT 1576.26 1223.201 1577.66 1226.001 ;
    END
  END n_OUTS<14>
  PIN n_OUTS<13>
    DIRECTION INOUT ;
    USE SIGNAL ;
    PORT
      LAYER METAL3 ;
        RECT 1580.04 1223.201 1581.44 1226.001 ;
    END
  END n_OUTS<13>
  PIN n_OUTS<12>
    DIRECTION INOUT ;
    USE SIGNAL ;
    PORT
      LAYER METAL3 ;
        RECT 1583.82 1223.201 1585.22 1226.001 ;
    END
  END n_OUTS<12>
  PIN n_OUTS<11>
    DIRECTION INOUT ;
    USE SIGNAL ;
    PORT
      LAYER METAL3 ;
        RECT 1587.6 1223.201 1589.0 1226.001 ;
    END
  END n_OUTS<11>
  PIN n_OUTS<10>
    DIRECTION INOUT ;
    USE SIGNAL ;
    PORT
      LAYER METAL3 ;
        RECT 1591.38 1223.201 1592.78 1226.001 ;
    END
  END n_OUTS<10>
  PIN n_OUTS<9>
    DIRECTION INOUT ;
    USE SIGNAL ;
    PORT
      LAYER METAL3 ;
        RECT 1595.16 1223.201 1596.56 1226.001 ;
    END
  END n_OUTS<9>
  PIN n_OUTS<8>
    DIRECTION INOUT ;
    USE SIGNAL ;
    PORT
      LAYER METAL3 ;
        RECT 1598.94 1223.201 1600.34 1226.001 ;
    END
  END n_OUTS<8>
  PIN n_OUTS<7>
    DIRECTION INOUT ;
    USE SIGNAL ;
    PORT
      LAYER METAL3 ;
        RECT 1602.72 1223.201 1604.12 1226.001 ;
    END
  END n_OUTS<7>
  PIN n_OUTS<6>
    DIRECTION INOUT ;
    USE SIGNAL ;
    PORT
      LAYER METAL3 ;
        RECT 1606.5 1223.201 1607.9 1226.001 ;
    END
  END n_OUTS<6>
  PIN n_OUTS<5>
    DIRECTION INOUT ;
    USE SIGNAL ;
    PORT
      LAYER METAL3 ;
        RECT 1610.28 1223.201 1611.68 1226.001 ;
    END
  END n_OUTS<5>
  PIN n_OUTS<4>
    DIRECTION INOUT ;
    USE SIGNAL ;
    PORT
      LAYER METAL3 ;
        RECT 1614.06 1223.201 1615.46 1226.001 ;
    END
  END n_OUTS<4>
  PIN n_OUTS<3>
    DIRECTION INOUT ;
    USE SIGNAL ;
    PORT
      LAYER METAL3 ;
        RECT 1617.84 1223.201 1619.24 1226.001 ;
    END
  END n_OUTS<3>
  PIN n_OUTS<2>
    DIRECTION INOUT ;
    USE SIGNAL ;
    PORT
      LAYER METAL3 ;
        RECT 1621.62 1223.201 1623.02 1226.001 ;
    END
  END n_OUTS<2>
  PIN n_OUTS<1>
    DIRECTION INOUT ;
    USE SIGNAL ;
    PORT
      LAYER METAL3 ;
        RECT 1625.4 1223.201 1626.8 1226.001 ;
    END
  END n_OUTS<1>
  PIN n_OUTS<0>
    DIRECTION INOUT ;
    USE SIGNAL ;
    PORT
      LAYER METAL3 ;
        RECT 1629.18 1223.201 1630.58 1226.001 ;
    END
  END n_OUTS<0>
  PIN n_GateB<4>
    DIRECTION INOUT ;
    USE SIGNAL ;
    PORT
      LAYER METAL3 ;
        RECT 1632.96 1223.201 1634.36 1226.001 ;
    END
  END n_GateB<4>
  PIN n_GateB<3>
    DIRECTION INOUT ;
    USE SIGNAL ;
    PORT
      LAYER METAL3 ;
        RECT 1636.74 1223.201 1638.14 1226.001 ;
    END
  END n_GateB<3>
  PIN n_GateB<2>
    DIRECTION INOUT ;
    USE SIGNAL ;
    PORT
      LAYER METAL3 ;
        RECT 1640.52 1223.201 1641.92 1226.001 ;
    END
  END n_GateB<2>
  PIN n_GateB<1>
    DIRECTION INOUT ;
    USE SIGNAL ;
    PORT
      LAYER METAL3 ;
        RECT 1644.3 1223.201 1645.7 1226.001 ;
    END
  END n_GateB<1>
  PIN n_GateB<0>
    DIRECTION INOUT ;
    USE SIGNAL ;
    PORT
      LAYER METAL3 ;
        RECT 1648.08 1223.201 1649.48 1226.001 ;
    END
  END n_GateB<0>
  PIN n_vinj
    DIRECTION INOUT ;
    USE SIGNAL ;
    PORT
      LAYER METAL3 ;
        RECT 11.36 1223.201 12.76 1226.001 ;
    END
  END n_vinj
  PIN n_gnd
    DIRECTION INOUT ;
    USE SIGNAL ;
    PORT
      LAYER METAL3 ;
        RECT 7.58 1223.201 8.98 1226.001 ;
    END
  END n_gnd
  PIN n_AVDD
    DIRECTION INOUT ;
    USE SIGNAL ;
    PORT
      LAYER METAL3 ;
        RECT 1651.86 1223.201 1653.26 1226.001 ;
    END
  END n_AVDD
  PIN n_VTUN
    DIRECTION INOUT ;
    USE SIGNAL ;
    PORT
      LAYER METAL3 ;
        RECT 1655.64 1223.201 1657.04 1226.001 ;
    END
  END n_VTUN
  PIN n_VGPROG
    DIRECTION INOUT ;
    USE SIGNAL ;
    PORT
      LAYER METAL3 ;
        RECT 1659.42 1223.201 1660.82 1226.001 ;
    END
  END n_VGPROG
  PIN n_VGRUN
    DIRECTION INOUT ;
    USE SIGNAL ;
    PORT
      LAYER METAL3 ;
        RECT 1663.2 1223.201 1664.6 1226.001 ;
    END
  END n_VGRUN
  PIN n_Run
    DIRECTION INOUT ;
    USE SIGNAL ;
    PORT
      LAYER METAL3 ;
        RECT 1666.98 1223.201 1668.38 1226.001 ;
    END
  END n_Run
  PIN n_Prog
    DIRECTION INOUT ;
    USE SIGNAL ;
    PORT
      LAYER METAL3 ;
        RECT 1670.76 1223.201 1672.16 1226.001 ;
    END
  END n_Prog
  PIN AVDD
    DIRECTION INOUT ;
    USE SIGNAL ;
    PORT
      LAYER METAL2 ;
        RECT 1650.99 1223.03 1651.89 1224.05 ;
    END
  END AVDD
END Delaylines_Flip

MACRO VMMWTA_FullRoute
  PIN GND<1>
    DIRECTION INOUT ;
    USE SIGNAL ;
    PORT
      LAYER METAL2 ;
        RECT 15.41 21.06 16.01 22.0 ;
    END
  END GND<1>
  PIN Vg<0>
    DIRECTION INOUT ;
    USE SIGNAL ;
    PORT
      LAYER METAL2 ;
        RECT 8.4 21.03 9.0 22.0 ;
    END
  END Vg<0>
  PIN GND<0>
    DIRECTION INOUT ;
    USE SIGNAL ;
    PORT
      LAYER METAL2 ;
        RECT 11.2 21.07 11.8 22.0 ;
    END
  END GND<0>
  PIN VINJ<0>
    DIRECTION INOUT ;
    USE SIGNAL ;
    PORT
      LAYER METAL2 ;
        RECT 4.2 21.18 4.8 22.0 ;
    END
  END VINJ<0>
  PIN VTUN
    DIRECTION INOUT ;
    USE SIGNAL ;
    PORT
      LAYER METAL2 ;
        RECT 13.3 21.09 13.9 22.0 ;
    END
  END VTUN
  PIN Vs<1>
    DIRECTION INOUT ;
    USE SIGNAL ;
    PORT
      LAYER METAL2 ;
        RECT 24.5 21.06 25.1 22.0 ;
    END
  END Vs<1>
  PIN Vs<0>
    DIRECTION INOUT ;
    USE SIGNAL ;
    PORT
      LAYER METAL2 ;
        RECT 2.1 21.21 2.7 22.0 ;
    END
  END Vs<0>
  PIN Vsel<0>
    DIRECTION INOUT ;
    USE SIGNAL ;
    PORT
      LAYER METAL2 ;
        RECT 6.3 21.2 6.9 22.0 ;
    END
  END Vsel<0>
  PIN VINJ<1>
    DIRECTION INOUT ;
    USE SIGNAL ;
    PORT
      LAYER METAL2 ;
        RECT 22.4 21.05 23.0 22.0 ;
    END
  END VINJ<1>
  PIN Vsel<1>
    DIRECTION INOUT ;
    USE SIGNAL ;
    PORT
      LAYER METAL2 ;
        RECT 20.3 21.08 20.9 22.0 ;
    END
  END Vsel<1>
  PIN Vg<1>
    DIRECTION INOUT ;
    USE SIGNAL ;
    PORT
      LAYER METAL2 ;
        RECT 18.2 21.06 18.8 22.0 ;
    END
  END Vg<1>
  PIN Vd_R<2>
    DIRECTION INOUT ;
    USE SIGNAL ;
    PORT
      LAYER METAL1 ;
        RECT 26.53 7.0 27.46 7.5 ;
    END
  END Vd_R<2>
  PIN Vd_R<0>
    DIRECTION INOUT ;
    USE SIGNAL ;
    PORT
      LAYER METAL1 ;
        RECT 26.66 17.5 27.46 18.0 ;
    END
  END Vd_R<0>
  PIN Vd_P<2>
    DIRECTION INOUT ;
    USE SIGNAL ;
    PORT
      LAYER METAL1 ;
        RECT 26.51 9.8 27.46 10.3 ;
    END
  END Vd_P<2>
  PIN Vd_P<1>
    DIRECTION INOUT ;
    USE SIGNAL ;
    PORT
      LAYER METAL1 ;
        RECT 26.38 11.9 27.46 12.4 ;
    END
  END Vd_P<1>
  PIN Vd_P<3>
    DIRECTION INOUT ;
    USE SIGNAL ;
    PORT
      LAYER METAL1 ;
        RECT 26.55 0.7 27.46 1.2 ;
    END
  END Vd_P<3>
  PIN Vd_R<3>
    DIRECTION INOUT ;
    USE SIGNAL ;
    PORT
      LAYER METAL1 ;
        RECT 26.5 3.5 27.46 4.0 ;
    END
  END Vd_R<3>
  PIN Vd_R<1>
    DIRECTION INOUT ;
    USE SIGNAL ;
    PORT
      LAYER METAL1 ;
        RECT 26.56 14.7 27.44 15.2 ;
    END
  END Vd_R<1>
  PIN Vd_P<0>
    DIRECTION INOUT ;
    USE SIGNAL ;
    PORT
      LAYER METAL1 ;
        RECT 26.63 20.3 27.46 20.8 ;
    END
  END Vd_P<0>
  PIN Vbias
    DIRECTION INOUT ;
    USE SIGNAL ;
    PORT
      LAYER METAL3 ;
        RECT 4152.0 1686.61 4153.4 1688.0 ;
    END
  END Vbias
  PIN Prog_WTA
    DIRECTION INOUT ;
    USE SIGNAL ;
    PORT
      LAYER METAL3 ;
        RECT 4072.19 1686.57 4073.59 1687.97 ;
    END
  END Prog_WTA
  PIN Vmid
    DIRECTION INOUT ;
    USE SIGNAL ;
    PORT
      LAYER METAL3 ;
        RECT 4147.83 1686.57 4149.23 1687.97 ;
    END
  END Vmid
  PIN w_DrainEnable_WTA
    DIRECTION INOUT ;
    USE SIGNAL ;
    PORT
      LAYER METAL3 ;
        RECT 0.0 1532.57 2.8 1533.97 ;
    END
  END w_DrainEnable_WTA
  PIN w_Drainline_Run
    DIRECTION INOUT ;
    USE SIGNAL ;
    PORT
      LAYER METAL3 ;
        RECT 0.0 1546.57 2.8 1547.97 ;
    END
  END w_Drainline_Run
  PIN w_Drainline_Prog
    DIRECTION INOUT ;
    USE SIGNAL ;
    PORT
      LAYER METAL3 ;
        RECT 0.0 1560.57 2.8 1561.97 ;
    END
  END w_Drainline_Prog
  PIN w_DrainB<7>
    DIRECTION INOUT ;
    USE SIGNAL ;
    PORT
      LAYER METAL3 ;
        RECT 0.0 1574.57 2.8 1575.97 ;
    END
  END w_DrainB<7>
  PIN w_DrainB<6>
    DIRECTION INOUT ;
    USE SIGNAL ;
    PORT
      LAYER METAL3 ;
        RECT 0.0 1588.57 2.8 1589.97 ;
    END
  END w_DrainB<6>
  PIN w_DrainB<5>
    DIRECTION INOUT ;
    USE SIGNAL ;
    PORT
      LAYER METAL3 ;
        RECT 0.0 1602.57 2.8 1603.97 ;
    END
  END w_DrainB<5>
  PIN w_DrainB<4>
    DIRECTION INOUT ;
    USE SIGNAL ;
    PORT
      LAYER METAL3 ;
        RECT 0.0 1616.57 2.8 1617.97 ;
    END
  END w_DrainB<4>
  PIN w_DrainB<3>
    DIRECTION INOUT ;
    USE SIGNAL ;
    PORT
      LAYER METAL3 ;
        RECT 0.0 1630.57 2.8 1631.97 ;
    END
  END w_DrainB<3>
  PIN w_DrainB<2>
    DIRECTION INOUT ;
    USE SIGNAL ;
    PORT
      LAYER METAL3 ;
        RECT 0.0 1644.57 2.8 1645.97 ;
    END
  END w_DrainB<2>
  PIN w_DrainB<1>
    DIRECTION INOUT ;
    USE SIGNAL ;
    PORT
      LAYER METAL3 ;
        RECT 0.0 1658.57 2.8 1659.97 ;
    END
  END w_DrainB<1>
  PIN w_DrainB<0>
    DIRECTION INOUT ;
    USE SIGNAL ;
    PORT
      LAYER METAL3 ;
        RECT 0.0 1672.57 2.8 1673.97 ;
    END
  END w_DrainB<0>
  PIN s_vinj
    DIRECTION INOUT ;
    USE SIGNAL ;
    PORT
      LAYER METAL3 ;
        RECT 4362.2 0.0 4363.6 2.8 ;
    END
  END s_vinj
  PIN s_gnd
    DIRECTION INOUT ;
    USE SIGNAL ;
    PORT
      LAYER METAL3 ;
        RECT 4376.2 0.0 4377.6 2.8 ;
    END
  END s_gnd
  PIN e_RSTBar
    DIRECTION INOUT ;
    USE SIGNAL ;
    PORT
      LAYER METAL3 ;
        RECT 4402.8 1630.57 4405.6 1631.97 ;
    END
  END e_RSTBar
  PIN e_CLK
    DIRECTION INOUT ;
    USE SIGNAL ;
    PORT
      LAYER METAL3 ;
        RECT 4402.8 1644.57 4405.6 1645.97 ;
    END
  END e_CLK
  PIN e_Din
    DIRECTION INOUT ;
    USE SIGNAL ;
    PORT
      LAYER METAL3 ;
        RECT 4402.8 1658.57 4405.6 1659.97 ;
    END
  END e_Din
  PIN e_WTA_out
    DIRECTION INOUT ;
    USE SIGNAL ;
    PORT
      LAYER METAL3 ;
        RECT 4402.8 1672.57 4405.6 1673.97 ;
    END
  END e_WTA_out
  PIN n_GateEnable_WTA
    DIRECTION INOUT ;
    USE SIGNAL ;
    PORT
      LAYER METAL3 ;
        RECT 209.3 1685.17 210.7 1687.97 ;
    END
  END n_GateEnable_WTA
  PIN n_GateB<8>
    DIRECTION INOUT ;
    USE SIGNAL ;
    PORT
      LAYER METAL3 ;
        RECT 195.3 1685.17 196.7 1687.97 ;
    END
  END n_GateB<8>
  PIN n_GateB<7>
    DIRECTION INOUT ;
    USE SIGNAL ;
    PORT
      LAYER METAL3 ;
        RECT 181.3 1685.17 182.7 1687.97 ;
    END
  END n_GateB<7>
  PIN n_GateB<6>
    DIRECTION INOUT ;
    USE SIGNAL ;
    PORT
      LAYER METAL3 ;
        RECT 167.3 1685.17 168.7 1687.97 ;
    END
  END n_GateB<6>
  PIN n_GateB<5>
    DIRECTION INOUT ;
    USE SIGNAL ;
    PORT
      LAYER METAL3 ;
        RECT 153.3 1685.17 154.7 1687.97 ;
    END
  END n_GateB<5>
  PIN n_GateB<4>
    DIRECTION INOUT ;
    USE SIGNAL ;
    PORT
      LAYER METAL3 ;
        RECT 139.3 1685.17 140.7 1687.97 ;
    END
  END n_GateB<4>
  PIN n_GateB<3>
    DIRECTION INOUT ;
    USE SIGNAL ;
    PORT
      LAYER METAL3 ;
        RECT 125.3 1685.17 126.7 1687.97 ;
    END
  END n_GateB<3>
  PIN n_GateB<2>
    DIRECTION INOUT ;
    USE SIGNAL ;
    PORT
      LAYER METAL3 ;
        RECT 111.3 1685.17 112.7 1687.97 ;
    END
  END n_GateB<2>
  PIN n_GateB<1>
    DIRECTION INOUT ;
    USE SIGNAL ;
    PORT
      LAYER METAL3 ;
        RECT 97.3 1685.17 98.7 1687.97 ;
    END
  END n_GateB<1>
  PIN n_GateB<0>
    DIRECTION INOUT ;
    USE SIGNAL ;
    PORT
      LAYER METAL3 ;
        RECT 83.3 1685.17 84.7 1687.97 ;
    END
  END n_GateB<0>
  PIN n_vinj
    DIRECTION INOUT ;
    USE SIGNAL ;
    PORT
      LAYER METAL3 ;
        RECT 4362.2 1685.17 4363.6 1687.97 ;
    END
  END n_vinj
  PIN n_gnd
    DIRECTION INOUT ;
    USE SIGNAL ;
    PORT
      LAYER METAL3 ;
        RECT 4376.2 1685.17 4377.6 1687.97 ;
    END
  END n_gnd
  PIN n_AVDD
    DIRECTION INOUT ;
    USE SIGNAL ;
    PORT
      LAYER METAL3 ;
        RECT 69.3 1685.17 70.7 1687.97 ;
    END
  END n_AVDD
  PIN n_VTUN
    DIRECTION INOUT ;
    USE SIGNAL ;
    PORT
      LAYER METAL3 ;
        RECT 55.3 1685.17 56.7 1687.97 ;
    END
  END n_VTUN
  PIN n_VGPROG
    DIRECTION INOUT ;
    USE SIGNAL ;
    PORT
      LAYER METAL3 ;
        RECT 41.3 1685.17 42.7 1687.97 ;
    END
  END n_VGPROG
  PIN n_Run
    DIRECTION INOUT ;
    USE SIGNAL ;
    PORT
      LAYER METAL3 ;
        RECT 27.3 1685.17 28.7 1687.97 ;
    END
  END n_Run
  PIN n_Prog
    DIRECTION INOUT ;
    USE SIGNAL ;
    PORT
      LAYER METAL3 ;
        RECT 13.3 1685.17 14.7 1687.97 ;
    END
  END n_Prog
END VMMWTA_FullRoute

MACRO Modulation_Flip
  PIN In<0>
    DIRECTION INOUT ;
    USE SIGNAL ;
    PORT
      LAYER METAL1 ;
        RECT 0.0 17.5 0.27 18.0 ;
    END
  END In<0>
  PIN In<1>
    DIRECTION INOUT ;
    USE SIGNAL ;
    PORT
      LAYER METAL1 ;
        RECT 0.0 14.7 0.38 15.2 ;
    END
  END In<1>
  PIN In<2>
    DIRECTION INOUT ;
    USE SIGNAL ;
    PORT
      LAYER METAL1 ;
        RECT 0.0 7.0 0.36 7.5 ;
    END
  END In<2>
  PIN In<3>
    DIRECTION INOUT ;
    USE SIGNAL ;
    PORT
      LAYER METAL1 ;
        RECT 0.0 3.5 0.3 4.0 ;
    END
  END In<3>
  PIN A<0>
    DIRECTION INOUT ;
    USE SIGNAL ;
    PORT
      LAYER METAL1 ;
        RECT 10.6 17.6 12.0 18.9 ;
    END
  END A<0>
  PIN A<1>
    DIRECTION INOUT ;
    USE SIGNAL ;
    PORT
      LAYER METAL1 ;
        RECT 10.6 14.9 12.0 16.2 ;
    END
  END A<1>
  PIN A<2>
    DIRECTION INOUT ;
    USE SIGNAL ;
    PORT
      LAYER METAL1 ;
        RECT 10.6 6.8 12.0 8.1 ;
    END
  END A<2>
  PIN A<3>
    DIRECTION INOUT ;
    USE SIGNAL ;
    PORT
      LAYER METAL1 ;
        RECT 10.6 4.1 12.0 5.4 ;
    END
  END A<3>
  PIN P<0>
    DIRECTION INOUT ;
    USE SIGNAL ;
    PORT
      LAYER METAL1 ;
        RECT 10.6 20.3 12.0 21.6 ;
    END
  END P<0>
  PIN P<1>
    DIRECTION INOUT ;
    USE SIGNAL ;
    PORT
      LAYER METAL1 ;
        RECT 10.6 12.2 12.0 13.5 ;
    END
  END P<1>
  PIN P<2>
    DIRECTION INOUT ;
    USE SIGNAL ;
    PORT
      LAYER METAL1 ;
        RECT 10.6 9.5 12.0 10.8 ;
    END
  END P<2>
  PIN P<3>
    DIRECTION INOUT ;
    USE SIGNAL ;
    PORT
      LAYER METAL1 ;
        RECT 10.6 1.4 12.0 2.7 ;
    END
  END P<3>
  PIN GND_b
    DIRECTION INOUT ;
    USE SIGNAL ;
    PORT
      LAYER METAL2 ;
        RECT 6.35 0.0 7.25 0.88 ;
    END
  END GND_b
  PIN Prog_b
    DIRECTION INOUT ;
    USE SIGNAL ;
    PORT
      LAYER METAL2 ;
        RECT 4.1 0.0 4.7 0.78 ;
    END
  END Prog_b
  PIN VDD_b
    DIRECTION INOUT ;
    USE SIGNAL ;
    PORT
      LAYER METAL2 ;
        RECT 1.81 0.0 2.71 0.71 ;
    END
  END VDD_b
  PIN Prog
    DIRECTION INOUT ;
    USE SIGNAL ;
    PORT
      LAYER METAL2 ;
        RECT 4.1 21.3 4.7 22.0 ;
    END
  END Prog
  PIN VDD
    DIRECTION INOUT ;
    USE SIGNAL ;
    PORT
      LAYER METAL2 ;
        RECT 1.81 21.3 2.71 22.0 ;
    END
  END VDD
  PIN GND
    DIRECTION INOUT ;
    USE SIGNAL ;
    PORT
      LAYER METAL2 ;
        RECT 6.35 21.3 7.25 22.0 ;
    END
  END GND
  PIN VOUT<267>
    DIRECTION INOUT ;
    USE SIGNAL ;
    PORT
      LAYER METAL3 ;
        RECT 0.0 1694.17 1.4 1695.57 ;
    END
  END VOUT<267>
  PIN VOUT<251>
    DIRECTION INOUT ;
    USE SIGNAL ;
    PORT
      LAYER METAL3 ;
        RECT 0.0 1606.17 1.4 1607.57 ;
    END
  END VOUT<251>
  PIN VOUT<235>
    DIRECTION INOUT ;
    USE SIGNAL ;
    PORT
      LAYER METAL3 ;
        RECT 0.0 1518.17 1.4 1519.57 ;
    END
  END VOUT<235>
  PIN VOUT<219>
    DIRECTION INOUT ;
    USE SIGNAL ;
    PORT
      LAYER METAL3 ;
        RECT 0.0 1430.17 1.4 1431.57 ;
    END
  END VOUT<219>
  PIN VOUT<203>
    DIRECTION INOUT ;
    USE SIGNAL ;
    PORT
      LAYER METAL3 ;
        RECT 0.0 1342.17 1.4 1343.57 ;
    END
  END VOUT<203>
  PIN VOUT<187>
    DIRECTION INOUT ;
    USE SIGNAL ;
    PORT
      LAYER METAL3 ;
        RECT 0.0 1254.17 1.4 1255.57 ;
    END
  END VOUT<187>
  PIN VOUT<171>
    DIRECTION INOUT ;
    USE SIGNAL ;
    PORT
      LAYER METAL3 ;
        RECT 0.0 1166.17 1.4 1167.57 ;
    END
  END VOUT<171>
  PIN VOUT<155>
    DIRECTION INOUT ;
    USE SIGNAL ;
    PORT
      LAYER METAL3 ;
        RECT 0.0 1078.17 1.4 1079.57 ;
    END
  END VOUT<155>
  PIN VOUT<139>
    DIRECTION INOUT ;
    USE SIGNAL ;
    PORT
      LAYER METAL3 ;
        RECT 0.0 990.17 1.4 991.57 ;
    END
  END VOUT<139>
  PIN VOUT<123>
    DIRECTION INOUT ;
    USE SIGNAL ;
    PORT
      LAYER METAL3 ;
        RECT 0.0 902.17 1.4 903.57 ;
    END
  END VOUT<123>
  PIN VOUT<107>
    DIRECTION INOUT ;
    USE SIGNAL ;
    PORT
      LAYER METAL3 ;
        RECT 0.0 814.17 1.4 815.57 ;
    END
  END VOUT<107>
  PIN VOUT<91>
    DIRECTION INOUT ;
    USE SIGNAL ;
    PORT
      LAYER METAL3 ;
        RECT 0.0 726.17 1.4 727.57 ;
    END
  END VOUT<91>
  PIN VOUT<75>
    DIRECTION INOUT ;
    USE SIGNAL ;
    PORT
      LAYER METAL3 ;
        RECT 0.0 638.17 1.4 639.57 ;
    END
  END VOUT<75>
  PIN VOUT<59>
    DIRECTION INOUT ;
    USE SIGNAL ;
    PORT
      LAYER METAL3 ;
        RECT 0.0 550.17 1.4 551.57 ;
    END
  END VOUT<59>
  PIN VOUT<43>
    DIRECTION INOUT ;
    USE SIGNAL ;
    PORT
      LAYER METAL3 ;
        RECT 0.0 462.17 1.4 463.57 ;
    END
  END VOUT<43>
  PIN VOUT<27>
    DIRECTION INOUT ;
    USE SIGNAL ;
    PORT
      LAYER METAL3 ;
        RECT 0.0 374.17 1.4 375.57 ;
    END
  END VOUT<27>
  PIN VOUT<11>
    DIRECTION INOUT ;
    USE SIGNAL ;
    PORT
      LAYER METAL3 ;
        RECT 0.0 286.17 1.4 287.57 ;
    END
  END VOUT<11>
  PIN VOUT<274>
    DIRECTION INOUT ;
    USE SIGNAL ;
    PORT
      LAYER METAL3 ;
        RECT 0.0 1735.37 1.4 1736.77 ;
    END
  END VOUT<274>
  PIN VOUT<258>
    DIRECTION INOUT ;
    USE SIGNAL ;
    PORT
      LAYER METAL3 ;
        RECT 0.0 1647.37 1.4 1648.77 ;
    END
  END VOUT<258>
  PIN VOUT<242>
    DIRECTION INOUT ;
    USE SIGNAL ;
    PORT
      LAYER METAL3 ;
        RECT 0.0 1559.37 1.4 1560.77 ;
    END
  END VOUT<242>
  PIN VOUT<226>
    DIRECTION INOUT ;
    USE SIGNAL ;
    PORT
      LAYER METAL3 ;
        RECT 0.0 1471.37 1.4 1472.77 ;
    END
  END VOUT<226>
  PIN VOUT<210>
    DIRECTION INOUT ;
    USE SIGNAL ;
    PORT
      LAYER METAL3 ;
        RECT 0.0 1383.37 1.4 1384.77 ;
    END
  END VOUT<210>
  PIN VOUT<194>
    DIRECTION INOUT ;
    USE SIGNAL ;
    PORT
      LAYER METAL3 ;
        RECT 0.0 1295.37 1.4 1296.77 ;
    END
  END VOUT<194>
  PIN VOUT<178>
    DIRECTION INOUT ;
    USE SIGNAL ;
    PORT
      LAYER METAL3 ;
        RECT 0.0 1207.37 1.4 1208.77 ;
    END
  END VOUT<178>
  PIN VOUT<162>
    DIRECTION INOUT ;
    USE SIGNAL ;
    PORT
      LAYER METAL3 ;
        RECT 0.0 1119.37 1.4 1120.77 ;
    END
  END VOUT<162>
  PIN VOUT<146>
    DIRECTION INOUT ;
    USE SIGNAL ;
    PORT
      LAYER METAL3 ;
        RECT 0.0 1031.37 1.4 1032.77 ;
    END
  END VOUT<146>
  PIN VOUT<130>
    DIRECTION INOUT ;
    USE SIGNAL ;
    PORT
      LAYER METAL3 ;
        RECT 0.0 943.37 1.4 944.77 ;
    END
  END VOUT<130>
  PIN VOUT<114>
    DIRECTION INOUT ;
    USE SIGNAL ;
    PORT
      LAYER METAL3 ;
        RECT 0.0 855.37 1.4 856.77 ;
    END
  END VOUT<114>
  PIN VOUT<98>
    DIRECTION INOUT ;
    USE SIGNAL ;
    PORT
      LAYER METAL3 ;
        RECT 0.0 767.37 1.4 768.77 ;
    END
  END VOUT<98>
  PIN VOUT<82>
    DIRECTION INOUT ;
    USE SIGNAL ;
    PORT
      LAYER METAL3 ;
        RECT 0.0 679.37 1.4 680.77 ;
    END
  END VOUT<82>
  PIN VOUT<66>
    DIRECTION INOUT ;
    USE SIGNAL ;
    PORT
      LAYER METAL3 ;
        RECT 0.0 591.37 1.4 592.77 ;
    END
  END VOUT<66>
  PIN VOUT<50>
    DIRECTION INOUT ;
    USE SIGNAL ;
    PORT
      LAYER METAL3 ;
        RECT 0.0 503.37 1.4 504.77 ;
    END
  END VOUT<50>
  PIN VOUT<34>
    DIRECTION INOUT ;
    USE SIGNAL ;
    PORT
      LAYER METAL3 ;
        RECT 0.0 415.37 1.4 416.77 ;
    END
  END VOUT<34>
  PIN VOUT<18>
    DIRECTION INOUT ;
    USE SIGNAL ;
    PORT
      LAYER METAL3 ;
        RECT 0.0 327.37 1.4 328.77 ;
    END
  END VOUT<18>
  PIN VOUT<2>
    DIRECTION INOUT ;
    USE SIGNAL ;
    PORT
      LAYER METAL3 ;
        RECT 0.0 239.37 1.4 240.77 ;
    END
  END VOUT<2>
  PIN VOUT<265>
    DIRECTION INOUT ;
    USE SIGNAL ;
    PORT
      LAYER METAL3 ;
        RECT 0.0 1687.17 1.4 1688.57 ;
    END
  END VOUT<265>
  PIN VOUT<249>
    DIRECTION INOUT ;
    USE SIGNAL ;
    PORT
      LAYER METAL3 ;
        RECT 0.0 1599.17 1.4 1600.57 ;
    END
  END VOUT<249>
  PIN VOUT<233>
    DIRECTION INOUT ;
    USE SIGNAL ;
    PORT
      LAYER METAL3 ;
        RECT 0.0 1511.17 1.4 1512.57 ;
    END
  END VOUT<233>
  PIN VOUT<217>
    DIRECTION INOUT ;
    USE SIGNAL ;
    PORT
      LAYER METAL3 ;
        RECT 0.0 1423.17 1.4 1424.57 ;
    END
  END VOUT<217>
  PIN VOUT<201>
    DIRECTION INOUT ;
    USE SIGNAL ;
    PORT
      LAYER METAL3 ;
        RECT 0.0 1335.17 1.4 1336.57 ;
    END
  END VOUT<201>
  PIN VOUT<185>
    DIRECTION INOUT ;
    USE SIGNAL ;
    PORT
      LAYER METAL3 ;
        RECT 0.0 1247.17 1.4 1248.57 ;
    END
  END VOUT<185>
  PIN VOUT<169>
    DIRECTION INOUT ;
    USE SIGNAL ;
    PORT
      LAYER METAL3 ;
        RECT 0.0 1159.17 1.4 1160.57 ;
    END
  END VOUT<169>
  PIN VOUT<153>
    DIRECTION INOUT ;
    USE SIGNAL ;
    PORT
      LAYER METAL3 ;
        RECT 0.0 1071.17 1.4 1072.57 ;
    END
  END VOUT<153>
  PIN VOUT<279>
    DIRECTION INOUT ;
    USE SIGNAL ;
    PORT
      LAYER METAL3 ;
        RECT 0.0 1760.17 1.4 1761.57 ;
    END
  END VOUT<279>
  PIN VOUT<263>
    DIRECTION INOUT ;
    USE SIGNAL ;
    PORT
      LAYER METAL3 ;
        RECT 0.0 1672.17 1.4 1673.57 ;
    END
  END VOUT<263>
  PIN VOUT<247>
    DIRECTION INOUT ;
    USE SIGNAL ;
    PORT
      LAYER METAL3 ;
        RECT 0.0 1584.17 1.4 1585.57 ;
    END
  END VOUT<247>
  PIN VOUT<231>
    DIRECTION INOUT ;
    USE SIGNAL ;
    PORT
      LAYER METAL3 ;
        RECT 0.0 1496.17 1.4 1497.57 ;
    END
  END VOUT<231>
  PIN VOUT<215>
    DIRECTION INOUT ;
    USE SIGNAL ;
    PORT
      LAYER METAL3 ;
        RECT 0.0 1408.17 1.4 1409.57 ;
    END
  END VOUT<215>
  PIN VOUT<199>
    DIRECTION INOUT ;
    USE SIGNAL ;
    PORT
      LAYER METAL3 ;
        RECT 0.0 1320.17 1.4 1321.57 ;
    END
  END VOUT<199>
  PIN VOUT<183>
    DIRECTION INOUT ;
    USE SIGNAL ;
    PORT
      LAYER METAL3 ;
        RECT 0.0 1232.17 1.4 1233.57 ;
    END
  END VOUT<183>
  PIN VOUT<167>
    DIRECTION INOUT ;
    USE SIGNAL ;
    PORT
      LAYER METAL3 ;
        RECT 0.0 1144.17 1.4 1145.57 ;
    END
  END VOUT<167>
  PIN VOUT<151>
    DIRECTION INOUT ;
    USE SIGNAL ;
    PORT
      LAYER METAL3 ;
        RECT 0.0 1056.17 1.4 1057.57 ;
    END
  END VOUT<151>
  PIN VOUT<135>
    DIRECTION INOUT ;
    USE SIGNAL ;
    PORT
      LAYER METAL3 ;
        RECT 0.0 968.17 1.4 969.57 ;
    END
  END VOUT<135>
  PIN VOUT<119>
    DIRECTION INOUT ;
    USE SIGNAL ;
    PORT
      LAYER METAL3 ;
        RECT 0.0 880.17 1.4 881.57 ;
    END
  END VOUT<119>
  PIN VOUT<103>
    DIRECTION INOUT ;
    USE SIGNAL ;
    PORT
      LAYER METAL3 ;
        RECT 0.0 792.17 1.4 793.57 ;
    END
  END VOUT<103>
  PIN VOUT<87>
    DIRECTION INOUT ;
    USE SIGNAL ;
    PORT
      LAYER METAL3 ;
        RECT 0.0 704.17 1.4 705.57 ;
    END
  END VOUT<87>
  PIN VOUT<71>
    DIRECTION INOUT ;
    USE SIGNAL ;
    PORT
      LAYER METAL3 ;
        RECT 0.0 616.17 1.4 617.57 ;
    END
  END VOUT<71>
  PIN VOUT<55>
    DIRECTION INOUT ;
    USE SIGNAL ;
    PORT
      LAYER METAL3 ;
        RECT 0.0 528.17 1.4 529.57 ;
    END
  END VOUT<55>
  PIN VOUT<39>
    DIRECTION INOUT ;
    USE SIGNAL ;
    PORT
      LAYER METAL3 ;
        RECT 0.0 440.17 1.4 441.57 ;
    END
  END VOUT<39>
  PIN VOUT<23>
    DIRECTION INOUT ;
    USE SIGNAL ;
    PORT
      LAYER METAL3 ;
        RECT 0.0 352.17 1.4 353.57 ;
    END
  END VOUT<23>
  PIN VOUT<7>
    DIRECTION INOUT ;
    USE SIGNAL ;
    PORT
      LAYER METAL3 ;
        RECT 0.0 264.17 1.4 265.57 ;
    END
  END VOUT<7>
  PIN VOUT<270>
    DIRECTION INOUT ;
    USE SIGNAL ;
    PORT
      LAYER METAL3 ;
        RECT 0.0 1713.37 1.4 1714.77 ;
    END
  END VOUT<270>
  PIN VOUT<254>
    DIRECTION INOUT ;
    USE SIGNAL ;
    PORT
      LAYER METAL3 ;
        RECT 0.0 1625.37 1.4 1626.77 ;
    END
  END VOUT<254>
  PIN VOUT<238>
    DIRECTION INOUT ;
    USE SIGNAL ;
    PORT
      LAYER METAL3 ;
        RECT 0.0 1537.37 1.4 1538.77 ;
    END
  END VOUT<238>
  PIN VOUT<222>
    DIRECTION INOUT ;
    USE SIGNAL ;
    PORT
      LAYER METAL3 ;
        RECT 0.0 1449.37 1.4 1450.77 ;
    END
  END VOUT<222>
  PIN VOUT<206>
    DIRECTION INOUT ;
    USE SIGNAL ;
    PORT
      LAYER METAL3 ;
        RECT 0.0 1361.37 1.4 1362.77 ;
    END
  END VOUT<206>
  PIN VOUT<190>
    DIRECTION INOUT ;
    USE SIGNAL ;
    PORT
      LAYER METAL3 ;
        RECT 0.0 1273.37 1.4 1274.77 ;
    END
  END VOUT<190>
  PIN VOUT<174>
    DIRECTION INOUT ;
    USE SIGNAL ;
    PORT
      LAYER METAL3 ;
        RECT 0.0 1185.37 1.4 1186.77 ;
    END
  END VOUT<174>
  PIN VOUT<158>
    DIRECTION INOUT ;
    USE SIGNAL ;
    PORT
      LAYER METAL3 ;
        RECT 0.0 1097.37 1.4 1098.77 ;
    END
  END VOUT<158>
  PIN VOUT<142>
    DIRECTION INOUT ;
    USE SIGNAL ;
    PORT
      LAYER METAL3 ;
        RECT 0.0 1009.37 1.4 1010.77 ;
    END
  END VOUT<142>
  PIN VOUT<126>
    DIRECTION INOUT ;
    USE SIGNAL ;
    PORT
      LAYER METAL3 ;
        RECT 0.0 921.37 1.4 922.77 ;
    END
  END VOUT<126>
  PIN VOUT<110>
    DIRECTION INOUT ;
    USE SIGNAL ;
    PORT
      LAYER METAL3 ;
        RECT 0.0 833.37 1.4 834.77 ;
    END
  END VOUT<110>
  PIN VOUT<94>
    DIRECTION INOUT ;
    USE SIGNAL ;
    PORT
      LAYER METAL3 ;
        RECT 0.0 745.37 1.4 746.77 ;
    END
  END VOUT<94>
  PIN VOUT<78>
    DIRECTION INOUT ;
    USE SIGNAL ;
    PORT
      LAYER METAL3 ;
        RECT 0.0 657.37 1.4 658.77 ;
    END
  END VOUT<78>
  PIN VOUT<62>
    DIRECTION INOUT ;
    USE SIGNAL ;
    PORT
      LAYER METAL3 ;
        RECT 0.0 569.37 1.4 570.77 ;
    END
  END VOUT<62>
  PIN VOUT<46>
    DIRECTION INOUT ;
    USE SIGNAL ;
    PORT
      LAYER METAL3 ;
        RECT 0.0 481.37 1.4 482.77 ;
    END
  END VOUT<46>
  PIN VOUT<30>
    DIRECTION INOUT ;
    USE SIGNAL ;
    PORT
      LAYER METAL3 ;
        RECT 0.0 393.37 1.4 394.77 ;
    END
  END VOUT<30>
  PIN VOUT<14>
    DIRECTION INOUT ;
    USE SIGNAL ;
    PORT
      LAYER METAL3 ;
        RECT 0.0 305.37 1.4 306.77 ;
    END
  END VOUT<14>
  PIN VOUT<277>
    DIRECTION INOUT ;
    USE SIGNAL ;
    PORT
      LAYER METAL3 ;
        RECT 0.0 1753.17 1.4 1754.57 ;
    END
  END VOUT<277>
  PIN VOUT<261>
    DIRECTION INOUT ;
    USE SIGNAL ;
    PORT
      LAYER METAL3 ;
        RECT 0.0 1665.17 1.4 1666.57 ;
    END
  END VOUT<261>
  PIN VOUT<245>
    DIRECTION INOUT ;
    USE SIGNAL ;
    PORT
      LAYER METAL3 ;
        RECT 0.0 1577.17 1.4 1578.57 ;
    END
  END VOUT<245>
  PIN VOUT<229>
    DIRECTION INOUT ;
    USE SIGNAL ;
    PORT
      LAYER METAL3 ;
        RECT 0.0 1489.17 1.4 1490.57 ;
    END
  END VOUT<229>
  PIN VOUT<213>
    DIRECTION INOUT ;
    USE SIGNAL ;
    PORT
      LAYER METAL3 ;
        RECT 0.0 1401.17 1.4 1402.57 ;
    END
  END VOUT<213>
  PIN VOUT<197>
    DIRECTION INOUT ;
    USE SIGNAL ;
    PORT
      LAYER METAL3 ;
        RECT 0.0 1313.17 1.4 1314.57 ;
    END
  END VOUT<197>
  PIN VOUT<181>
    DIRECTION INOUT ;
    USE SIGNAL ;
    PORT
      LAYER METAL3 ;
        RECT 0.0 1225.17 1.4 1226.57 ;
    END
  END VOUT<181>
  PIN VOUT<165>
    DIRECTION INOUT ;
    USE SIGNAL ;
    PORT
      LAYER METAL3 ;
        RECT 0.0 1137.17 1.4 1138.57 ;
    END
  END VOUT<165>
  PIN VOUT<149>
    DIRECTION INOUT ;
    USE SIGNAL ;
    PORT
      LAYER METAL3 ;
        RECT 0.0 1049.17 1.4 1050.57 ;
    END
  END VOUT<149>
  PIN VOUT<144>
    DIRECTION INOUT ;
    USE SIGNAL ;
    PORT
      LAYER METAL3 ;
        RECT 0.0 1024.45 1.4 1025.85 ;
    END
  END VOUT<144>
  PIN VOUT<140>
    DIRECTION INOUT ;
    USE SIGNAL ;
    PORT
      LAYER METAL3 ;
        RECT 0.0 1002.45 1.4 1003.85 ;
    END
  END VOUT<140>
  PIN VOUT<136>
    DIRECTION INOUT ;
    USE SIGNAL ;
    PORT
      LAYER METAL3 ;
        RECT 0.0 980.45 1.4 981.85 ;
    END
  END VOUT<136>
  PIN VOUT<132>
    DIRECTION INOUT ;
    USE SIGNAL ;
    PORT
      LAYER METAL3 ;
        RECT 0.0 958.45 1.4 959.85 ;
    END
  END VOUT<132>
  PIN VOUT<128>
    DIRECTION INOUT ;
    USE SIGNAL ;
    PORT
      LAYER METAL3 ;
        RECT 0.0 936.45 1.4 937.85 ;
    END
  END VOUT<128>
  PIN VOUT<124>
    DIRECTION INOUT ;
    USE SIGNAL ;
    PORT
      LAYER METAL3 ;
        RECT 0.0 914.45 1.4 915.85 ;
    END
  END VOUT<124>
  PIN VOUT<120>
    DIRECTION INOUT ;
    USE SIGNAL ;
    PORT
      LAYER METAL3 ;
        RECT 0.0 892.45 1.4 893.85 ;
    END
  END VOUT<120>
  PIN VOUT<116>
    DIRECTION INOUT ;
    USE SIGNAL ;
    PORT
      LAYER METAL3 ;
        RECT 0.0 870.45 1.4 871.85 ;
    END
  END VOUT<116>
  PIN VOUT<112>
    DIRECTION INOUT ;
    USE SIGNAL ;
    PORT
      LAYER METAL3 ;
        RECT 0.0 848.45 1.4 849.85 ;
    END
  END VOUT<112>
  PIN VOUT<108>
    DIRECTION INOUT ;
    USE SIGNAL ;
    PORT
      LAYER METAL3 ;
        RECT 0.0 826.45 1.4 827.85 ;
    END
  END VOUT<108>
  PIN VOUT<104>
    DIRECTION INOUT ;
    USE SIGNAL ;
    PORT
      LAYER METAL3 ;
        RECT 0.0 804.45 1.4 805.85 ;
    END
  END VOUT<104>
  PIN VOUT<100>
    DIRECTION INOUT ;
    USE SIGNAL ;
    PORT
      LAYER METAL3 ;
        RECT 0.0 782.45 1.4 783.85 ;
    END
  END VOUT<100>
  PIN VOUT<96>
    DIRECTION INOUT ;
    USE SIGNAL ;
    PORT
      LAYER METAL3 ;
        RECT 0.0 760.45 1.4 761.85 ;
    END
  END VOUT<96>
  PIN VOUT<92>
    DIRECTION INOUT ;
    USE SIGNAL ;
    PORT
      LAYER METAL3 ;
        RECT 0.0 738.45 1.4 739.85 ;
    END
  END VOUT<92>
  PIN VOUT<88>
    DIRECTION INOUT ;
    USE SIGNAL ;
    PORT
      LAYER METAL3 ;
        RECT 0.0 716.45 1.4 717.85 ;
    END
  END VOUT<88>
  PIN VOUT<84>
    DIRECTION INOUT ;
    USE SIGNAL ;
    PORT
      LAYER METAL3 ;
        RECT 0.0 694.45 1.4 695.85 ;
    END
  END VOUT<84>
  PIN VOUT<80>
    DIRECTION INOUT ;
    USE SIGNAL ;
    PORT
      LAYER METAL3 ;
        RECT 0.0 672.45 1.4 673.85 ;
    END
  END VOUT<80>
  PIN VOUT<76>
    DIRECTION INOUT ;
    USE SIGNAL ;
    PORT
      LAYER METAL3 ;
        RECT 0.0 650.45 1.4 651.85 ;
    END
  END VOUT<76>
  PIN VOUT<72>
    DIRECTION INOUT ;
    USE SIGNAL ;
    PORT
      LAYER METAL3 ;
        RECT 0.0 628.45 1.4 629.85 ;
    END
  END VOUT<72>
  PIN VOUT<68>
    DIRECTION INOUT ;
    USE SIGNAL ;
    PORT
      LAYER METAL3 ;
        RECT 0.0 606.45 1.4 607.85 ;
    END
  END VOUT<68>
  PIN VOUT<64>
    DIRECTION INOUT ;
    USE SIGNAL ;
    PORT
      LAYER METAL3 ;
        RECT 0.0 584.45 1.4 585.85 ;
    END
  END VOUT<64>
  PIN VOUT<60>
    DIRECTION INOUT ;
    USE SIGNAL ;
    PORT
      LAYER METAL3 ;
        RECT 0.0 562.45 1.4 563.85 ;
    END
  END VOUT<60>
  PIN VOUT<56>
    DIRECTION INOUT ;
    USE SIGNAL ;
    PORT
      LAYER METAL3 ;
        RECT 0.0 540.45 1.4 541.85 ;
    END
  END VOUT<56>
  PIN VOUT<52>
    DIRECTION INOUT ;
    USE SIGNAL ;
    PORT
      LAYER METAL3 ;
        RECT 0.0 518.45 1.4 519.85 ;
    END
  END VOUT<52>
  PIN VOUT<48>
    DIRECTION INOUT ;
    USE SIGNAL ;
    PORT
      LAYER METAL3 ;
        RECT 0.0 496.45 1.4 497.85 ;
    END
  END VOUT<48>
  PIN VOUT<44>
    DIRECTION INOUT ;
    USE SIGNAL ;
    PORT
      LAYER METAL3 ;
        RECT 0.0 474.45 1.4 475.85 ;
    END
  END VOUT<44>
  PIN VOUT<40>
    DIRECTION INOUT ;
    USE SIGNAL ;
    PORT
      LAYER METAL3 ;
        RECT 0.0 452.45 1.4 453.85 ;
    END
  END VOUT<40>
  PIN VOUT<36>
    DIRECTION INOUT ;
    USE SIGNAL ;
    PORT
      LAYER METAL3 ;
        RECT 0.0 430.45 1.4 431.85 ;
    END
  END VOUT<36>
  PIN VOUT<137>
    DIRECTION INOUT ;
    USE SIGNAL ;
    PORT
      LAYER METAL3 ;
        RECT 0.0 983.17 1.4 984.57 ;
    END
  END VOUT<137>
  PIN VOUT<133>
    DIRECTION INOUT ;
    USE SIGNAL ;
    PORT
      LAYER METAL3 ;
        RECT 0.0 961.17 1.4 962.57 ;
    END
  END VOUT<133>
  PIN VOUT<129>
    DIRECTION INOUT ;
    USE SIGNAL ;
    PORT
      LAYER METAL3 ;
        RECT 0.0 939.17 1.4 940.57 ;
    END
  END VOUT<129>
  PIN VOUT<125>
    DIRECTION INOUT ;
    USE SIGNAL ;
    PORT
      LAYER METAL3 ;
        RECT 0.0 917.17 1.4 918.57 ;
    END
  END VOUT<125>
  PIN VOUT<121>
    DIRECTION INOUT ;
    USE SIGNAL ;
    PORT
      LAYER METAL3 ;
        RECT 0.0 895.17 1.4 896.57 ;
    END
  END VOUT<121>
  PIN VOUT<117>
    DIRECTION INOUT ;
    USE SIGNAL ;
    PORT
      LAYER METAL3 ;
        RECT 0.0 873.17 1.4 874.57 ;
    END
  END VOUT<117>
  PIN VOUT<113>
    DIRECTION INOUT ;
    USE SIGNAL ;
    PORT
      LAYER METAL3 ;
        RECT 0.0 851.17 1.4 852.57 ;
    END
  END VOUT<113>
  PIN VOUT<109>
    DIRECTION INOUT ;
    USE SIGNAL ;
    PORT
      LAYER METAL3 ;
        RECT 0.0 829.17 1.4 830.57 ;
    END
  END VOUT<109>
  PIN VOUT<105>
    DIRECTION INOUT ;
    USE SIGNAL ;
    PORT
      LAYER METAL3 ;
        RECT 0.0 807.17 1.4 808.57 ;
    END
  END VOUT<105>
  PIN VOUT<101>
    DIRECTION INOUT ;
    USE SIGNAL ;
    PORT
      LAYER METAL3 ;
        RECT 0.0 785.17 1.4 786.57 ;
    END
  END VOUT<101>
  PIN VOUT<97>
    DIRECTION INOUT ;
    USE SIGNAL ;
    PORT
      LAYER METAL3 ;
        RECT 0.0 763.17 1.4 764.57 ;
    END
  END VOUT<97>
  PIN VOUT<93>
    DIRECTION INOUT ;
    USE SIGNAL ;
    PORT
      LAYER METAL3 ;
        RECT 0.0 741.17 1.4 742.57 ;
    END
  END VOUT<93>
  PIN VOUT<89>
    DIRECTION INOUT ;
    USE SIGNAL ;
    PORT
      LAYER METAL3 ;
        RECT 0.0 719.17 1.4 720.57 ;
    END
  END VOUT<89>
  PIN VOUT<85>
    DIRECTION INOUT ;
    USE SIGNAL ;
    PORT
      LAYER METAL3 ;
        RECT 0.0 697.17 1.4 698.57 ;
    END
  END VOUT<85>
  PIN VOUT<81>
    DIRECTION INOUT ;
    USE SIGNAL ;
    PORT
      LAYER METAL3 ;
        RECT 0.0 675.17 1.4 676.57 ;
    END
  END VOUT<81>
  PIN VOUT<77>
    DIRECTION INOUT ;
    USE SIGNAL ;
    PORT
      LAYER METAL3 ;
        RECT 0.0 653.17 1.4 654.57 ;
    END
  END VOUT<77>
  PIN VOUT<73>
    DIRECTION INOUT ;
    USE SIGNAL ;
    PORT
      LAYER METAL3 ;
        RECT 0.0 631.17 1.4 632.57 ;
    END
  END VOUT<73>
  PIN VOUT<32>
    DIRECTION INOUT ;
    USE SIGNAL ;
    PORT
      LAYER METAL3 ;
        RECT 0.0 408.45 1.4 409.85 ;
    END
  END VOUT<32>
  PIN VOUT<28>
    DIRECTION INOUT ;
    USE SIGNAL ;
    PORT
      LAYER METAL3 ;
        RECT 0.0 386.45 1.4 387.85 ;
    END
  END VOUT<28>
  PIN VOUT<24>
    DIRECTION INOUT ;
    USE SIGNAL ;
    PORT
      LAYER METAL3 ;
        RECT 0.0 364.45 1.4 365.85 ;
    END
  END VOUT<24>
  PIN VOUT<20>
    DIRECTION INOUT ;
    USE SIGNAL ;
    PORT
      LAYER METAL3 ;
        RECT 0.0 342.45 1.4 343.85 ;
    END
  END VOUT<20>
  PIN VOUT<16>
    DIRECTION INOUT ;
    USE SIGNAL ;
    PORT
      LAYER METAL3 ;
        RECT 0.0 320.45 1.4 321.85 ;
    END
  END VOUT<16>
  PIN VOUT<12>
    DIRECTION INOUT ;
    USE SIGNAL ;
    PORT
      LAYER METAL3 ;
        RECT 0.0 298.45 1.4 299.85 ;
    END
  END VOUT<12>
  PIN VOUT<8>
    DIRECTION INOUT ;
    USE SIGNAL ;
    PORT
      LAYER METAL3 ;
        RECT 0.0 276.45 1.4 277.85 ;
    END
  END VOUT<8>
  PIN VOUT<4>
    DIRECTION INOUT ;
    USE SIGNAL ;
    PORT
      LAYER METAL3 ;
        RECT 0.0 254.45 1.4 255.85 ;
    END
  END VOUT<4>
  PIN VOUT<0>
    DIRECTION INOUT ;
    USE SIGNAL ;
    PORT
      LAYER METAL3 ;
        RECT 0.0 232.45 1.4 233.85 ;
    END
  END VOUT<0>
  PIN VOUT<69>
    DIRECTION INOUT ;
    USE SIGNAL ;
    PORT
      LAYER METAL3 ;
        RECT 0.0 609.17 1.4 610.57 ;
    END
  END VOUT<69>
  PIN VOUT<65>
    DIRECTION INOUT ;
    USE SIGNAL ;
    PORT
      LAYER METAL3 ;
        RECT 0.0 587.17 1.4 588.57 ;
    END
  END VOUT<65>
  PIN VOUT<61>
    DIRECTION INOUT ;
    USE SIGNAL ;
    PORT
      LAYER METAL3 ;
        RECT 0.0 565.17 1.4 566.57 ;
    END
  END VOUT<61>
  PIN VOUT<57>
    DIRECTION INOUT ;
    USE SIGNAL ;
    PORT
      LAYER METAL3 ;
        RECT 0.0 543.17 1.4 544.57 ;
    END
  END VOUT<57>
  PIN VOUT<53>
    DIRECTION INOUT ;
    USE SIGNAL ;
    PORT
      LAYER METAL3 ;
        RECT 0.0 521.17 1.4 522.57 ;
    END
  END VOUT<53>
  PIN VOUT<49>
    DIRECTION INOUT ;
    USE SIGNAL ;
    PORT
      LAYER METAL3 ;
        RECT 0.0 499.17 1.4 500.57 ;
    END
  END VOUT<49>
  PIN VOUT<45>
    DIRECTION INOUT ;
    USE SIGNAL ;
    PORT
      LAYER METAL3 ;
        RECT 0.0 477.17 1.4 478.57 ;
    END
  END VOUT<45>
  PIN VOUT<41>
    DIRECTION INOUT ;
    USE SIGNAL ;
    PORT
      LAYER METAL3 ;
        RECT 0.0 455.17 1.4 456.57 ;
    END
  END VOUT<41>
  PIN VOUT<37>
    DIRECTION INOUT ;
    USE SIGNAL ;
    PORT
      LAYER METAL3 ;
        RECT 0.0 433.17 1.4 434.57 ;
    END
  END VOUT<37>
  PIN VOUT<33>
    DIRECTION INOUT ;
    USE SIGNAL ;
    PORT
      LAYER METAL3 ;
        RECT 0.0 411.17 1.4 412.57 ;
    END
  END VOUT<33>
  PIN VOUT<29>
    DIRECTION INOUT ;
    USE SIGNAL ;
    PORT
      LAYER METAL3 ;
        RECT 0.0 389.17 1.4 390.57 ;
    END
  END VOUT<29>
  PIN VOUT<25>
    DIRECTION INOUT ;
    USE SIGNAL ;
    PORT
      LAYER METAL3 ;
        RECT 0.0 367.17 1.4 368.57 ;
    END
  END VOUT<25>
  PIN VOUT<21>
    DIRECTION INOUT ;
    USE SIGNAL ;
    PORT
      LAYER METAL3 ;
        RECT 0.0 345.17 1.4 346.57 ;
    END
  END VOUT<21>
  PIN VOUT<17>
    DIRECTION INOUT ;
    USE SIGNAL ;
    PORT
      LAYER METAL3 ;
        RECT 0.0 323.17 1.4 324.57 ;
    END
  END VOUT<17>
  PIN VOUT<13>
    DIRECTION INOUT ;
    USE SIGNAL ;
    PORT
      LAYER METAL3 ;
        RECT 0.0 301.17 1.4 302.57 ;
    END
  END VOUT<13>
  PIN VOUT<9>
    DIRECTION INOUT ;
    USE SIGNAL ;
    PORT
      LAYER METAL3 ;
        RECT 0.0 279.17 1.4 280.57 ;
    END
  END VOUT<9>
  PIN VOUT<5>
    DIRECTION INOUT ;
    USE SIGNAL ;
    PORT
      LAYER METAL3 ;
        RECT 0.0 257.17 1.4 258.57 ;
    END
  END VOUT<5>
  PIN VOUT<1>
    DIRECTION INOUT ;
    USE SIGNAL ;
    PORT
      LAYER METAL3 ;
        RECT 0.0 235.17 1.4 236.57 ;
    END
  END VOUT<1>
  PIN VOUT<276>
    DIRECTION INOUT ;
    USE SIGNAL ;
    PORT
      LAYER METAL3 ;
        RECT 0.0 1750.45 1.4 1751.85 ;
    END
  END VOUT<276>
  PIN VOUT<272>
    DIRECTION INOUT ;
    USE SIGNAL ;
    PORT
      LAYER METAL3 ;
        RECT 0.0 1728.45 1.4 1729.85 ;
    END
  END VOUT<272>
  PIN VOUT<268>
    DIRECTION INOUT ;
    USE SIGNAL ;
    PORT
      LAYER METAL3 ;
        RECT 0.0 1706.45 1.4 1707.85 ;
    END
  END VOUT<268>
  PIN VOUT<264>
    DIRECTION INOUT ;
    USE SIGNAL ;
    PORT
      LAYER METAL3 ;
        RECT 0.0 1684.45 1.4 1685.85 ;
    END
  END VOUT<264>
  PIN VOUT<260>
    DIRECTION INOUT ;
    USE SIGNAL ;
    PORT
      LAYER METAL3 ;
        RECT 0.0 1662.45 1.4 1663.85 ;
    END
  END VOUT<260>
  PIN VOUT<256>
    DIRECTION INOUT ;
    USE SIGNAL ;
    PORT
      LAYER METAL3 ;
        RECT 0.0 1640.45 1.4 1641.85 ;
    END
  END VOUT<256>
  PIN VOUT<252>
    DIRECTION INOUT ;
    USE SIGNAL ;
    PORT
      LAYER METAL3 ;
        RECT 0.0 1618.45 1.4 1619.85 ;
    END
  END VOUT<252>
  PIN VOUT<248>
    DIRECTION INOUT ;
    USE SIGNAL ;
    PORT
      LAYER METAL3 ;
        RECT 0.0 1596.45 1.4 1597.85 ;
    END
  END VOUT<248>
  PIN VOUT<244>
    DIRECTION INOUT ;
    USE SIGNAL ;
    PORT
      LAYER METAL3 ;
        RECT 0.0 1574.45 1.4 1575.85 ;
    END
  END VOUT<244>
  PIN VOUT<240>
    DIRECTION INOUT ;
    USE SIGNAL ;
    PORT
      LAYER METAL3 ;
        RECT 0.0 1552.45 1.4 1553.85 ;
    END
  END VOUT<240>
  PIN VOUT<236>
    DIRECTION INOUT ;
    USE SIGNAL ;
    PORT
      LAYER METAL3 ;
        RECT 0.0 1530.45 1.4 1531.85 ;
    END
  END VOUT<236>
  PIN VOUT<232>
    DIRECTION INOUT ;
    USE SIGNAL ;
    PORT
      LAYER METAL3 ;
        RECT 0.0 1508.45 1.4 1509.85 ;
    END
  END VOUT<232>
  PIN VOUT<228>
    DIRECTION INOUT ;
    USE SIGNAL ;
    PORT
      LAYER METAL3 ;
        RECT 0.0 1486.45 1.4 1487.85 ;
    END
  END VOUT<228>
  PIN VOUT<224>
    DIRECTION INOUT ;
    USE SIGNAL ;
    PORT
      LAYER METAL3 ;
        RECT 0.0 1464.45 1.4 1465.85 ;
    END
  END VOUT<224>
  PIN VOUT<220>
    DIRECTION INOUT ;
    USE SIGNAL ;
    PORT
      LAYER METAL3 ;
        RECT 0.0 1442.45 1.4 1443.85 ;
    END
  END VOUT<220>
  PIN VOUT<216>
    DIRECTION INOUT ;
    USE SIGNAL ;
    PORT
      LAYER METAL3 ;
        RECT 0.0 1420.45 1.4 1421.85 ;
    END
  END VOUT<216>
  PIN VOUT<212>
    DIRECTION INOUT ;
    USE SIGNAL ;
    PORT
      LAYER METAL3 ;
        RECT 0.0 1398.45 1.4 1399.85 ;
    END
  END VOUT<212>
  PIN VOUT<208>
    DIRECTION INOUT ;
    USE SIGNAL ;
    PORT
      LAYER METAL3 ;
        RECT 0.0 1376.45 1.4 1377.85 ;
    END
  END VOUT<208>
  PIN VOUT<204>
    DIRECTION INOUT ;
    USE SIGNAL ;
    PORT
      LAYER METAL3 ;
        RECT 0.0 1354.45 1.4 1355.85 ;
    END
  END VOUT<204>
  PIN VOUT<200>
    DIRECTION INOUT ;
    USE SIGNAL ;
    PORT
      LAYER METAL3 ;
        RECT 0.0 1332.45 1.4 1333.85 ;
    END
  END VOUT<200>
  PIN VOUT<196>
    DIRECTION INOUT ;
    USE SIGNAL ;
    PORT
      LAYER METAL3 ;
        RECT 0.0 1310.45 1.4 1311.85 ;
    END
  END VOUT<196>
  PIN VOUT<192>
    DIRECTION INOUT ;
    USE SIGNAL ;
    PORT
      LAYER METAL3 ;
        RECT 0.0 1288.45 1.4 1289.85 ;
    END
  END VOUT<192>
  PIN VOUT<188>
    DIRECTION INOUT ;
    USE SIGNAL ;
    PORT
      LAYER METAL3 ;
        RECT 0.0 1266.45 1.4 1267.85 ;
    END
  END VOUT<188>
  PIN VOUT<184>
    DIRECTION INOUT ;
    USE SIGNAL ;
    PORT
      LAYER METAL3 ;
        RECT 0.0 1244.45 1.4 1245.85 ;
    END
  END VOUT<184>
  PIN VOUT<180>
    DIRECTION INOUT ;
    USE SIGNAL ;
    PORT
      LAYER METAL3 ;
        RECT 0.0 1222.45 1.4 1223.85 ;
    END
  END VOUT<180>
  PIN VOUT<176>
    DIRECTION INOUT ;
    USE SIGNAL ;
    PORT
      LAYER METAL3 ;
        RECT 0.0 1200.45 1.4 1201.85 ;
    END
  END VOUT<176>
  PIN VOUT<172>
    DIRECTION INOUT ;
    USE SIGNAL ;
    PORT
      LAYER METAL3 ;
        RECT 0.0 1178.45 1.4 1179.85 ;
    END
  END VOUT<172>
  PIN VOUT<168>
    DIRECTION INOUT ;
    USE SIGNAL ;
    PORT
      LAYER METAL3 ;
        RECT 0.0 1156.45 1.4 1157.85 ;
    END
  END VOUT<168>
  PIN VOUT<164>
    DIRECTION INOUT ;
    USE SIGNAL ;
    PORT
      LAYER METAL3 ;
        RECT 0.0 1134.45 1.4 1135.85 ;
    END
  END VOUT<164>
  PIN VOUT<160>
    DIRECTION INOUT ;
    USE SIGNAL ;
    PORT
      LAYER METAL3 ;
        RECT 0.0 1112.45 1.4 1113.85 ;
    END
  END VOUT<160>
  PIN VOUT<156>
    DIRECTION INOUT ;
    USE SIGNAL ;
    PORT
      LAYER METAL3 ;
        RECT 0.0 1090.45 1.4 1091.85 ;
    END
  END VOUT<156>
  PIN VOUT<152>
    DIRECTION INOUT ;
    USE SIGNAL ;
    PORT
      LAYER METAL3 ;
        RECT 0.0 1068.45 1.4 1069.85 ;
    END
  END VOUT<152>
  PIN VOUT<148>
    DIRECTION INOUT ;
    USE SIGNAL ;
    PORT
      LAYER METAL3 ;
        RECT 0.0 1046.45 1.4 1047.85 ;
    END
  END VOUT<148>
  PIN VOUT<141>
    DIRECTION INOUT ;
    USE SIGNAL ;
    PORT
      LAYER METAL3 ;
        RECT 0.0 1005.17 1.4 1006.57 ;
    END
  END VOUT<141>
  PIN VOUT<145>
    DIRECTION INOUT ;
    USE SIGNAL ;
    PORT
      LAYER METAL3 ;
        RECT 0.0 1027.17 1.4 1028.57 ;
    END
  END VOUT<145>
  PIN VOUT<157>
    DIRECTION INOUT ;
    USE SIGNAL ;
    PORT
      LAYER METAL3 ;
        RECT 0.0 1093.17 1.4 1094.57 ;
    END
  END VOUT<157>
  PIN VOUT<173>
    DIRECTION INOUT ;
    USE SIGNAL ;
    PORT
      LAYER METAL3 ;
        RECT 0.0 1181.17 1.4 1182.57 ;
    END
  END VOUT<173>
  PIN VOUT<189>
    DIRECTION INOUT ;
    USE SIGNAL ;
    PORT
      LAYER METAL3 ;
        RECT 0.0 1269.17 1.4 1270.57 ;
    END
  END VOUT<189>
  PIN VOUT<205>
    DIRECTION INOUT ;
    USE SIGNAL ;
    PORT
      LAYER METAL3 ;
        RECT 0.0 1357.17 1.4 1358.57 ;
    END
  END VOUT<205>
  PIN VOUT<221>
    DIRECTION INOUT ;
    USE SIGNAL ;
    PORT
      LAYER METAL3 ;
        RECT 0.0 1445.17 1.4 1446.57 ;
    END
  END VOUT<221>
  PIN VOUT<237>
    DIRECTION INOUT ;
    USE SIGNAL ;
    PORT
      LAYER METAL3 ;
        RECT 0.0 1533.17 1.4 1534.57 ;
    END
  END VOUT<237>
  PIN VOUT<253>
    DIRECTION INOUT ;
    USE SIGNAL ;
    PORT
      LAYER METAL3 ;
        RECT 0.0 1621.17 1.4 1622.57 ;
    END
  END VOUT<253>
  PIN VOUT<269>
    DIRECTION INOUT ;
    USE SIGNAL ;
    PORT
      LAYER METAL3 ;
        RECT 0.0 1709.17 1.4 1710.57 ;
    END
  END VOUT<269>
  PIN VOUT<6>
    DIRECTION INOUT ;
    USE SIGNAL ;
    PORT
      LAYER METAL3 ;
        RECT 0.0 261.37 1.4 262.77 ;
    END
  END VOUT<6>
  PIN VOUT<22>
    DIRECTION INOUT ;
    USE SIGNAL ;
    PORT
      LAYER METAL3 ;
        RECT 0.0 349.37 1.4 350.77 ;
    END
  END VOUT<22>
  PIN VOUT<38>
    DIRECTION INOUT ;
    USE SIGNAL ;
    PORT
      LAYER METAL3 ;
        RECT 0.0 437.37 1.4 438.77 ;
    END
  END VOUT<38>
  PIN VOUT<54>
    DIRECTION INOUT ;
    USE SIGNAL ;
    PORT
      LAYER METAL3 ;
        RECT 0.0 525.37 1.4 526.77 ;
    END
  END VOUT<54>
  PIN VOUT<70>
    DIRECTION INOUT ;
    USE SIGNAL ;
    PORT
      LAYER METAL3 ;
        RECT 0.0 613.37 1.4 614.77 ;
    END
  END VOUT<70>
  PIN VOUT<86>
    DIRECTION INOUT ;
    USE SIGNAL ;
    PORT
      LAYER METAL3 ;
        RECT 0.0 701.37 1.4 702.77 ;
    END
  END VOUT<86>
  PIN VOUT<102>
    DIRECTION INOUT ;
    USE SIGNAL ;
    PORT
      LAYER METAL3 ;
        RECT 0.0 789.37 1.4 790.77 ;
    END
  END VOUT<102>
  PIN VOUT<118>
    DIRECTION INOUT ;
    USE SIGNAL ;
    PORT
      LAYER METAL3 ;
        RECT 0.0 877.37 1.4 878.77 ;
    END
  END VOUT<118>
  PIN VOUT<134>
    DIRECTION INOUT ;
    USE SIGNAL ;
    PORT
      LAYER METAL3 ;
        RECT 0.0 965.37 1.4 966.77 ;
    END
  END VOUT<134>
  PIN VOUT<150>
    DIRECTION INOUT ;
    USE SIGNAL ;
    PORT
      LAYER METAL3 ;
        RECT 0.0 1053.37 1.4 1054.77 ;
    END
  END VOUT<150>
  PIN VOUT<166>
    DIRECTION INOUT ;
    USE SIGNAL ;
    PORT
      LAYER METAL3 ;
        RECT 0.0 1141.37 1.4 1142.77 ;
    END
  END VOUT<166>
  PIN VOUT<182>
    DIRECTION INOUT ;
    USE SIGNAL ;
    PORT
      LAYER METAL3 ;
        RECT 0.0 1229.37 1.4 1230.77 ;
    END
  END VOUT<182>
  PIN VOUT<198>
    DIRECTION INOUT ;
    USE SIGNAL ;
    PORT
      LAYER METAL3 ;
        RECT 0.0 1317.37 1.4 1318.77 ;
    END
  END VOUT<198>
  PIN VOUT<214>
    DIRECTION INOUT ;
    USE SIGNAL ;
    PORT
      LAYER METAL3 ;
        RECT 0.0 1405.37 1.4 1406.77 ;
    END
  END VOUT<214>
  PIN VOUT<230>
    DIRECTION INOUT ;
    USE SIGNAL ;
    PORT
      LAYER METAL3 ;
        RECT 0.0 1493.37 1.4 1494.77 ;
    END
  END VOUT<230>
  PIN VOUT<246>
    DIRECTION INOUT ;
    USE SIGNAL ;
    PORT
      LAYER METAL3 ;
        RECT 0.0 1581.37 1.4 1582.77 ;
    END
  END VOUT<246>
  PIN VOUT<262>
    DIRECTION INOUT ;
    USE SIGNAL ;
    PORT
      LAYER METAL3 ;
        RECT 0.0 1669.37 1.4 1670.77 ;
    END
  END VOUT<262>
  PIN VOUT<278>
    DIRECTION INOUT ;
    USE SIGNAL ;
    PORT
      LAYER METAL3 ;
        RECT 0.0 1757.37 1.4 1758.77 ;
    END
  END VOUT<278>
  PIN VOUT<15>
    DIRECTION INOUT ;
    USE SIGNAL ;
    PORT
      LAYER METAL3 ;
        RECT 0.0 308.17 1.4 309.57 ;
    END
  END VOUT<15>
  PIN VOUT<31>
    DIRECTION INOUT ;
    USE SIGNAL ;
    PORT
      LAYER METAL3 ;
        RECT 0.0 396.17 1.4 397.57 ;
    END
  END VOUT<31>
  PIN VOUT<47>
    DIRECTION INOUT ;
    USE SIGNAL ;
    PORT
      LAYER METAL3 ;
        RECT 0.0 484.17 1.4 485.57 ;
    END
  END VOUT<47>
  PIN VOUT<63>
    DIRECTION INOUT ;
    USE SIGNAL ;
    PORT
      LAYER METAL3 ;
        RECT 0.0 572.17 1.4 573.57 ;
    END
  END VOUT<63>
  PIN VOUT<79>
    DIRECTION INOUT ;
    USE SIGNAL ;
    PORT
      LAYER METAL3 ;
        RECT 0.0 660.17 1.4 661.57 ;
    END
  END VOUT<79>
  PIN VOUT<95>
    DIRECTION INOUT ;
    USE SIGNAL ;
    PORT
      LAYER METAL3 ;
        RECT 0.0 748.17 1.4 749.57 ;
    END
  END VOUT<95>
  PIN VOUT<111>
    DIRECTION INOUT ;
    USE SIGNAL ;
    PORT
      LAYER METAL3 ;
        RECT 0.0 836.17 1.4 837.57 ;
    END
  END VOUT<111>
  PIN VOUT<127>
    DIRECTION INOUT ;
    USE SIGNAL ;
    PORT
      LAYER METAL3 ;
        RECT 0.0 924.17 1.4 925.57 ;
    END
  END VOUT<127>
  PIN VOUT<143>
    DIRECTION INOUT ;
    USE SIGNAL ;
    PORT
      LAYER METAL3 ;
        RECT 0.0 1012.17 1.4 1013.57 ;
    END
  END VOUT<143>
  PIN VOUT<159>
    DIRECTION INOUT ;
    USE SIGNAL ;
    PORT
      LAYER METAL3 ;
        RECT 0.0 1100.17 1.4 1101.57 ;
    END
  END VOUT<159>
  PIN VOUT<175>
    DIRECTION INOUT ;
    USE SIGNAL ;
    PORT
      LAYER METAL3 ;
        RECT 0.0 1188.17 1.4 1189.57 ;
    END
  END VOUT<175>
  PIN VOUT<191>
    DIRECTION INOUT ;
    USE SIGNAL ;
    PORT
      LAYER METAL3 ;
        RECT 0.0 1276.17 1.4 1277.57 ;
    END
  END VOUT<191>
  PIN VOUT<207>
    DIRECTION INOUT ;
    USE SIGNAL ;
    PORT
      LAYER METAL3 ;
        RECT 0.0 1364.17 1.4 1365.57 ;
    END
  END VOUT<207>
  PIN VOUT<223>
    DIRECTION INOUT ;
    USE SIGNAL ;
    PORT
      LAYER METAL3 ;
        RECT 0.0 1452.17 1.4 1453.57 ;
    END
  END VOUT<223>
  PIN VOUT<239>
    DIRECTION INOUT ;
    USE SIGNAL ;
    PORT
      LAYER METAL3 ;
        RECT 0.0 1540.17 1.4 1541.57 ;
    END
  END VOUT<239>
  PIN VOUT<255>
    DIRECTION INOUT ;
    USE SIGNAL ;
    PORT
      LAYER METAL3 ;
        RECT 0.0 1628.17 1.4 1629.57 ;
    END
  END VOUT<255>
  PIN VOUT<271>
    DIRECTION INOUT ;
    USE SIGNAL ;
    PORT
      LAYER METAL3 ;
        RECT 0.0 1716.17 1.4 1717.57 ;
    END
  END VOUT<271>
  PIN VOUT<161>
    DIRECTION INOUT ;
    USE SIGNAL ;
    PORT
      LAYER METAL3 ;
        RECT 0.0 1115.17 1.4 1116.57 ;
    END
  END VOUT<161>
  PIN VOUT<177>
    DIRECTION INOUT ;
    USE SIGNAL ;
    PORT
      LAYER METAL3 ;
        RECT 0.0 1203.17 1.4 1204.57 ;
    END
  END VOUT<177>
  PIN VOUT<193>
    DIRECTION INOUT ;
    USE SIGNAL ;
    PORT
      LAYER METAL3 ;
        RECT 0.0 1291.17 1.4 1292.57 ;
    END
  END VOUT<193>
  PIN VOUT<209>
    DIRECTION INOUT ;
    USE SIGNAL ;
    PORT
      LAYER METAL3 ;
        RECT 0.0 1379.17 1.4 1380.57 ;
    END
  END VOUT<209>
  PIN VOUT<225>
    DIRECTION INOUT ;
    USE SIGNAL ;
    PORT
      LAYER METAL3 ;
        RECT 0.0 1467.17 1.4 1468.57 ;
    END
  END VOUT<225>
  PIN VOUT<241>
    DIRECTION INOUT ;
    USE SIGNAL ;
    PORT
      LAYER METAL3 ;
        RECT 0.0 1555.17 1.4 1556.57 ;
    END
  END VOUT<241>
  PIN VOUT<257>
    DIRECTION INOUT ;
    USE SIGNAL ;
    PORT
      LAYER METAL3 ;
        RECT 0.0 1643.17 1.4 1644.57 ;
    END
  END VOUT<257>
  PIN VOUT<273>
    DIRECTION INOUT ;
    USE SIGNAL ;
    PORT
      LAYER METAL3 ;
        RECT 0.0 1731.17 1.4 1732.57 ;
    END
  END VOUT<273>
  PIN VOUT<10>
    DIRECTION INOUT ;
    USE SIGNAL ;
    PORT
      LAYER METAL3 ;
        RECT 0.0 283.37 1.4 284.77 ;
    END
  END VOUT<10>
  PIN VOUT<26>
    DIRECTION INOUT ;
    USE SIGNAL ;
    PORT
      LAYER METAL3 ;
        RECT 0.0 371.37 1.4 372.77 ;
    END
  END VOUT<26>
  PIN VOUT<42>
    DIRECTION INOUT ;
    USE SIGNAL ;
    PORT
      LAYER METAL3 ;
        RECT 0.0 459.37 1.4 460.77 ;
    END
  END VOUT<42>
  PIN VOUT<58>
    DIRECTION INOUT ;
    USE SIGNAL ;
    PORT
      LAYER METAL3 ;
        RECT 0.0 547.37 1.4 548.77 ;
    END
  END VOUT<58>
  PIN VOUT<74>
    DIRECTION INOUT ;
    USE SIGNAL ;
    PORT
      LAYER METAL3 ;
        RECT 0.0 635.37 1.4 636.77 ;
    END
  END VOUT<74>
  PIN w_DrainEnable_Mod
    DIRECTION INOUT ;
    USE SIGNAL ;
    PORT
      LAYER METAL3 ;
        RECT 5845.17 168.0 5847.97 169.4 ;
    END
  END w_DrainEnable_Mod
  PIN w_Drainline_Run
    DIRECTION INOUT ;
    USE SIGNAL ;
    PORT
      LAYER METAL3 ;
        RECT 5845.17 154.0 5847.97 155.4 ;
    END
  END w_Drainline_Run
  PIN w_Drainline_Prog
    DIRECTION INOUT ;
    USE SIGNAL ;
    PORT
      LAYER METAL3 ;
        RECT 5845.17 140.0 5847.97 141.4 ;
    END
  END w_Drainline_Prog
  PIN w_DrainB<8>
    DIRECTION INOUT ;
    USE SIGNAL ;
    PORT
      LAYER METAL3 ;
        RECT 5845.17 126.0 5847.97 127.4 ;
    END
  END w_DrainB<8>
  PIN w_DrainB<7>
    DIRECTION INOUT ;
    USE SIGNAL ;
    PORT
      LAYER METAL3 ;
        RECT 5845.17 112.0 5847.97 113.4 ;
    END
  END w_DrainB<7>
  PIN w_DrainB<6>
    DIRECTION INOUT ;
    USE SIGNAL ;
    PORT
      LAYER METAL3 ;
        RECT 5845.17 98.0 5847.97 99.4 ;
    END
  END w_DrainB<6>
  PIN w_DrainB<5>
    DIRECTION INOUT ;
    USE SIGNAL ;
    PORT
      LAYER METAL3 ;
        RECT 5845.17 84.0 5847.97 85.4 ;
    END
  END w_DrainB<5>
  PIN w_DrainB<4>
    DIRECTION INOUT ;
    USE SIGNAL ;
    PORT
      LAYER METAL3 ;
        RECT 5845.17 70.0 5847.97 71.4 ;
    END
  END w_DrainB<4>
  PIN w_DrainB<3>
    DIRECTION INOUT ;
    USE SIGNAL ;
    PORT
      LAYER METAL3 ;
        RECT 5845.17 56.0 5847.97 57.4 ;
    END
  END w_DrainB<3>
  PIN w_DrainB<2>
    DIRECTION INOUT ;
    USE SIGNAL ;
    PORT
      LAYER METAL3 ;
        RECT 5845.17 42.0 5847.97 43.4 ;
    END
  END w_DrainB<2>
  PIN w_DrainB<1>
    DIRECTION INOUT ;
    USE SIGNAL ;
    PORT
      LAYER METAL3 ;
        RECT 5845.17 28.0 5847.97 29.4 ;
    END
  END w_DrainB<1>
  PIN w_DrainB<0>
    DIRECTION INOUT ;
    USE SIGNAL ;
    PORT
      LAYER METAL3 ;
        RECT 5845.17 14.0 5847.97 15.4 ;
    END
  END w_DrainB<0>
  PIN s_vinj
    DIRECTION INOUT ;
    USE SIGNAL ;
    PORT
      LAYER METAL3 ;
        RECT 41.97 1817.17 43.37 1819.97 ;
    END
  END s_vinj
  PIN s_gnd
    DIRECTION INOUT ;
    USE SIGNAL ;
    PORT
      LAYER METAL3 ;
        RECT 27.97 1817.17 29.37 1819.97 ;
    END
  END s_gnd
  PIN e_VC
    DIRECTION INOUT ;
    USE SIGNAL ;
    PORT
      LAYER METAL3 ;
        RECT -0.03 42.0 2.77 43.4 ;
    END
  END e_VC
  PIN e_VG_P
    DIRECTION INOUT ;
    USE SIGNAL ;
    PORT
      LAYER METAL3 ;
        RECT -0.03 28.0 2.77 29.4 ;
    END
  END e_VG_P
  PIN e_VG_N
    DIRECTION INOUT ;
    USE SIGNAL ;
    PORT
      LAYER METAL3 ;
        RECT -0.03 14.0 2.77 15.4 ;
    END
  END e_VG_N
  PIN n_GateEnable_Mod
    DIRECTION INOUT ;
    USE SIGNAL ;
    PORT
      LAYER METAL3 ;
        RECT 5637.27 0.0 5638.67 2.8 ;
    END
  END n_GateEnable_Mod
  PIN n_GateB<8>
    DIRECTION INOUT ;
    USE SIGNAL ;
    PORT
      LAYER METAL3 ;
        RECT 5651.27 0.0 5652.67 2.8 ;
    END
  END n_GateB<8>
  PIN n_GateB<7>
    DIRECTION INOUT ;
    USE SIGNAL ;
    PORT
      LAYER METAL3 ;
        RECT 5665.27 0.0 5666.67 2.8 ;
    END
  END n_GateB<7>
  PIN n_GateB<6>
    DIRECTION INOUT ;
    USE SIGNAL ;
    PORT
      LAYER METAL3 ;
        RECT 5679.27 0.0 5680.67 2.8 ;
    END
  END n_GateB<6>
  PIN n_GateB<5>
    DIRECTION INOUT ;
    USE SIGNAL ;
    PORT
      LAYER METAL3 ;
        RECT 5693.27 0.0 5694.67 2.8 ;
    END
  END n_GateB<5>
  PIN n_GateB<4>
    DIRECTION INOUT ;
    USE SIGNAL ;
    PORT
      LAYER METAL3 ;
        RECT 5707.27 0.0 5708.67 2.8 ;
    END
  END n_GateB<4>
  PIN n_GateB<3>
    DIRECTION INOUT ;
    USE SIGNAL ;
    PORT
      LAYER METAL3 ;
        RECT 5721.27 0.0 5722.67 2.8 ;
    END
  END n_GateB<3>
  PIN n_GateB<2>
    DIRECTION INOUT ;
    USE SIGNAL ;
    PORT
      LAYER METAL3 ;
        RECT 5735.27 0.0 5736.67 2.8 ;
    END
  END n_GateB<2>
  PIN n_GateB<1>
    DIRECTION INOUT ;
    USE SIGNAL ;
    PORT
      LAYER METAL3 ;
        RECT 5749.27 0.0 5750.67 2.8 ;
    END
  END n_GateB<1>
  PIN n_GateB<0>
    DIRECTION INOUT ;
    USE SIGNAL ;
    PORT
      LAYER METAL3 ;
        RECT 5763.27 0.0 5764.67 2.8 ;
    END
  END n_GateB<0>
  PIN n_vinj
    DIRECTION INOUT ;
    USE SIGNAL ;
    PORT
      LAYER METAL3 ;
        RECT 41.97 0.0 43.37 2.8 ;
    END
  END n_vinj
  PIN n_gnd
    DIRECTION INOUT ;
    USE SIGNAL ;
    PORT
      LAYER METAL3 ;
        RECT 27.97 0.0 29.37 2.8 ;
    END
  END n_gnd
  PIN n_AVDD
    DIRECTION INOUT ;
    USE SIGNAL ;
    PORT
      LAYER METAL3 ;
        RECT 5777.27 0.0 5778.67 2.8 ;
    END
  END n_AVDD
  PIN n_VTUN
    DIRECTION INOUT ;
    USE SIGNAL ;
    PORT
      LAYER METAL3 ;
        RECT 5791.27 0.0 5792.67 2.8 ;
    END
  END n_VTUN
  PIN n_VGPROG
    DIRECTION INOUT ;
    USE SIGNAL ;
    PORT
      LAYER METAL3 ;
        RECT 5805.27 0.0 5806.67 2.8 ;
    END
  END n_VGPROG
  PIN n_Run
    DIRECTION INOUT ;
    USE SIGNAL ;
    PORT
      LAYER METAL3 ;
        RECT 5819.27 0.0 5820.67 2.8 ;
    END
  END n_Run
  PIN n_Prog
    DIRECTION INOUT ;
    USE SIGNAL ;
    PORT
      LAYER METAL3 ;
        RECT 5833.27 0.0 5834.67 2.8 ;
    END
  END n_Prog
  PIN VOUT<90>
    DIRECTION INOUT ;
    USE SIGNAL ;
    PORT
      LAYER METAL3 ;
        RECT 0.0 723.37 1.4 724.77 ;
    END
  END VOUT<90>
  PIN VOUT<106>
    DIRECTION INOUT ;
    USE SIGNAL ;
    PORT
      LAYER METAL3 ;
        RECT 0.0 811.37 1.4 812.77 ;
    END
  END VOUT<106>
  PIN VOUT<122>
    DIRECTION INOUT ;
    USE SIGNAL ;
    PORT
      LAYER METAL3 ;
        RECT 0.0 899.37 1.4 900.77 ;
    END
  END VOUT<122>
  PIN VOUT<138>
    DIRECTION INOUT ;
    USE SIGNAL ;
    PORT
      LAYER METAL3 ;
        RECT 0.0 987.37 1.4 988.77 ;
    END
  END VOUT<138>
  PIN VOUT<154>
    DIRECTION INOUT ;
    USE SIGNAL ;
    PORT
      LAYER METAL3 ;
        RECT 0.0 1075.37 1.4 1076.77 ;
    END
  END VOUT<154>
  PIN VOUT<170>
    DIRECTION INOUT ;
    USE SIGNAL ;
    PORT
      LAYER METAL3 ;
        RECT 0.0 1163.37 1.4 1164.77 ;
    END
  END VOUT<170>
  PIN VOUT<186>
    DIRECTION INOUT ;
    USE SIGNAL ;
    PORT
      LAYER METAL3 ;
        RECT 0.0 1251.37 1.4 1252.77 ;
    END
  END VOUT<186>
  PIN VOUT<202>
    DIRECTION INOUT ;
    USE SIGNAL ;
    PORT
      LAYER METAL3 ;
        RECT 0.0 1339.37 1.4 1340.77 ;
    END
  END VOUT<202>
  PIN VOUT<218>
    DIRECTION INOUT ;
    USE SIGNAL ;
    PORT
      LAYER METAL3 ;
        RECT 0.0 1427.37 1.4 1428.77 ;
    END
  END VOUT<218>
  PIN VOUT<234>
    DIRECTION INOUT ;
    USE SIGNAL ;
    PORT
      LAYER METAL3 ;
        RECT 0.0 1515.37 1.4 1516.77 ;
    END
  END VOUT<234>
  PIN VOUT<250>
    DIRECTION INOUT ;
    USE SIGNAL ;
    PORT
      LAYER METAL3 ;
        RECT 0.0 1603.37 1.4 1604.77 ;
    END
  END VOUT<250>
  PIN VOUT<266>
    DIRECTION INOUT ;
    USE SIGNAL ;
    PORT
      LAYER METAL3 ;
        RECT 0.0 1691.37 1.4 1692.77 ;
    END
  END VOUT<266>
  PIN VOUT<3>
    DIRECTION INOUT ;
    USE SIGNAL ;
    PORT
      LAYER METAL3 ;
        RECT 0.0 242.17 1.4 243.57 ;
    END
  END VOUT<3>
  PIN VOUT<19>
    DIRECTION INOUT ;
    USE SIGNAL ;
    PORT
      LAYER METAL3 ;
        RECT 0.0 330.17 1.4 331.57 ;
    END
  END VOUT<19>
  PIN VOUT<35>
    DIRECTION INOUT ;
    USE SIGNAL ;
    PORT
      LAYER METAL3 ;
        RECT 0.0 418.17 1.4 419.57 ;
    END
  END VOUT<35>
  PIN VOUT<51>
    DIRECTION INOUT ;
    USE SIGNAL ;
    PORT
      LAYER METAL3 ;
        RECT 0.0 506.17 1.4 507.57 ;
    END
  END VOUT<51>
  PIN VOUT<67>
    DIRECTION INOUT ;
    USE SIGNAL ;
    PORT
      LAYER METAL3 ;
        RECT 0.0 594.17 1.4 595.57 ;
    END
  END VOUT<67>
  PIN VOUT<83>
    DIRECTION INOUT ;
    USE SIGNAL ;
    PORT
      LAYER METAL3 ;
        RECT 0.0 682.17 1.4 683.57 ;
    END
  END VOUT<83>
  PIN VOUT<99>
    DIRECTION INOUT ;
    USE SIGNAL ;
    PORT
      LAYER METAL3 ;
        RECT 0.0 770.17 1.4 771.57 ;
    END
  END VOUT<99>
  PIN VOUT<115>
    DIRECTION INOUT ;
    USE SIGNAL ;
    PORT
      LAYER METAL3 ;
        RECT 0.0 858.17 1.4 859.57 ;
    END
  END VOUT<115>
  PIN VOUT<131>
    DIRECTION INOUT ;
    USE SIGNAL ;
    PORT
      LAYER METAL3 ;
        RECT 0.0 946.17 1.4 947.57 ;
    END
  END VOUT<131>
  PIN VOUT<147>
    DIRECTION INOUT ;
    USE SIGNAL ;
    PORT
      LAYER METAL3 ;
        RECT 0.0 1034.17 1.4 1035.57 ;
    END
  END VOUT<147>
  PIN VOUT<163>
    DIRECTION INOUT ;
    USE SIGNAL ;
    PORT
      LAYER METAL3 ;
        RECT 0.0 1122.17 1.4 1123.57 ;
    END
  END VOUT<163>
  PIN VOUT<179>
    DIRECTION INOUT ;
    USE SIGNAL ;
    PORT
      LAYER METAL3 ;
        RECT 0.0 1210.17 1.4 1211.57 ;
    END
  END VOUT<179>
  PIN VOUT<195>
    DIRECTION INOUT ;
    USE SIGNAL ;
    PORT
      LAYER METAL3 ;
        RECT 0.0 1298.17 1.4 1299.57 ;
    END
  END VOUT<195>
  PIN VOUT<211>
    DIRECTION INOUT ;
    USE SIGNAL ;
    PORT
      LAYER METAL3 ;
        RECT 0.0 1386.17 1.4 1387.57 ;
    END
  END VOUT<211>
  PIN VOUT<227>
    DIRECTION INOUT ;
    USE SIGNAL ;
    PORT
      LAYER METAL3 ;
        RECT 0.0 1474.17 1.4 1475.57 ;
    END
  END VOUT<227>
  PIN VOUT<243>
    DIRECTION INOUT ;
    USE SIGNAL ;
    PORT
      LAYER METAL3 ;
        RECT 0.0 1562.17 1.4 1563.57 ;
    END
  END VOUT<243>
  PIN VOUT<259>
    DIRECTION INOUT ;
    USE SIGNAL ;
    PORT
      LAYER METAL3 ;
        RECT 0.0 1650.17 1.4 1651.57 ;
    END
  END VOUT<259>
  PIN VOUT<275>
    DIRECTION INOUT ;
    USE SIGNAL ;
    PORT
      LAYER METAL3 ;
        RECT 0.0 1738.17 1.4 1739.57 ;
    END
  END VOUT<275>
END Modulation_Flip

MACRO TSMC350nm_Termination_bot
  PIN GATE
    DIRECTION INOUT ;
    USE SIGNAL ;
    PORT
      LAYER METAL1 ;
        RECT 0.0 14.7 1.42 16.1 ;
    END
  END GATE
  PIN IOUT
    DIRECTION INOUT ;
    USE SIGNAL ;
    PORT
      LAYER METAL1 ;
        RECT 18.64 3.38 20.06 4.78 ;
    END
  END IOUT
  PIN IREF
    DIRECTION INOUT ;
    USE SIGNAL ;
    PORT
      LAYER METAL1 ;
        RECT 0.0 2.1 1.42 3.5 ;
    END
  END IREF
  PIN GND_b
    DIRECTION INOUT ;
    USE SIGNAL ;
    PORT
      LAYER METAL2 ;
        RECT 2.8 0.0 4.2 1.52 ;
    END
  END GND_b
  PIN GND
    DIRECTION INOUT ;
    USE SIGNAL ;
    PORT
      LAYER METAL2 ;
        RECT 2.8 20.48 4.2 22.0 ;
    END
  END GND
END TSMC350nm_Termination_bot

MACRO frame_6p9mm_6p2mm_digbuf
  PIN buf_vdd_W<6>
    DIRECTION INOUT ;
    USE SIGNAL ;
    PORT
      LAYER METAL1 ;
        RECT 193.55 3991.65 194.95 3993.05 ;
    END
  END buf_vdd_W<6>
  PIN buf_vdd_W<5>
    DIRECTION INOUT ;
    USE SIGNAL ;
    PORT
      LAYER METAL1 ;
        RECT 193.55 4097.65 194.95 4099.05 ;
    END
  END buf_vdd_W<5>
  PIN buf_vdd_W<4>
    DIRECTION INOUT ;
    USE SIGNAL ;
    PORT
      LAYER METAL1 ;
        RECT 193.55 4203.65 194.95 4205.05 ;
    END
  END buf_vdd_W<4>
  PIN buf_vdd_W<3>
    DIRECTION INOUT ;
    USE SIGNAL ;
    PORT
      LAYER METAL1 ;
        RECT 193.55 4309.65 194.95 4311.05 ;
    END
  END buf_vdd_W<3>
  PIN buf_vdd_W<2>
    DIRECTION INOUT ;
    USE SIGNAL ;
    PORT
      LAYER METAL1 ;
        RECT 193.55 4415.65 194.95 4417.05 ;
    END
  END buf_vdd_W<2>
  PIN buf_vdd_E
    DIRECTION INOUT ;
    USE SIGNAL ;
    PORT
      LAYER METAL1 ;
        RECT 6705.05 4392.65 6706.45 4394.05 ;
    END
  END buf_vdd_E
  PIN buf_vdd_N<5>
    DIRECTION INOUT ;
    USE SIGNAL ;
    PORT
      LAYER METAL1 ;
        RECT 6110.8 5963.9 6112.2 5965.3 ;
    END
  END buf_vdd_N<5>
  PIN buf_vdd_N<2>
    DIRECTION INOUT ;
    USE SIGNAL ;
    PORT
      LAYER METAL1 ;
        RECT 2718.8 5963.9 2720.2 5965.3 ;
    END
  END buf_vdd_N<2>
  PIN buf_vdd_N<3>
    DIRECTION INOUT ;
    USE SIGNAL ;
    PORT
      LAYER METAL1 ;
        RECT 3142.8 5963.9 3144.2 5965.3 ;
    END
  END buf_vdd_N<3>
  PIN buf_vdd_N<1>
    DIRECTION INOUT ;
    USE SIGNAL ;
    PORT
      LAYER METAL1 ;
        RECT 2294.8 5963.9 2296.2 5965.3 ;
    END
  END buf_vdd_N<1>
  PIN buf_vdd_N<4>
    DIRECTION INOUT ;
    USE SIGNAL ;
    PORT
      LAYER METAL1 ;
        RECT 3884.8 5963.9 3886.2 5965.3 ;
    END
  END buf_vdd_N<4>
  PIN buf_vdd_N<0>
    DIRECTION INOUT ;
    USE SIGNAL ;
    PORT
      LAYER METAL1 ;
        RECT 916.8 5963.9 918.2 5965.3 ;
    END
  END buf_vdd_N<0>
  PIN buf_vdd_W<1>
    DIRECTION INOUT ;
    USE SIGNAL ;
    PORT
      LAYER METAL1 ;
        RECT 193.55 4521.65 194.95 4523.05 ;
    END
  END buf_vdd_W<1>
  PIN buf_vdd_W<0>
    DIRECTION INOUT ;
    USE SIGNAL ;
    PORT
      LAYER METAL1 ;
        RECT 193.55 4839.65 194.95 4841.05 ;
    END
  END buf_vdd_W<0>
  PIN buf_vdd_W<10>
    DIRECTION INOUT ;
    USE SIGNAL ;
    PORT
      LAYER METAL1 ;
        RECT 193.55 3567.65 194.95 3569.05 ;
    END
  END buf_vdd_W<10>
  PIN buf_vdd_W<9>
    DIRECTION INOUT ;
    USE SIGNAL ;
    PORT
      LAYER METAL1 ;
        RECT 193.55 3673.65 194.95 3675.05 ;
    END
  END buf_vdd_W<9>
  PIN buf_vdd_W<8>
    DIRECTION INOUT ;
    USE SIGNAL ;
    PORT
      LAYER METAL1 ;
        RECT 193.55 3779.65 194.95 3781.05 ;
    END
  END buf_vdd_W<8>
  PIN buf_vdd_W<7>
    DIRECTION INOUT ;
    USE SIGNAL ;
    PORT
      LAYER METAL1 ;
        RECT 193.55 3885.65 194.95 3887.05 ;
    END
  END buf_vdd_W<7>
  PIN gnd_W<1>
    DIRECTION INOUT ;
    USE SIGNAL ;
    PORT
      LAYER METAL2 ;
        RECT 194.1 5354.96 194.89 5362.75 ;
    END
  END gnd_W<1>
  PIN gnd_W<0>
    DIRECTION INOUT ;
    USE SIGNAL ;
    PORT
      LAYER METAL2 ;
        RECT 194.1 5672.95 194.9 5680.75 ;
    END
  END gnd_W<0>
  PIN VINJ_W
    DIRECTION INOUT ;
    USE SIGNAL ;
    PORT
      LAYER METAL2 ;
        RECT 194.1 2704.95 194.9 2712.75 ;
    END
  END VINJ_W
  PIN avdd_W
    DIRECTION INOUT ;
    USE SIGNAL ;
    PORT
      LAYER METAL2 ;
        RECT 194.1 2810.95 194.9 2818.75 ;
    END
  END avdd_W
  PIN esd_vdd_W
    DIRECTION INOUT ;
    USE SIGNAL ;
    PORT
      LAYER METAL2 ;
        RECT 194.1 2916.95 194.9 2924.75 ;
    END
  END esd_vdd_W
  PIN gnd_W<2>
    DIRECTION INOUT ;
    USE SIGNAL ;
    PORT
      LAYER METAL2 ;
        RECT 194.1 3022.96 194.88 3030.75 ;
    END
  END gnd_W<2>
  PIN VINJ_S<0>
    DIRECTION INOUT ;
    USE SIGNAL ;
    PORT
      LAYER METAL2 ;
        RECT 584.1 194.95 591.9 195.75 ;
    END
  END VINJ_S<0>
  PIN avdd_S<0>
    DIRECTION INOUT ;
    USE SIGNAL ;
    PORT
      LAYER METAL2 ;
        RECT 478.1 194.95 485.9 195.75 ;
    END
  END avdd_S<0>
  PIN esd_vdd_S<0>
    DIRECTION INOUT ;
    USE SIGNAL ;
    PORT
      LAYER METAL2 ;
        RECT 372.1 194.96 379.9 195.75 ;
    END
  END esd_vdd_S<0>
  PIN gnd_S<0>
    DIRECTION INOUT ;
    USE SIGNAL ;
    PORT
      LAYER METAL2 ;
        RECT 266.1 194.95 273.9 195.75 ;
    END
  END gnd_S<0>
  PIN VINJ_S<1>
    DIRECTION INOUT ;
    USE SIGNAL ;
    PORT
      LAYER METAL2 ;
        RECT 3552.1 194.95 3559.9 195.75 ;
    END
  END VINJ_S<1>
  PIN avdd_S<1>
    DIRECTION INOUT ;
    USE SIGNAL ;
    PORT
      LAYER METAL2 ;
        RECT 3446.1 194.95 3453.9 195.75 ;
    END
  END avdd_S<1>
  PIN esd_vdd_S<1>
    DIRECTION INOUT ;
    USE SIGNAL ;
    PORT
      LAYER METAL2 ;
        RECT 3340.1 194.95 3347.9 195.75 ;
    END
  END esd_vdd_S<1>
  PIN gnd_S<1>
    DIRECTION INOUT ;
    USE SIGNAL ;
    PORT
      LAYER METAL2 ;
        RECT 3234.1 194.95 3241.9 195.75 ;
    END
  END gnd_S<1>
  PIN VINJ_S<2>
    DIRECTION INOUT ;
    USE SIGNAL ;
    PORT
      LAYER METAL2 ;
        RECT 6520.1 194.95 6527.9 195.75 ;
    END
  END VINJ_S<2>
  PIN avdd_S<2>
    DIRECTION INOUT ;
    USE SIGNAL ;
    PORT
      LAYER METAL2 ;
        RECT 6414.1 194.95 6421.9 195.75 ;
    END
  END avdd_S<2>
  PIN esd_vdd_S<2>
    DIRECTION INOUT ;
    USE SIGNAL ;
    PORT
      LAYER METAL2 ;
        RECT 6308.1 194.95 6315.9 195.75 ;
    END
  END esd_vdd_S<2>
  PIN gnd_S<2>
    DIRECTION INOUT ;
    USE SIGNAL ;
    PORT
      LAYER METAL2 ;
        RECT 6202.1 194.95 6209.9 195.75 ;
    END
  END gnd_S<2>
  PIN VINJ_E
    DIRECTION INOUT ;
    USE SIGNAL ;
    PORT
      LAYER METAL2 ;
        RECT 6705.1 2704.95 6705.9 2712.75 ;
    END
  END VINJ_E
  PIN avdd_E
    DIRECTION INOUT ;
    USE SIGNAL ;
    PORT
      LAYER METAL2 ;
        RECT 6705.1 2810.95 6705.9 2818.75 ;
    END
  END avdd_E
  PIN esd_vdd_E
    DIRECTION INOUT ;
    USE SIGNAL ;
    PORT
      LAYER METAL2 ;
        RECT 6705.1 2916.95 6705.9 2924.75 ;
    END
  END esd_vdd_E
  PIN gnd_E<2>
    DIRECTION INOUT ;
    USE SIGNAL ;
    PORT
      LAYER METAL2 ;
        RECT 6705.1 3022.95 6705.9 3030.75 ;
    END
  END gnd_E<2>
  PIN gnd_E<1>
    DIRECTION INOUT ;
    USE SIGNAL ;
    PORT
      LAYER METAL2 ;
        RECT 6705.1 5354.95 6705.9 5362.75 ;
    END
  END gnd_E<1>
  PIN gnd_E<0>
    DIRECTION INOUT ;
    USE SIGNAL ;
    PORT
      LAYER METAL2 ;
        RECT 6705.1 5672.95 6705.9 5680.75 ;
    END
  END gnd_E<0>
  PIN VINJ_N<2>
    DIRECTION INOUT ;
    USE SIGNAL ;
    PORT
      LAYER METAL2 ;
        RECT 6520.1 5963.95 6527.9 5964.75 ;
    END
  END VINJ_N<2>
  PIN avdd_N<2>
    DIRECTION INOUT ;
    USE SIGNAL ;
    PORT
      LAYER METAL2 ;
        RECT 6414.1 5963.95 6421.9 5964.75 ;
    END
  END avdd_N<2>
  PIN esd_vdd_N<2>
    DIRECTION INOUT ;
    USE SIGNAL ;
    PORT
      LAYER METAL2 ;
        RECT 6308.1 5963.95 6315.9 5964.75 ;
    END
  END esd_vdd_N<2>
  PIN gnd_N<8>
    DIRECTION INOUT ;
    USE SIGNAL ;
    PORT
      LAYER METAL2 ;
        RECT 6202.1 5963.95 6209.9 5964.75 ;
    END
  END gnd_N<8>
  PIN gnd_N<7>
    DIRECTION INOUT ;
    USE SIGNAL ;
    PORT
      LAYER METAL2 ;
        RECT 5990.1 5963.95 5997.9 5964.75 ;
    END
  END gnd_N<7>
  PIN gnd_N<6>
    DIRECTION INOUT ;
    USE SIGNAL ;
    PORT
      LAYER METAL2 ;
        RECT 3976.1 5963.95 3983.9 5964.75 ;
    END
  END gnd_N<6>
  PIN gnd_N<5>
    DIRECTION INOUT ;
    USE SIGNAL ;
    PORT
      LAYER METAL2 ;
        RECT 3764.1 5963.95 3771.9 5964.75 ;
    END
  END gnd_N<5>
  PIN VINJ_N<1>
    DIRECTION INOUT ;
    USE SIGNAL ;
    PORT
      LAYER METAL2 ;
        RECT 3552.1 5963.95 3559.9 5964.75 ;
    END
  END VINJ_N<1>
  PIN avdd_N<1>
    DIRECTION INOUT ;
    USE SIGNAL ;
    PORT
      LAYER METAL2 ;
        RECT 3446.1 5963.95 3453.9 5964.75 ;
    END
  END avdd_N<1>
  PIN esd_vdd_N<1>
    DIRECTION INOUT ;
    USE SIGNAL ;
    PORT
      LAYER METAL2 ;
        RECT 3340.1 5963.95 3347.9 5964.75 ;
    END
  END esd_vdd_N<1>
  PIN gnd_N<4>
    DIRECTION INOUT ;
    USE SIGNAL ;
    PORT
      LAYER METAL2 ;
        RECT 3234.1 5963.95 3241.9 5964.75 ;
    END
  END gnd_N<4>
  PIN gnd_N<3>
    DIRECTION INOUT ;
    USE SIGNAL ;
    PORT
      LAYER METAL2 ;
        RECT 3022.1 5963.95 3029.91 5964.75 ;
    END
  END gnd_N<3>
  PIN gnd_N<2>
    DIRECTION INOUT ;
    USE SIGNAL ;
    PORT
      LAYER METAL2 ;
        RECT 1008.1 5963.95 1015.9 5964.75 ;
    END
  END gnd_N<2>
  PIN gnd_N<1>
    DIRECTION INOUT ;
    USE SIGNAL ;
    PORT
      LAYER METAL2 ;
        RECT 796.1 5963.95 803.9 5964.75 ;
    END
  END gnd_N<1>
  PIN VINJ_N<0>
    DIRECTION INOUT ;
    USE SIGNAL ;
    PORT
      LAYER METAL2 ;
        RECT 584.1 5963.95 591.9 5964.75 ;
    END
  END VINJ_N<0>
  PIN avdd_N<0>
    DIRECTION INOUT ;
    USE SIGNAL ;
    PORT
      LAYER METAL2 ;
        RECT 478.1 5963.96 485.9 5964.75 ;
    END
  END avdd_N<0>
  PIN esd_vdd_N<0>
    DIRECTION INOUT ;
    USE SIGNAL ;
    PORT
      LAYER METAL2 ;
        RECT 372.1 5963.95 379.9 5964.75 ;
    END
  END esd_vdd_N<0>
  PIN gnd_N<0>
    DIRECTION INOUT ;
    USE SIGNAL ;
    PORT
      LAYER METAL2 ;
        RECT 266.1 5963.95 273.9 5964.75 ;
    END
  END gnd_N<0>
  PIN DVDD_N<2>
    DIRECTION INOUT ;
    USE SIGNAL ;
    PORT
      LAYER METAL2 ;
        RECT 6626.1 5963.95 6633.9 5964.75 ;
    END
  END DVDD_N<2>
  PIN IO_N_CLK<3>
    DIRECTION INOUT ;
    USE SIGNAL ;
    PORT
      LAYER METAL2 ;
        RECT 6096.1 5963.95 6103.9 5964.75 ;
    END
  END IO_N_CLK<3>
  PIN IO_N<35>
    DIRECTION INOUT ;
    USE SIGNAL ;
    PORT
      LAYER METAL2 ;
        RECT 5884.1 5963.95 5891.9 5964.75 ;
    END
  END IO_N<35>
  PIN IO_N<34>
    DIRECTION INOUT ;
    USE SIGNAL ;
    PORT
      LAYER METAL2 ;
        RECT 5778.1 5963.95 5785.9 5964.75 ;
    END
  END IO_N<34>
  PIN IO_N<33>
    DIRECTION INOUT ;
    USE SIGNAL ;
    PORT
      LAYER METAL2 ;
        RECT 5672.1 5963.95 5679.9 5964.75 ;
    END
  END IO_N<33>
  PIN IO_N<32>
    DIRECTION INOUT ;
    USE SIGNAL ;
    PORT
      LAYER METAL2 ;
        RECT 5566.1 5963.95 5573.9 5964.75 ;
    END
  END IO_N<32>
  PIN IO_N<31>
    DIRECTION INOUT ;
    USE SIGNAL ;
    PORT
      LAYER METAL2 ;
        RECT 5460.1 5963.95 5467.9 5964.75 ;
    END
  END IO_N<31>
  PIN IO_N<30>
    DIRECTION INOUT ;
    USE SIGNAL ;
    PORT
      LAYER METAL2 ;
        RECT 5354.1 5963.95 5361.9 5964.75 ;
    END
  END IO_N<30>
  PIN IO_N<29>
    DIRECTION INOUT ;
    USE SIGNAL ;
    PORT
      LAYER METAL2 ;
        RECT 5248.1 5963.95 5255.9 5964.75 ;
    END
  END IO_N<29>
  PIN IO_N<28>
    DIRECTION INOUT ;
    USE SIGNAL ;
    PORT
      LAYER METAL2 ;
        RECT 5142.1 5963.95 5149.9 5964.75 ;
    END
  END IO_N<28>
  PIN IO_N<27>
    DIRECTION INOUT ;
    USE SIGNAL ;
    PORT
      LAYER METAL2 ;
        RECT 5036.1 5963.95 5043.9 5964.75 ;
    END
  END IO_N<27>
  PIN IO_N<26>
    DIRECTION INOUT ;
    USE SIGNAL ;
    PORT
      LAYER METAL2 ;
        RECT 4930.1 5963.95 4937.9 5964.75 ;
    END
  END IO_N<26>
  PIN IO_N<25>
    DIRECTION INOUT ;
    USE SIGNAL ;
    PORT
      LAYER METAL2 ;
        RECT 4824.1 5963.95 4831.9 5964.75 ;
    END
  END IO_N<25>
  PIN IO_N<24>
    DIRECTION INOUT ;
    USE SIGNAL ;
    PORT
      LAYER METAL2 ;
        RECT 4718.1 5963.95 4725.9 5964.75 ;
    END
  END IO_N<24>
  PIN IO_N<23>
    DIRECTION INOUT ;
    USE SIGNAL ;
    PORT
      LAYER METAL2 ;
        RECT 4612.1 5963.95 4619.9 5964.75 ;
    END
  END IO_N<23>
  PIN IO_N<22>
    DIRECTION INOUT ;
    USE SIGNAL ;
    PORT
      LAYER METAL2 ;
        RECT 4506.1 5963.95 4513.9 5964.75 ;
    END
  END IO_N<22>
  PIN IO_N<21>
    DIRECTION INOUT ;
    USE SIGNAL ;
    PORT
      LAYER METAL2 ;
        RECT 4400.1 5963.95 4407.9 5964.75 ;
    END
  END IO_N<21>
  PIN IO_N<20>
    DIRECTION INOUT ;
    USE SIGNAL ;
    PORT
      LAYER METAL2 ;
        RECT 4294.1 5963.95 4301.9 5964.75 ;
    END
  END IO_N<20>
  PIN IO_N<19>
    DIRECTION INOUT ;
    USE SIGNAL ;
    PORT
      LAYER METAL2 ;
        RECT 4188.1 5963.95 4195.9 5964.75 ;
    END
  END IO_N<19>
  PIN IO_N<18>
    DIRECTION INOUT ;
    USE SIGNAL ;
    PORT
      LAYER METAL2 ;
        RECT 4082.1 5963.95 4089.9 5964.75 ;
    END
  END IO_N<18>
  PIN IO_N_CLK<2>
    DIRECTION INOUT ;
    USE SIGNAL ;
    PORT
      LAYER METAL2 ;
        RECT 3870.1 5963.95 3877.9 5964.75 ;
    END
  END IO_N_CLK<2>
  PIN DVDD_N<1>
    DIRECTION INOUT ;
    USE SIGNAL ;
    PORT
      LAYER METAL2 ;
        RECT 3658.1 5963.95 3665.9 5964.75 ;
    END
  END DVDD_N<1>
  PIN IO_N_CLK<1>
    DIRECTION INOUT ;
    USE SIGNAL ;
    PORT
      LAYER METAL2 ;
        RECT 3128.1 5963.95 3135.9 5964.75 ;
    END
  END IO_N_CLK<1>
  PIN IO_N<17>
    DIRECTION INOUT ;
    USE SIGNAL ;
    PORT
      LAYER METAL2 ;
        RECT 2916.1 5963.95 2923.9 5964.75 ;
    END
  END IO_N<17>
  PIN IO_N<16>
    DIRECTION INOUT ;
    USE SIGNAL ;
    PORT
      LAYER METAL2 ;
        RECT 2810.1 5963.95 2817.9 5964.75 ;
    END
  END IO_N<16>
  PIN IO_N<15>
    DIRECTION INOUT ;
    USE SIGNAL ;
    PORT
      LAYER METAL2 ;
        RECT 2704.1 5963.95 2711.9 5964.75 ;
    END
  END IO_N<15>
  PIN IO_N<14>
    DIRECTION INOUT ;
    USE SIGNAL ;
    PORT
      LAYER METAL2 ;
        RECT 2598.1 5963.95 2605.9 5964.75 ;
    END
  END IO_N<14>
  PIN IO_N<13>
    DIRECTION INOUT ;
    USE SIGNAL ;
    PORT
      LAYER METAL2 ;
        RECT 2492.1 5963.95 2499.9 5964.75 ;
    END
  END IO_N<13>
  PIN IO_N<12>
    DIRECTION INOUT ;
    USE SIGNAL ;
    PORT
      LAYER METAL2 ;
        RECT 2386.1 5963.95 2393.9 5964.75 ;
    END
  END IO_N<12>
  PIN IO_N<11>
    DIRECTION INOUT ;
    USE SIGNAL ;
    PORT
      LAYER METAL2 ;
        RECT 2280.1 5963.95 2287.9 5964.75 ;
    END
  END IO_N<11>
  PIN IO_N<10>
    DIRECTION INOUT ;
    USE SIGNAL ;
    PORT
      LAYER METAL2 ;
        RECT 2174.1 5963.95 2181.9 5964.75 ;
    END
  END IO_N<10>
  PIN IO_N<9>
    DIRECTION INOUT ;
    USE SIGNAL ;
    PORT
      LAYER METAL2 ;
        RECT 2068.1 5963.95 2075.9 5964.75 ;
    END
  END IO_N<9>
  PIN IO_N<8>
    DIRECTION INOUT ;
    USE SIGNAL ;
    PORT
      LAYER METAL2 ;
        RECT 1962.1 5963.95 1969.9 5964.75 ;
    END
  END IO_N<8>
  PIN IO_N<7>
    DIRECTION INOUT ;
    USE SIGNAL ;
    PORT
      LAYER METAL2 ;
        RECT 1856.1 5963.95 1863.9 5964.75 ;
    END
  END IO_N<7>
  PIN IO_N<6>
    DIRECTION INOUT ;
    USE SIGNAL ;
    PORT
      LAYER METAL2 ;
        RECT 1750.1 5963.95 1757.9 5964.75 ;
    END
  END IO_N<6>
  PIN IO_N<5>
    DIRECTION INOUT ;
    USE SIGNAL ;
    PORT
      LAYER METAL2 ;
        RECT 1644.1 5963.95 1651.9 5964.75 ;
    END
  END IO_N<5>
  PIN IO_N<4>
    DIRECTION INOUT ;
    USE SIGNAL ;
    PORT
      LAYER METAL2 ;
        RECT 1538.1 5963.95 1545.9 5964.75 ;
    END
  END IO_N<4>
  PIN IO_N<3>
    DIRECTION INOUT ;
    USE SIGNAL ;
    PORT
      LAYER METAL2 ;
        RECT 1432.1 5963.95 1439.9 5964.75 ;
    END
  END IO_N<3>
  PIN IO_N<2>
    DIRECTION INOUT ;
    USE SIGNAL ;
    PORT
      LAYER METAL2 ;
        RECT 1326.1 5963.95 1333.9 5964.75 ;
    END
  END IO_N<2>
  PIN IO_N<1>
    DIRECTION INOUT ;
    USE SIGNAL ;
    PORT
      LAYER METAL2 ;
        RECT 1220.1 5963.95 1227.9 5964.75 ;
    END
  END IO_N<1>
  PIN IO_N<0>
    DIRECTION INOUT ;
    USE SIGNAL ;
    PORT
      LAYER METAL2 ;
        RECT 1114.1 5963.95 1121.9 5964.75 ;
    END
  END IO_N<0>
  PIN IO_N_CLK<0>
    DIRECTION INOUT ;
    USE SIGNAL ;
    PORT
      LAYER METAL2 ;
        RECT 902.1 5963.95 909.9 5964.75 ;
    END
  END IO_N_CLK<0>
  PIN DVDD_N<0>
    DIRECTION INOUT ;
    USE SIGNAL ;
    PORT
      LAYER METAL2 ;
        RECT 690.1 5963.95 697.9 5964.75 ;
    END
  END DVDD_N<0>
  PIN IO_W<1>
    DIRECTION INOUT ;
    USE SIGNAL ;
    PORT
      LAYER METAL2 ;
        RECT 194.1 5142.95 194.9 5150.75 ;
    END
  END IO_W<1>
  PIN IO_W<0>
    DIRECTION INOUT ;
    USE SIGNAL ;
    PORT
      LAYER METAL2 ;
        RECT 194.1 5248.95 194.9 5256.75 ;
    END
  END IO_W<0>
  PIN IO_E_RES<1>
    DIRECTION INOUT ;
    USE SIGNAL ;
    PORT
      LAYER METAL2 ;
        RECT 6705.1 5460.95 6705.9 5468.75 ;
    END
  END IO_E_RES<1>
  PIN IO_E_RES<0>
    DIRECTION INOUT ;
    USE SIGNAL ;
    PORT
      LAYER METAL2 ;
        RECT 6705.1 5566.95 6705.9 5574.75 ;
    END
  END IO_E_RES<0>
  PIN IO_Bare_E<1>
    DIRECTION INOUT ;
    USE SIGNAL ;
    PORT
      LAYER METAL2 ;
        RECT 6705.1 5778.95 6705.9 5786.75 ;
    END
  END IO_Bare_E<1>
  PIN IO_Bare_E<0>
    DIRECTION INOUT ;
    USE SIGNAL ;
    PORT
      LAYER METAL2 ;
        RECT 6705.1 5884.95 6705.9 5892.75 ;
    END
  END IO_Bare_E<0>
  PIN IO_W_RES<1>
    DIRECTION INOUT ;
    USE SIGNAL ;
    PORT
      LAYER METAL2 ;
        RECT 194.1 5460.95 194.9 5468.75 ;
    END
  END IO_W_RES<1>
  PIN IO_W_RES<0>
    DIRECTION INOUT ;
    USE SIGNAL ;
    PORT
      LAYER METAL2 ;
        RECT 194.1 5566.95 194.9 5574.75 ;
    END
  END IO_W_RES<0>
  PIN IO_Bare_W<1>
    DIRECTION INOUT ;
    USE SIGNAL ;
    PORT
      LAYER METAL2 ;
        RECT 194.1 5778.95 194.9 5786.75 ;
    END
  END IO_Bare_W<1>
  PIN IO_Bare_W<0>
    DIRECTION INOUT ;
    USE SIGNAL ;
    PORT
      LAYER METAL2 ;
        RECT 194.1 5884.95 194.9 5892.75 ;
    END
  END IO_Bare_W<0>
  PIN DVDD_S<2>
    DIRECTION INOUT ;
    USE SIGNAL ;
    PORT
      LAYER METAL2 ;
        RECT 6626.1 194.95 6633.9 195.75 ;
    END
  END DVDD_S<2>
  PIN IO_S<45>
    DIRECTION INOUT ;
    USE SIGNAL ;
    PORT
      LAYER METAL2 ;
        RECT 6096.1 194.95 6103.9 195.75 ;
    END
  END IO_S<45>
  PIN IO_S<44>
    DIRECTION INOUT ;
    USE SIGNAL ;
    PORT
      LAYER METAL2 ;
        RECT 5990.1 194.95 5997.9 195.75 ;
    END
  END IO_S<44>
  PIN IO_S<43>
    DIRECTION INOUT ;
    USE SIGNAL ;
    PORT
      LAYER METAL2 ;
        RECT 5884.1 194.95 5891.9 195.75 ;
    END
  END IO_S<43>
  PIN IO_S<42>
    DIRECTION INOUT ;
    USE SIGNAL ;
    PORT
      LAYER METAL2 ;
        RECT 5778.1 194.95 5785.9 195.75 ;
    END
  END IO_S<42>
  PIN IO_S<41>
    DIRECTION INOUT ;
    USE SIGNAL ;
    PORT
      LAYER METAL2 ;
        RECT 5672.1 194.95 5679.9 195.75 ;
    END
  END IO_S<41>
  PIN IO_S<40>
    DIRECTION INOUT ;
    USE SIGNAL ;
    PORT
      LAYER METAL2 ;
        RECT 5566.1 194.95 5573.9 195.75 ;
    END
  END IO_S<40>
  PIN IO_S<39>
    DIRECTION INOUT ;
    USE SIGNAL ;
    PORT
      LAYER METAL2 ;
        RECT 5460.1 194.95 5467.9 195.75 ;
    END
  END IO_S<39>
  PIN IO_S<38>
    DIRECTION INOUT ;
    USE SIGNAL ;
    PORT
      LAYER METAL2 ;
        RECT 5354.1 194.95 5361.9 195.75 ;
    END
  END IO_S<38>
  PIN IO_S<37>
    DIRECTION INOUT ;
    USE SIGNAL ;
    PORT
      LAYER METAL2 ;
        RECT 5248.1 194.95 5255.9 195.75 ;
    END
  END IO_S<37>
  PIN IO_S<36>
    DIRECTION INOUT ;
    USE SIGNAL ;
    PORT
      LAYER METAL2 ;
        RECT 5142.1 194.95 5149.9 195.75 ;
    END
  END IO_S<36>
  PIN IO_S<35>
    DIRECTION INOUT ;
    USE SIGNAL ;
    PORT
      LAYER METAL2 ;
        RECT 5036.1 194.95 5043.9 195.75 ;
    END
  END IO_S<35>
  PIN IO_S<34>
    DIRECTION INOUT ;
    USE SIGNAL ;
    PORT
      LAYER METAL2 ;
        RECT 4930.1 194.95 4937.9 195.75 ;
    END
  END IO_S<34>
  PIN IO_S<33>
    DIRECTION INOUT ;
    USE SIGNAL ;
    PORT
      LAYER METAL2 ;
        RECT 4824.1 194.95 4831.9 195.75 ;
    END
  END IO_S<33>
  PIN IO_S<32>
    DIRECTION INOUT ;
    USE SIGNAL ;
    PORT
      LAYER METAL2 ;
        RECT 4718.1 194.95 4725.9 195.75 ;
    END
  END IO_S<32>
  PIN IO_S<31>
    DIRECTION INOUT ;
    USE SIGNAL ;
    PORT
      LAYER METAL2 ;
        RECT 4612.1 194.95 4619.9 195.75 ;
    END
  END IO_S<31>
  PIN IO_S<30>
    DIRECTION INOUT ;
    USE SIGNAL ;
    PORT
      LAYER METAL2 ;
        RECT 4506.1 194.95 4513.9 195.75 ;
    END
  END IO_S<30>
  PIN IO_S<29>
    DIRECTION INOUT ;
    USE SIGNAL ;
    PORT
      LAYER METAL2 ;
        RECT 4400.1 194.95 4407.9 195.75 ;
    END
  END IO_S<29>
  PIN IO_S<28>
    DIRECTION INOUT ;
    USE SIGNAL ;
    PORT
      LAYER METAL2 ;
        RECT 4294.1 194.95 4301.9 195.75 ;
    END
  END IO_S<28>
  PIN IO_S<27>
    DIRECTION INOUT ;
    USE SIGNAL ;
    PORT
      LAYER METAL2 ;
        RECT 4188.1 194.95 4195.9 195.75 ;
    END
  END IO_S<27>
  PIN IO_S<26>
    DIRECTION INOUT ;
    USE SIGNAL ;
    PORT
      LAYER METAL2 ;
        RECT 4082.1 194.95 4089.9 195.75 ;
    END
  END IO_S<26>
  PIN IO_S<25>
    DIRECTION INOUT ;
    USE SIGNAL ;
    PORT
      LAYER METAL2 ;
        RECT 3976.1 194.95 3983.9 195.75 ;
    END
  END IO_S<25>
  PIN IO_S<24>
    DIRECTION INOUT ;
    USE SIGNAL ;
    PORT
      LAYER METAL2 ;
        RECT 3870.1 194.95 3877.9 195.75 ;
    END
  END IO_S<24>
  PIN IO_S<23>
    DIRECTION INOUT ;
    USE SIGNAL ;
    PORT
      LAYER METAL2 ;
        RECT 3764.1 194.95 3771.9 195.75 ;
    END
  END IO_S<23>
  PIN DVDD_S<1>
    DIRECTION INOUT ;
    USE SIGNAL ;
    PORT
      LAYER METAL2 ;
        RECT 3658.1 194.95 3665.9 195.75 ;
    END
  END DVDD_S<1>
  PIN IO_S<22>
    DIRECTION INOUT ;
    USE SIGNAL ;
    PORT
      LAYER METAL2 ;
        RECT 3128.1 194.95 3135.9 195.75 ;
    END
  END IO_S<22>
  PIN IO_S<21>
    DIRECTION INOUT ;
    USE SIGNAL ;
    PORT
      LAYER METAL2 ;
        RECT 3022.1 194.95 3029.9 195.75 ;
    END
  END IO_S<21>
  PIN IO_S<20>
    DIRECTION INOUT ;
    USE SIGNAL ;
    PORT
      LAYER METAL2 ;
        RECT 2916.1 194.95 2923.9 195.75 ;
    END
  END IO_S<20>
  PIN IO_S<19>
    DIRECTION INOUT ;
    USE SIGNAL ;
    PORT
      LAYER METAL2 ;
        RECT 2810.1 194.95 2817.9 195.75 ;
    END
  END IO_S<19>
  PIN IO_S<18>
    DIRECTION INOUT ;
    USE SIGNAL ;
    PORT
      LAYER METAL2 ;
        RECT 2704.1 194.95 2711.9 195.75 ;
    END
  END IO_S<18>
  PIN IO_S<17>
    DIRECTION INOUT ;
    USE SIGNAL ;
    PORT
      LAYER METAL2 ;
        RECT 2598.1 194.95 2605.9 195.75 ;
    END
  END IO_S<17>
  PIN IO_S<16>
    DIRECTION INOUT ;
    USE SIGNAL ;
    PORT
      LAYER METAL2 ;
        RECT 2492.1 194.95 2499.9 195.75 ;
    END
  END IO_S<16>
  PIN IO_S<15>
    DIRECTION INOUT ;
    USE SIGNAL ;
    PORT
      LAYER METAL2 ;
        RECT 2386.1 194.95 2393.9 195.75 ;
    END
  END IO_S<15>
  PIN IO_S<14>
    DIRECTION INOUT ;
    USE SIGNAL ;
    PORT
      LAYER METAL2 ;
        RECT 2280.1 194.95 2287.9 195.75 ;
    END
  END IO_S<14>
  PIN IO_S<13>
    DIRECTION INOUT ;
    USE SIGNAL ;
    PORT
      LAYER METAL2 ;
        RECT 2174.1 194.95 2181.9 195.75 ;
    END
  END IO_S<13>
  PIN IO_S<12>
    DIRECTION INOUT ;
    USE SIGNAL ;
    PORT
      LAYER METAL2 ;
        RECT 2068.1 194.95 2075.9 195.75 ;
    END
  END IO_S<12>
  PIN IO_S<11>
    DIRECTION INOUT ;
    USE SIGNAL ;
    PORT
      LAYER METAL2 ;
        RECT 1962.1 194.95 1969.9 195.75 ;
    END
  END IO_S<11>
  PIN IO_S<10>
    DIRECTION INOUT ;
    USE SIGNAL ;
    PORT
      LAYER METAL2 ;
        RECT 1856.1 194.95 1863.9 195.75 ;
    END
  END IO_S<10>
  PIN IO_S<9>
    DIRECTION INOUT ;
    USE SIGNAL ;
    PORT
      LAYER METAL2 ;
        RECT 1750.1 194.95 1757.9 195.75 ;
    END
  END IO_S<9>
  PIN IO_S<8>
    DIRECTION INOUT ;
    USE SIGNAL ;
    PORT
      LAYER METAL2 ;
        RECT 1644.1 194.95 1651.9 195.75 ;
    END
  END IO_S<8>
  PIN IO_S<7>
    DIRECTION INOUT ;
    USE SIGNAL ;
    PORT
      LAYER METAL2 ;
        RECT 1538.1 194.95 1545.9 195.75 ;
    END
  END IO_S<7>
  PIN IO_S<6>
    DIRECTION INOUT ;
    USE SIGNAL ;
    PORT
      LAYER METAL2 ;
        RECT 1432.1 194.95 1439.9 195.75 ;
    END
  END IO_S<6>
  PIN IO_S<5>
    DIRECTION INOUT ;
    USE SIGNAL ;
    PORT
      LAYER METAL2 ;
        RECT 1326.1 194.95 1333.9 195.75 ;
    END
  END IO_S<5>
  PIN IO_S<4>
    DIRECTION INOUT ;
    USE SIGNAL ;
    PORT
      LAYER METAL2 ;
        RECT 1220.1 194.95 1227.9 195.75 ;
    END
  END IO_S<4>
  PIN IO_S<3>
    DIRECTION INOUT ;
    USE SIGNAL ;
    PORT
      LAYER METAL2 ;
        RECT 1114.1 194.95 1121.9 195.75 ;
    END
  END IO_S<3>
  PIN IO_S<2>
    DIRECTION INOUT ;
    USE SIGNAL ;
    PORT
      LAYER METAL2 ;
        RECT 1008.1 194.95 1015.9 195.75 ;
    END
  END IO_S<2>
  PIN IO_S<1>
    DIRECTION INOUT ;
    USE SIGNAL ;
    PORT
      LAYER METAL2 ;
        RECT 902.1 194.95 909.9 195.75 ;
    END
  END IO_S<1>
  PIN IO_S<0>
    DIRECTION INOUT ;
    USE SIGNAL ;
    PORT
      LAYER METAL2 ;
        RECT 796.1 194.95 803.9 195.75 ;
    END
  END IO_S<0>
  PIN DVDD_S<0>
    DIRECTION INOUT ;
    USE SIGNAL ;
    PORT
      LAYER METAL2 ;
        RECT 690.1 194.95 697.9 195.75 ;
    END
  END DVDD_S<0>
  PIN IO_E<8>
    DIRECTION INOUT ;
    USE SIGNAL ;
    PORT
      LAYER METAL2 ;
        RECT 6705.1 4400.95 6705.9 4408.75 ;
    END
  END IO_E<8>
  PIN IO_E<7>
    DIRECTION INOUT ;
    USE SIGNAL ;
    PORT
      LAYER METAL2 ;
        RECT 6705.1 4506.95 6705.9 4514.75 ;
    END
  END IO_E<7>
  PIN IO_E<6>
    DIRECTION INOUT ;
    USE SIGNAL ;
    PORT
      LAYER METAL2 ;
        RECT 6705.1 4612.95 6705.9 4620.75 ;
    END
  END IO_E<6>
  PIN IO_E<5>
    DIRECTION INOUT ;
    USE SIGNAL ;
    PORT
      LAYER METAL2 ;
        RECT 6705.1 4718.95 6705.9 4726.75 ;
    END
  END IO_E<5>
  PIN IO_E<4>
    DIRECTION INOUT ;
    USE SIGNAL ;
    PORT
      LAYER METAL2 ;
        RECT 6705.1 4824.95 6705.9 4832.75 ;
    END
  END IO_E<4>
  PIN IO_E<3>
    DIRECTION INOUT ;
    USE SIGNAL ;
    PORT
      LAYER METAL2 ;
        RECT 6705.1 4930.95 6705.9 4938.75 ;
    END
  END IO_E<3>
  PIN IO_E<2>
    DIRECTION INOUT ;
    USE SIGNAL ;
    PORT
      LAYER METAL2 ;
        RECT 6705.1 5036.95 6705.9 5044.75 ;
    END
  END IO_E<2>
  PIN IO_E<1>
    DIRECTION INOUT ;
    USE SIGNAL ;
    PORT
      LAYER METAL2 ;
        RECT 6705.1 5142.95 6705.9 5150.75 ;
    END
  END IO_E<1>
  PIN IO_E<0>
    DIRECTION INOUT ;
    USE SIGNAL ;
    PORT
      LAYER METAL2 ;
        RECT 6705.1 5248.95 6705.9 5256.75 ;
    END
  END IO_E<0>
  PIN IO_W<42>
    DIRECTION INOUT ;
    USE SIGNAL ;
    PORT
      LAYER METAL2 ;
        RECT 194.1 266.95 194.9 274.75 ;
    END
  END IO_W<42>
  PIN IO_W<41>
    DIRECTION INOUT ;
    USE SIGNAL ;
    PORT
      LAYER METAL2 ;
        RECT 194.1 372.95 194.9 380.75 ;
    END
  END IO_W<41>
  PIN IO_W<40>
    DIRECTION INOUT ;
    USE SIGNAL ;
    PORT
      LAYER METAL2 ;
        RECT 194.1 478.95 194.9 486.75 ;
    END
  END IO_W<40>
  PIN IO_W<39>
    DIRECTION INOUT ;
    USE SIGNAL ;
    PORT
      LAYER METAL2 ;
        RECT 194.1 584.95 194.9 592.75 ;
    END
  END IO_W<39>
  PIN IO_W<38>
    DIRECTION INOUT ;
    USE SIGNAL ;
    PORT
      LAYER METAL2 ;
        RECT 194.1 690.95 194.9 698.75 ;
    END
  END IO_W<38>
  PIN IO_W<37>
    DIRECTION INOUT ;
    USE SIGNAL ;
    PORT
      LAYER METAL2 ;
        RECT 194.1 796.95 194.9 804.75 ;
    END
  END IO_W<37>
  PIN IO_W<36>
    DIRECTION INOUT ;
    USE SIGNAL ;
    PORT
      LAYER METAL2 ;
        RECT 194.1 902.95 194.9 910.75 ;
    END
  END IO_W<36>
  PIN IO_W<35>
    DIRECTION INOUT ;
    USE SIGNAL ;
    PORT
      LAYER METAL2 ;
        RECT 194.1 1008.95 194.9 1016.75 ;
    END
  END IO_W<35>
  PIN IO_W<34>
    DIRECTION INOUT ;
    USE SIGNAL ;
    PORT
      LAYER METAL2 ;
        RECT 194.1 1114.95 194.9 1122.75 ;
    END
  END IO_W<34>
  PIN IO_W<33>
    DIRECTION INOUT ;
    USE SIGNAL ;
    PORT
      LAYER METAL2 ;
        RECT 194.1 1220.95 194.9 1228.75 ;
    END
  END IO_W<33>
  PIN IO_W<32>
    DIRECTION INOUT ;
    USE SIGNAL ;
    PORT
      LAYER METAL2 ;
        RECT 194.1 1326.95 194.9 1334.75 ;
    END
  END IO_W<32>
  PIN IO_W<31>
    DIRECTION INOUT ;
    USE SIGNAL ;
    PORT
      LAYER METAL2 ;
        RECT 194.1 1432.95 194.9 1440.75 ;
    END
  END IO_W<31>
  PIN IO_W<30>
    DIRECTION INOUT ;
    USE SIGNAL ;
    PORT
      LAYER METAL2 ;
        RECT 194.1 1538.95 194.9 1546.75 ;
    END
  END IO_W<30>
  PIN IO_W<29>
    DIRECTION INOUT ;
    USE SIGNAL ;
    PORT
      LAYER METAL2 ;
        RECT 194.1 1644.95 194.9 1652.75 ;
    END
  END IO_W<29>
  PIN IO_W<28>
    DIRECTION INOUT ;
    USE SIGNAL ;
    PORT
      LAYER METAL2 ;
        RECT 194.1 1750.95 194.9 1758.75 ;
    END
  END IO_W<28>
  PIN IO_W<27>
    DIRECTION INOUT ;
    USE SIGNAL ;
    PORT
      LAYER METAL2 ;
        RECT 194.1 1856.95 194.9 1864.75 ;
    END
  END IO_W<27>
  PIN IO_W<26>
    DIRECTION INOUT ;
    USE SIGNAL ;
    PORT
      LAYER METAL2 ;
        RECT 194.1 1962.95 194.9 1970.75 ;
    END
  END IO_W<26>
  PIN IO_W<25>
    DIRECTION INOUT ;
    USE SIGNAL ;
    PORT
      LAYER METAL2 ;
        RECT 194.1 2068.95 194.9 2076.75 ;
    END
  END IO_W<25>
  PIN IO_W<24>
    DIRECTION INOUT ;
    USE SIGNAL ;
    PORT
      LAYER METAL2 ;
        RECT 194.1 2174.95 194.9 2182.75 ;
    END
  END IO_W<24>
  PIN IO_W<23>
    DIRECTION INOUT ;
    USE SIGNAL ;
    PORT
      LAYER METAL2 ;
        RECT 194.1 2280.95 194.9 2288.75 ;
    END
  END IO_W<23>
  PIN IO_W<22>
    DIRECTION INOUT ;
    USE SIGNAL ;
    PORT
      LAYER METAL2 ;
        RECT 194.1 2386.95 194.9 2394.75 ;
    END
  END IO_W<22>
  PIN IO_W<21>
    DIRECTION INOUT ;
    USE SIGNAL ;
    PORT
      LAYER METAL2 ;
        RECT 194.1 2492.95 194.9 2500.75 ;
    END
  END IO_W<21>
  PIN DVDD_W<0>
    DIRECTION INOUT ;
    USE SIGNAL ;
    PORT
      LAYER METAL2 ;
        RECT 194.1 2598.95 194.9 2606.75 ;
    END
  END DVDD_W<0>
  PIN IO_W<20>
    DIRECTION INOUT ;
    USE SIGNAL ;
    PORT
      LAYER METAL2 ;
        RECT 194.1 3128.95 194.9 3136.75 ;
    END
  END IO_W<20>
  PIN IO_W<19>
    DIRECTION INOUT ;
    USE SIGNAL ;
    PORT
      LAYER METAL2 ;
        RECT 194.1 3234.95 194.9 3242.75 ;
    END
  END IO_W<19>
  PIN IO_W<18>
    DIRECTION INOUT ;
    USE SIGNAL ;
    PORT
      LAYER METAL2 ;
        RECT 194.1 3340.95 194.9 3348.75 ;
    END
  END IO_W<18>
  PIN IO_W<17>
    DIRECTION INOUT ;
    USE SIGNAL ;
    PORT
      LAYER METAL2 ;
        RECT 194.1 3446.95 194.9 3454.75 ;
    END
  END IO_W<17>
  PIN IO_W<16>
    DIRECTION INOUT ;
    USE SIGNAL ;
    PORT
      LAYER METAL2 ;
        RECT 194.1 3552.95 194.9 3560.75 ;
    END
  END IO_W<16>
  PIN IO_W<15>
    DIRECTION INOUT ;
    USE SIGNAL ;
    PORT
      LAYER METAL2 ;
        RECT 194.1 3658.95 194.9 3666.75 ;
    END
  END IO_W<15>
  PIN IO_W<14>
    DIRECTION INOUT ;
    USE SIGNAL ;
    PORT
      LAYER METAL2 ;
        RECT 194.1 3764.95 194.9 3772.75 ;
    END
  END IO_W<14>
  PIN IO_W<13>
    DIRECTION INOUT ;
    USE SIGNAL ;
    PORT
      LAYER METAL2 ;
        RECT 194.1 3870.95 194.9 3878.75 ;
    END
  END IO_W<13>
  PIN IO_W<12>
    DIRECTION INOUT ;
    USE SIGNAL ;
    PORT
      LAYER METAL2 ;
        RECT 194.1 3976.95 194.9 3984.75 ;
    END
  END IO_W<12>
  PIN IO_W<11>
    DIRECTION INOUT ;
    USE SIGNAL ;
    PORT
      LAYER METAL2 ;
        RECT 194.1 4082.95 194.9 4090.75 ;
    END
  END IO_W<11>
  PIN IO_W<10>
    DIRECTION INOUT ;
    USE SIGNAL ;
    PORT
      LAYER METAL2 ;
        RECT 194.1 4188.95 194.9 4196.75 ;
    END
  END IO_W<10>
  PIN IO_W<9>
    DIRECTION INOUT ;
    USE SIGNAL ;
    PORT
      LAYER METAL2 ;
        RECT 194.1 4294.95 194.9 4302.75 ;
    END
  END IO_W<9>
  PIN IO_W<8>
    DIRECTION INOUT ;
    USE SIGNAL ;
    PORT
      LAYER METAL2 ;
        RECT 194.1 4400.95 194.9 4408.75 ;
    END
  END IO_W<8>
  PIN IO_W<7>
    DIRECTION INOUT ;
    USE SIGNAL ;
    PORT
      LAYER METAL2 ;
        RECT 194.1 4506.95 194.9 4514.75 ;
    END
  END IO_W<7>
  PIN IO_W<6>
    DIRECTION INOUT ;
    USE SIGNAL ;
    PORT
      LAYER METAL2 ;
        RECT 194.1 4612.95 194.9 4620.75 ;
    END
  END IO_W<6>
  PIN IO_W<5>
    DIRECTION INOUT ;
    USE SIGNAL ;
    PORT
      LAYER METAL2 ;
        RECT 194.1 4718.95 194.9 4726.75 ;
    END
  END IO_W<5>
  PIN IO_W<4>
    DIRECTION INOUT ;
    USE SIGNAL ;
    PORT
      LAYER METAL2 ;
        RECT 194.1 4824.95 194.9 4832.75 ;
    END
  END IO_W<4>
  PIN IO_W<3>
    DIRECTION INOUT ;
    USE SIGNAL ;
    PORT
      LAYER METAL2 ;
        RECT 194.1 4930.95 194.9 4938.75 ;
    END
  END IO_W<3>
  PIN IO_W<2>
    DIRECTION INOUT ;
    USE SIGNAL ;
    PORT
      LAYER METAL2 ;
        RECT 194.1 5036.95 194.9 5044.75 ;
    END
  END IO_W<2>
  PIN IO_E<42>
    DIRECTION INOUT ;
    USE SIGNAL ;
    PORT
      LAYER METAL2 ;
        RECT 6705.1 266.95 6705.9 274.75 ;
    END
  END IO_E<42>
  PIN IO_E<41>
    DIRECTION INOUT ;
    USE SIGNAL ;
    PORT
      LAYER METAL2 ;
        RECT 6705.1 372.95 6705.9 380.75 ;
    END
  END IO_E<41>
  PIN IO_E<40>
    DIRECTION INOUT ;
    USE SIGNAL ;
    PORT
      LAYER METAL2 ;
        RECT 6705.1 478.95 6705.9 486.75 ;
    END
  END IO_E<40>
  PIN IO_E<39>
    DIRECTION INOUT ;
    USE SIGNAL ;
    PORT
      LAYER METAL2 ;
        RECT 6705.1 584.95 6705.9 592.75 ;
    END
  END IO_E<39>
  PIN IO_E<38>
    DIRECTION INOUT ;
    USE SIGNAL ;
    PORT
      LAYER METAL2 ;
        RECT 6705.1 690.95 6705.9 698.75 ;
    END
  END IO_E<38>
  PIN IO_E<37>
    DIRECTION INOUT ;
    USE SIGNAL ;
    PORT
      LAYER METAL2 ;
        RECT 6705.1 796.95 6705.9 804.75 ;
    END
  END IO_E<37>
  PIN IO_E<36>
    DIRECTION INOUT ;
    USE SIGNAL ;
    PORT
      LAYER METAL2 ;
        RECT 6705.1 902.95 6705.9 910.75 ;
    END
  END IO_E<36>
  PIN IO_E<35>
    DIRECTION INOUT ;
    USE SIGNAL ;
    PORT
      LAYER METAL2 ;
        RECT 6705.1 1008.95 6705.9 1016.75 ;
    END
  END IO_E<35>
  PIN IO_E<34>
    DIRECTION INOUT ;
    USE SIGNAL ;
    PORT
      LAYER METAL2 ;
        RECT 6705.1 1114.95 6705.9 1122.75 ;
    END
  END IO_E<34>
  PIN IO_E<33>
    DIRECTION INOUT ;
    USE SIGNAL ;
    PORT
      LAYER METAL2 ;
        RECT 6705.1 1220.95 6705.9 1228.75 ;
    END
  END IO_E<33>
  PIN IO_E<32>
    DIRECTION INOUT ;
    USE SIGNAL ;
    PORT
      LAYER METAL2 ;
        RECT 6705.1 1326.95 6705.9 1334.75 ;
    END
  END IO_E<32>
  PIN IO_E<31>
    DIRECTION INOUT ;
    USE SIGNAL ;
    PORT
      LAYER METAL2 ;
        RECT 6705.1 1432.95 6705.9 1440.75 ;
    END
  END IO_E<31>
  PIN IO_E<30>
    DIRECTION INOUT ;
    USE SIGNAL ;
    PORT
      LAYER METAL2 ;
        RECT 6705.1 1538.95 6705.9 1546.75 ;
    END
  END IO_E<30>
  PIN IO_E<29>
    DIRECTION INOUT ;
    USE SIGNAL ;
    PORT
      LAYER METAL2 ;
        RECT 6705.1 1644.95 6705.9 1652.75 ;
    END
  END IO_E<29>
  PIN IO_E<28>
    DIRECTION INOUT ;
    USE SIGNAL ;
    PORT
      LAYER METAL2 ;
        RECT 6705.1 1750.95 6705.9 1758.75 ;
    END
  END IO_E<28>
  PIN IO_E<27>
    DIRECTION INOUT ;
    USE SIGNAL ;
    PORT
      LAYER METAL2 ;
        RECT 6705.1 1856.95 6705.9 1864.75 ;
    END
  END IO_E<27>
  PIN IO_E<26>
    DIRECTION INOUT ;
    USE SIGNAL ;
    PORT
      LAYER METAL2 ;
        RECT 6705.1 1962.95 6705.9 1970.75 ;
    END
  END IO_E<26>
  PIN IO_E<25>
    DIRECTION INOUT ;
    USE SIGNAL ;
    PORT
      LAYER METAL2 ;
        RECT 6705.1 2068.95 6705.9 2076.75 ;
    END
  END IO_E<25>
  PIN IO_E<24>
    DIRECTION INOUT ;
    USE SIGNAL ;
    PORT
      LAYER METAL2 ;
        RECT 6705.1 2174.95 6705.9 2182.75 ;
    END
  END IO_E<24>
  PIN IO_E<23>
    DIRECTION INOUT ;
    USE SIGNAL ;
    PORT
      LAYER METAL2 ;
        RECT 6705.1 2280.95 6705.9 2288.75 ;
    END
  END IO_E<23>
  PIN IO_E<22>
    DIRECTION INOUT ;
    USE SIGNAL ;
    PORT
      LAYER METAL2 ;
        RECT 6705.1 2386.95 6705.9 2394.75 ;
    END
  END IO_E<22>
  PIN IO_E<21>
    DIRECTION INOUT ;
    USE SIGNAL ;
    PORT
      LAYER METAL2 ;
        RECT 6705.1 2492.95 6705.9 2500.75 ;
    END
  END IO_E<21>
  PIN DVDD_E<0>
    DIRECTION INOUT ;
    USE SIGNAL ;
    PORT
      LAYER METAL2 ;
        RECT 6705.1 2598.95 6705.9 2606.75 ;
    END
  END DVDD_E<0>
  PIN IO_E<20>
    DIRECTION INOUT ;
    USE SIGNAL ;
    PORT
      LAYER METAL2 ;
        RECT 6705.1 3128.95 6705.9 3136.75 ;
    END
  END IO_E<20>
  PIN IO_E<19>
    DIRECTION INOUT ;
    USE SIGNAL ;
    PORT
      LAYER METAL2 ;
        RECT 6705.1 3234.95 6705.9 3242.75 ;
    END
  END IO_E<19>
  PIN IO_E<18>
    DIRECTION INOUT ;
    USE SIGNAL ;
    PORT
      LAYER METAL2 ;
        RECT 6705.1 3340.95 6705.9 3348.75 ;
    END
  END IO_E<18>
  PIN IO_E<17>
    DIRECTION INOUT ;
    USE SIGNAL ;
    PORT
      LAYER METAL2 ;
        RECT 6705.1 3446.95 6705.9 3454.75 ;
    END
  END IO_E<17>
  PIN IO_E<16>
    DIRECTION INOUT ;
    USE SIGNAL ;
    PORT
      LAYER METAL2 ;
        RECT 6705.1 3552.95 6705.9 3560.75 ;
    END
  END IO_E<16>
  PIN IO_E<15>
    DIRECTION INOUT ;
    USE SIGNAL ;
    PORT
      LAYER METAL2 ;
        RECT 6705.1 3658.95 6705.9 3666.75 ;
    END
  END IO_E<15>
  PIN IO_E<14>
    DIRECTION INOUT ;
    USE SIGNAL ;
    PORT
      LAYER METAL2 ;
        RECT 6705.1 3764.95 6705.9 3772.75 ;
    END
  END IO_E<14>
  PIN IO_E<13>
    DIRECTION INOUT ;
    USE SIGNAL ;
    PORT
      LAYER METAL2 ;
        RECT 6705.1 3870.95 6705.9 3878.75 ;
    END
  END IO_E<13>
  PIN IO_E<12>
    DIRECTION INOUT ;
    USE SIGNAL ;
    PORT
      LAYER METAL2 ;
        RECT 6705.1 3976.95 6705.9 3984.75 ;
    END
  END IO_E<12>
  PIN IO_E<11>
    DIRECTION INOUT ;
    USE SIGNAL ;
    PORT
      LAYER METAL2 ;
        RECT 6705.1 4082.95 6705.9 4090.75 ;
    END
  END IO_E<11>
  PIN IO_E<10>
    DIRECTION INOUT ;
    USE SIGNAL ;
    PORT
      LAYER METAL2 ;
        RECT 6705.1 4188.95 6705.9 4196.75 ;
    END
  END IO_E<10>
  PIN IO_E<9>
    DIRECTION INOUT ;
    USE SIGNAL ;
    PORT
      LAYER METAL2 ;
        RECT 6705.1 4294.95 6705.9 4302.75 ;
    END
  END IO_E<9>
  PIN AVDD
    DIRECTION INOUT ;
    USE SIGNAL ;
    PORT
      LAYER METAL4 ;
        RECT 188.06 5964.84 192.24 5967.47 ;
    END
  END AVDD
  PIN GND
    DIRECTION INOUT ;
    USE SIGNAL ;
    PORT
      LAYER METAL4 ;
        RECT 180.1 5975.17 185.76 5977.6 ;
    END
  END GND
  PIN VINJ
    DIRECTION INOUT ;
    USE SIGNAL ;
    PORT
      LAYER METAL4 ;
        RECT 167.76 5980.57 172.21 5982.86 ;
    END
  END VINJ
  PIN ESDVDD
    DIRECTION INOUT ;
    USE SIGNAL ;
    PORT
      LAYER METAL4 ;
        RECT 164.19 5989.57 166.58 5990.75 ;
    END
  END ESDVDD
END frame_6p9mm_6p2mm_digbuf

MACRO TSMC350nm_AnalogBuffer
  PIN Vd_P
    DIRECTION INOUT ;
    USE SIGNAL ;
    PORT
      LAYER METAL1 ;
        RECT 0.0 9.34 1.4 10.74 ;
    END
  END Vd_P
  PIN Vin
    DIRECTION INOUT ;
    USE SIGNAL ;
    PORT
      LAYER METAL1 ;
        RECT 0.0 1.34 1.4 2.74 ;
    END
  END Vin
  PIN VDD_b
    DIRECTION INOUT ;
    USE SIGNAL ;
    PORT
      LAYER METAL2 ;
        RECT 78.18 0.0 79.58 1.4 ;
    END
  END VDD_b
  PIN GND_b
    DIRECTION INOUT ;
    USE SIGNAL ;
    PORT
      LAYER METAL2 ;
        RECT 43.36 0.0 44.76 1.4 ;
    END
  END GND_b
  PIN VTUN_b
    DIRECTION INOUT ;
    USE SIGNAL ;
    PORT
      LAYER METAL2 ;
        RECT 1.9 0.0 3.3 1.4 ;
    END
  END VTUN_b
  PIN Vg_b
    DIRECTION INOUT ;
    USE SIGNAL ;
    PORT
      LAYER METAL2 ;
        RECT 4.75 0.0 6.15 1.4 ;
    END
  END Vg_b
  PIN VINJ_b
    DIRECTION INOUT ;
    USE SIGNAL ;
    PORT
      LAYER METAL2 ;
        RECT 8.37 0.0 9.77 1.4 ;
    END
  END VINJ_b
  PIN Vsel_b
    DIRECTION INOUT ;
    USE SIGNAL ;
    PORT
      LAYER METAL2 ;
        RECT 12.03 0.0 13.43 1.4 ;
    END
  END Vsel_b
  PIN Vout
    DIRECTION INOUT ;
    USE SIGNAL ;
    PORT
      LAYER METAL2 ;
        RECT 87.38 16.98 88.78 18.38 ;
    END
  END Vout
  PIN VDD
    DIRECTION INOUT ;
    USE SIGNAL ;
    PORT
      LAYER METAL2 ;
        RECT 78.18 20.6 79.58 22.0 ;
    END
  END VDD
  PIN GND
    DIRECTION INOUT ;
    USE SIGNAL ;
    PORT
      LAYER METAL2 ;
        RECT 43.36 20.6 44.76 22.0 ;
    END
  END GND
  PIN Vsel
    DIRECTION INOUT ;
    USE SIGNAL ;
    PORT
      LAYER METAL2 ;
        RECT 12.03 20.6 13.43 22.0 ;
    END
  END Vsel
  PIN VINJ
    DIRECTION INOUT ;
    USE SIGNAL ;
    PORT
      LAYER METAL2 ;
        RECT 8.37 20.6 9.77 22.0 ;
    END
  END VINJ
  PIN Vg
    DIRECTION INOUT ;
    USE SIGNAL ;
    PORT
      LAYER METAL2 ;
        RECT 4.75 20.6 6.15 22.0 ;
    END
  END Vg
  PIN VTUN
    DIRECTION INOUT ;
    USE SIGNAL ;
    PORT
      LAYER METAL2 ;
        RECT 1.9 20.6 3.3 22.0 ;
    END
  END VTUN
END TSMC350nm_AnalogBuffer

END LIBRARY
